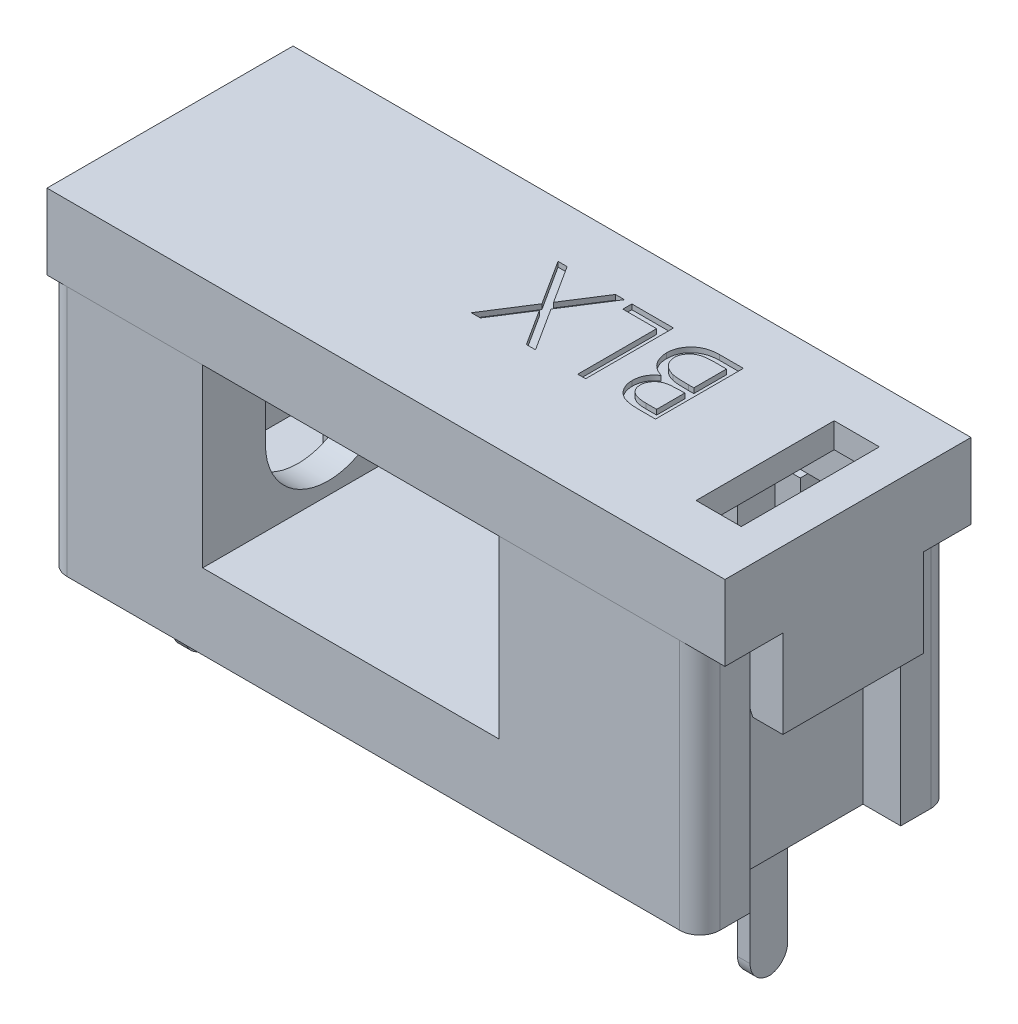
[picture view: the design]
ISO-10303-21;
HEADER;
FILE_DESCRIPTION(('STEP AP214'),'2;1');
FILE_NAME('part.step','',(''),(''),'','','');
FILE_SCHEMA(('AUTOMOTIVE_DESIGN { 1 0 10303 214 1 1 1 1 }'));
ENDSEC;
DATA;
#1=APPLICATION_CONTEXT('core data for automotive mechanical design processes');
#2=APPLICATION_PROTOCOL_DEFINITION('international standard','automotive_design',2000,#1);
#3=PRODUCT_CONTEXT('',#1,'mechanical');
#4=PRODUCT('Part','Part','',(#3));
#5=PRODUCT_RELATED_PRODUCT_CATEGORY('part','',(#4));
#6=PRODUCT_DEFINITION_FORMATION('','',#4);
#7=PRODUCT_DEFINITION_CONTEXT('part definition',#1,'design');
#8=PRODUCT_DEFINITION('design','',#6,#7);
#9=PRODUCT_DEFINITION_SHAPE('','',#8);
#10=(LENGTH_UNIT() NAMED_UNIT(*) SI_UNIT(.MILLI.,.METRE.));
#11=(NAMED_UNIT(*) PLANE_ANGLE_UNIT() SI_UNIT($,.RADIAN.));
#12=(NAMED_UNIT(*) SI_UNIT($,.STERADIAN.) SOLID_ANGLE_UNIT());
#13=UNCERTAINTY_MEASURE_WITH_UNIT(LENGTH_MEASURE(1.E-05),#10,'distance_accuracy_value','');
#14=(GEOMETRIC_REPRESENTATION_CONTEXT(3) GLOBAL_UNCERTAINTY_ASSIGNED_CONTEXT((#13)) GLOBAL_UNIT_ASSIGNED_CONTEXT((#10,
#11,#12)) REPRESENTATION_CONTEXT('',''));
#15=CARTESIAN_POINT('',(0.,0.,0.));
#16=DIRECTION('',(0.,0.,1.));
#17=DIRECTION('',(1.,0.,0.));
#18=AXIS2_PLACEMENT_3D('',#15,#16,#17);
#19=CARTESIAN_POINT('',(8.56778460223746,21.1022223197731,22.8683332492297));
#20=DIRECTION('',(0.,1.,0.));
#21=DIRECTION('',(1.,0.,0.));
#22=AXIS2_PLACEMENT_3D('',#19,#20,#21);
#23=PLANE('',#22);
#24=DIRECTION('',(1.,0.,0.));
#25=VECTOR('',#24,1.);
#26=CARTESIAN_POINT('',(10.709614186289,21.1022223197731,20.1183332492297));
#27=LINE('',#26,#25);
#28=CARTESIAN_POINT('',(10.709614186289,21.1022223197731,20.1183332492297));
#29=VERTEX_POINT('',#28);
#30=CARTESIAN_POINT('',(12.3698705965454,21.1022223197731,20.1183332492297));
#31=VERTEX_POINT('',#30);
#32=EDGE_CURVE('P0_E960',#29,#31,#27,.T.);
#33=ORIENTED_EDGE('',*,*,#32,.T.);
#34=DIRECTION('',(0.,0.,1.));
#35=VECTOR('',#34,1.);
#36=CARTESIAN_POINT('',(12.3698705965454,21.1022223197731,20.1183332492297));
#37=LINE('',#36,#35);
#38=CARTESIAN_POINT('',(12.3698705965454,21.1022223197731,23.6183332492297));
#39=VERTEX_POINT('',#38);
#40=EDGE_CURVE('P0_E859',#31,#39,#37,.T.);
#41=ORIENTED_EDGE('',*,*,#40,.T.);
#42=DIRECTION('',(-1.,0.,0.));
#43=VECTOR('',#42,1.);
#44=CARTESIAN_POINT('',(12.3698705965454,21.1022223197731,23.6183332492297));
#45=LINE('',#44,#43);
#46=CARTESIAN_POINT('',(12.0557680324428,21.1022223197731,23.6183332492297));
#47=VERTEX_POINT('',#46);
#48=EDGE_CURVE('P0_E973',#39,#47,#45,.T.);
#49=ORIENTED_EDGE('',*,*,#48,.T.);
#50=DIRECTION('',(0.,0.,-1.));
#51=VECTOR('',#50,1.);
#52=CARTESIAN_POINT('',(12.0557680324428,21.1022223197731,23.6183332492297));
#53=LINE('',#52,#51);
#54=CARTESIAN_POINT('',(12.0557680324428,21.1022223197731,20.4773076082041));
#55=VERTEX_POINT('',#54);
#56=EDGE_CURVE('P0_E970',#47,#55,#53,.T.);
#57=ORIENTED_EDGE('',*,*,#56,.T.);
#58=DIRECTION('',(-1.,0.,0.));
#59=VECTOR('',#58,1.);
#60=CARTESIAN_POINT('',(12.0557680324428,21.1022223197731,20.4773076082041));
#61=LINE('',#60,#59);
#62=CARTESIAN_POINT('',(10.709614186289,21.1022223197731,20.4773076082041));
#63=VERTEX_POINT('',#62);
#64=EDGE_CURVE('P0_E967',#55,#63,#61,.T.);
#65=ORIENTED_EDGE('',*,*,#64,.T.);
#66=DIRECTION('',(0.,0.,-1.));
#67=VECTOR('',#66,1.);
#68=CARTESIAN_POINT('',(10.709614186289,21.1022223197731,20.4773076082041));
#69=LINE('',#68,#67);
#70=EDGE_CURVE('P0_E964',#63,#29,#69,.T.);
#71=ORIENTED_EDGE('',*,*,#70,.T.);
#72=EDGE_LOOP('',(#33,#41,#49,#57,#65,#71));
#73=FACE_BOUND('',#72,.T.);
#74=DIRECTION('',(-0.539185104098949,0.,0.842187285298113));
#75=VECTOR('',#74,1.);
#76=CARTESIAN_POINT('',(10.4179475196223,21.1022223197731,20.1183332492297));
#77=LINE('',#76,#75);
#78=CARTESIAN_POINT('',(10.4179475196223,21.1022223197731,20.1183332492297));
#79=VERTEX_POINT('',#78);
#80=CARTESIAN_POINT('',(9.27511899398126,21.1022223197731,21.9033893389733));
#81=VERTEX_POINT('',#80);
#82=EDGE_CURVE('P0_E884',#79,#81,#77,.T.);
#83=ORIENTED_EDGE('',*,*,#82,.T.);
#84=DIRECTION('',(0.539190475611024,0.,0.842183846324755));
#85=VECTOR('',#84,1.);
#86=CARTESIAN_POINT('',(9.27511899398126,21.1022223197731,21.9033893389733));
#87=LINE('',#86,#85);
#88=CARTESIAN_POINT('',(10.3730757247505,21.1022223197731,23.6183332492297));
#89=VERTEX_POINT('',#88);
#90=EDGE_CURVE('P0_E918',#81,#89,#87,.T.);
#91=ORIENTED_EDGE('',*,*,#90,.T.);
#92=DIRECTION('',(-1.,0.,0.));
#93=VECTOR('',#92,1.);
#94=CARTESIAN_POINT('',(10.3730757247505,21.1022223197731,23.6183332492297));
#95=LINE('',#94,#93);
#96=CARTESIAN_POINT('',(10.0105957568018,21.1022223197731,23.6183332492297));
#97=VERTEX_POINT('',#96);
#98=EDGE_CURVE('P0_E915',#89,#97,#95,.T.);
#99=ORIENTED_EDGE('',*,*,#98,.T.);
#100=DIRECTION('',(-0.539088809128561,0.,-0.842248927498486));
#101=VECTOR('',#100,1.);
#102=CARTESIAN_POINT('',(10.0105957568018,21.1022223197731,23.6183332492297));
#103=LINE('',#102,#101);
#104=CARTESIAN_POINT('',(9.09422957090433,21.1022223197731,22.1866425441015));
#105=VERTEX_POINT('',#104);
#106=EDGE_CURVE('P0_E912',#97,#105,#103,.T.);
#107=ORIENTED_EDGE('',*,*,#106,.T.);
#108=DIRECTION('',(-0.539088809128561,0.,0.842248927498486));
#109=VECTOR('',#108,1.);
#110=CARTESIAN_POINT('',(9.09422957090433,21.1022223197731,22.1866425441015));
#111=LINE('',#110,#109);
#112=CARTESIAN_POINT('',(8.1778633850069,21.1022223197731,23.6183332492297));
#113=VERTEX_POINT('',#112);
#114=EDGE_CURVE('P0_E909',#105,#113,#111,.T.);
#115=ORIENTED_EDGE('',*,*,#114,.T.);
#116=DIRECTION('',(-1.,0.,0.));
#117=VECTOR('',#116,1.);
#118=CARTESIAN_POINT('',(8.1778633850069,21.1022223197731,23.6183332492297));
#119=LINE('',#118,#117);
#120=CARTESIAN_POINT('',(7.81538341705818,21.1022223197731,23.6183332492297));
#121=VERTEX_POINT('',#120);
#122=EDGE_CURVE('P0_E906',#113,#121,#119,.T.);
#123=ORIENTED_EDGE('',*,*,#122,.T.);
#124=DIRECTION('',(0.538946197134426,0.,-0.842340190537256));
#125=VECTOR('',#124,1.);
#126=CARTESIAN_POINT('',(7.81538341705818,21.1022223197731,23.6183332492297));
#127=LINE('',#126,#125);
#128=CARTESIAN_POINT('',(8.91263902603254,21.1022223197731,21.9033893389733));
#129=VERTEX_POINT('',#128);
#130=EDGE_CURVE('P0_E903',#121,#129,#127,.T.);
#131=ORIENTED_EDGE('',*,*,#130,.T.);
#132=DIRECTION('',(-0.538950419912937,0.,-0.842337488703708));
#133=VECTOR('',#132,1.);
#134=CARTESIAN_POINT('',(8.91263902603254,21.1022223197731,21.9033893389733));
#135=LINE('',#134,#133);
#136=CARTESIAN_POINT('',(7.77051162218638,21.1022223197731,20.1183332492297));
#137=VERTEX_POINT('',#136);
#138=EDGE_CURVE('P0_E900',#129,#137,#135,.T.);
#139=ORIENTED_EDGE('',*,*,#138,.T.);
#140=DIRECTION('',(1.,0.,0.));
#141=VECTOR('',#140,1.);
#142=CARTESIAN_POINT('',(7.77051162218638,21.1022223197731,20.1183332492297));
#143=LINE('',#142,#141);
#144=CARTESIAN_POINT('',(8.1329915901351,21.1022223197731,20.1183332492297));
#145=VERTEX_POINT('',#144);
#146=EDGE_CURVE('P0_E897',#137,#145,#143,.T.);
#147=ORIENTED_EDGE('',*,*,#146,.T.);
#148=DIRECTION('',(0.539087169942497,0.,0.842249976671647));
#149=VECTOR('',#148,1.);
#150=CARTESIAN_POINT('',(8.1329915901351,21.1022223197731,20.1183332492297));
#151=LINE('',#150,#149);
#152=CARTESIAN_POINT('',(9.09422957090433,21.1022223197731,21.6201361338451));
#153=VERTEX_POINT('',#152);
#154=EDGE_CURVE('P0_E894',#145,#153,#151,.T.);
#155=ORIENTED_EDGE('',*,*,#154,.T.);
#156=DIRECTION('',(0.539087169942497,0.,-0.842249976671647));
#157=VECTOR('',#156,1.);
#158=CARTESIAN_POINT('',(9.09422957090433,21.1022223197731,21.6201361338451));
#159=LINE('',#158,#157);
#160=CARTESIAN_POINT('',(10.0554675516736,21.1022223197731,20.1183332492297));
#161=VERTEX_POINT('',#160);
#162=EDGE_CURVE('P0_E891',#153,#161,#159,.T.);
#163=ORIENTED_EDGE('',*,*,#162,.T.);
#164=DIRECTION('',(1.,0.,0.));
#165=VECTOR('',#164,1.);
#166=CARTESIAN_POINT('',(10.0554675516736,21.1022223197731,20.1183332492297));
#167=LINE('',#166,#165);
#168=EDGE_CURVE('P0_E888',#161,#79,#167,.T.);
#169=ORIENTED_EDGE('',*,*,#168,.T.);
#170=EDGE_LOOP('',(#83,#91,#99,#107,#115,#123,#131,#139,#147,#155,#163,#169));
#171=FACE_BOUND('',#170,.T.);
#172=DIRECTION('',(1.,0.,0.));
#173=VECTOR('',#172,1.);
#174=CARTESIAN_POINT('',(-4.93221539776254,21.1022223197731,17.9683332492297));
#175=LINE('',#174,#173);
#176=CARTESIAN_POINT('',(-4.93221539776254,21.1022223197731,17.9683332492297));
#177=VERTEX_POINT('',#176);
#178=CARTESIAN_POINT('',(22.0677846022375,21.1022223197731,17.9683332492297));
#179=VERTEX_POINT('',#178);
#180=EDGE_CURVE('P0_E692',#177,#179,#175,.T.);
#181=ORIENTED_EDGE('',*,*,#180,.F.);
#182=DIRECTION('',(0.,0.,-1.));
#183=VECTOR('',#182,1.);
#184=CARTESIAN_POINT('',(-4.93221539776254,21.1022223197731,27.7683332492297));
#185=LINE('',#184,#183);
#186=CARTESIAN_POINT('',(-4.93221539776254,21.1022223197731,27.7683332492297));
#187=VERTEX_POINT('',#186);
#188=EDGE_CURVE('P0_E701',#187,#177,#185,.T.);
#189=ORIENTED_EDGE('',*,*,#188,.F.);
#190=DIRECTION('',(-1.,0.,0.));
#191=VECTOR('',#190,1.);
#192=CARTESIAN_POINT('',(-4.93221539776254,21.1022223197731,27.7683332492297));
#193=LINE('',#192,#191);
#194=CARTESIAN_POINT('',(22.0677846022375,21.1022223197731,27.7683332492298));
#195=VERTEX_POINT('',#194);
#196=EDGE_CURVE('P0_E691',#195,#187,#193,.T.);
#197=ORIENTED_EDGE('',*,*,#196,.F.);
#198=DIRECTION('',(0.,0.,1.));
#199=VECTOR('',#198,1.);
#200=CARTESIAN_POINT('',(22.0677846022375,21.1022223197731,27.7683332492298));
#201=LINE('',#200,#199);
#202=EDGE_CURVE('P0_E679',#179,#195,#201,.T.);
#203=ORIENTED_EDGE('',*,*,#202,.F.);
#204=EDGE_LOOP('',(#181,#189,#197,#203));
#205=FACE_BOUND('',#204,.T.);
#206=DIRECTION('',(1.,0.,0.));
#207=VECTOR('',#206,1.);
#208=CARTESIAN_POINT('',(18.7677846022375,21.1022223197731,25.6183332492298));
#209=LINE('',#208,#207);
#210=CARTESIAN_POINT('',(18.7677846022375,21.1022223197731,25.6183332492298));
#211=VERTEX_POINT('',#210);
#212=CARTESIAN_POINT('',(20.5677846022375,21.1022223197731,25.6183332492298));
#213=VERTEX_POINT('',#212);
#214=EDGE_CURVE('P0_E814',#211,#213,#209,.T.);
#215=ORIENTED_EDGE('',*,*,#214,.F.);
#216=DIRECTION('',(0.,0.,1.));
#217=VECTOR('',#216,1.);
#218=CARTESIAN_POINT('',(18.7677846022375,21.1022223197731,20.1183332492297));
#219=LINE('',#218,#217);
#220=CARTESIAN_POINT('',(18.7677846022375,21.1022223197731,20.1183332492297));
#221=VERTEX_POINT('',#220);
#222=EDGE_CURVE('P0_E815',#221,#211,#219,.T.);
#223=ORIENTED_EDGE('',*,*,#222,.F.);
#224=DIRECTION('',(-1.,0.,0.));
#225=VECTOR('',#224,1.);
#226=CARTESIAN_POINT('',(20.5677846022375,21.1022223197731,20.1183332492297));
#227=LINE('',#226,#225);
#228=CARTESIAN_POINT('',(20.5677846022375,21.1022223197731,20.1183332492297));
#229=VERTEX_POINT('',#228);
#230=EDGE_CURVE('P0_E733',#229,#221,#227,.T.);
#231=ORIENTED_EDGE('',*,*,#230,.F.);
#232=DIRECTION('',(0.,0.,-1.));
#233=VECTOR('',#232,1.);
#234=CARTESIAN_POINT('',(20.5677846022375,21.1022223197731,25.6183332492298));
#235=LINE('',#234,#233);
#236=EDGE_CURVE('P0_E852',#213,#229,#235,.T.);
#237=ORIENTED_EDGE('',*,*,#236,.F.);
#238=EDGE_LOOP('',(#215,#223,#231,#237));
#239=FACE_BOUND('',#238,.T.);
#240=DIRECTION('',(1.,0.,0.));
#241=VECTOR('',#240,1.);
#242=CARTESIAN_POINT('',(14.2054074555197,21.1022223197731,20.1183332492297));
#243=LINE('',#242,#241);
#244=CARTESIAN_POINT('',(14.2054074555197,21.1022223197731,20.1183332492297));
#245=VERTEX_POINT('',#244);
#246=CARTESIAN_POINT('',(15.1519218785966,21.1022223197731,20.1183332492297));
#247=VERTEX_POINT('',#246);
#248=EDGE_CURVE('P0_E488',#245,#247,#243,.T.);
#249=ORIENTED_EDGE('',*,*,#248,.T.);
#250=DIRECTION('',(0.,0.,1.));
#251=VECTOR('',#250,1.);
#252=CARTESIAN_POINT('',(15.1519218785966,21.1022223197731,20.1183332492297));
#253=LINE('',#252,#251);
#254=CARTESIAN_POINT('',(15.1519218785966,21.1022223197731,23.6183332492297));
#255=VERTEX_POINT('',#254);
#256=EDGE_CURVE('P0_E31',#247,#255,#253,.T.);
#257=ORIENTED_EDGE('',*,*,#256,.T.);
#258=DIRECTION('',(-1.,0.,0.));
#259=VECTOR('',#258,1.);
#260=CARTESIAN_POINT('',(15.1519218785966,21.1022223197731,23.6183332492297));
#261=LINE('',#260,#259);
#262=CARTESIAN_POINT('',(14.4690292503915,21.1022223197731,23.6183332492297));
#263=VERTEX_POINT('',#262);
#264=EDGE_CURVE('P0_E1034',#255,#263,#261,.T.);
#265=ORIENTED_EDGE('',*,*,#264,.T.);
#266=CARTESIAN_POINT('',(14.4690292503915,21.1022223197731,23.6183332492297));
#267=CARTESIAN_POINT('',(14.435600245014,21.1022223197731,23.6181602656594));
#268=CARTESIAN_POINT('',(14.3708065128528,21.1022223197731,23.6178249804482));
#269=CARTESIAN_POINT('',(14.2765942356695,21.1022223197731,23.6125042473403));
#270=CARTESIAN_POINT('',(14.1883206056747,21.1022223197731,23.6054308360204));
#271=CARTESIAN_POINT('',(14.1061416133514,21.1022223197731,23.5935655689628));
#272=CARTESIAN_POINT('',(14.029522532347,21.1022223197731,23.5812628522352));
#273=CARTESIAN_POINT('',(13.9592412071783,21.1022223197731,23.5632054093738));
#274=CARTESIAN_POINT('',(13.894708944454,21.1022223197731,23.5432603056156));
#275=CARTESIAN_POINT('',(13.8172189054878,21.1022223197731,23.5125720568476));
#276=CARTESIAN_POINT('',(13.7292958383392,21.1022223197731,23.4649128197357));
#277=CARTESIAN_POINT('',(13.6347949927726,21.1022223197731,23.3942296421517));
#278=CARTESIAN_POINT('',(13.5526490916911,21.1022223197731,23.3094862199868));
#279=CARTESIAN_POINT('',(13.4828007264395,21.1022223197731,23.2129144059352));
#280=CARTESIAN_POINT('',(13.4267459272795,21.1022223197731,23.1066744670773));
#281=CARTESIAN_POINT('',(13.386705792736,21.1022223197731,22.9930521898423));
#282=CARTESIAN_POINT('',(13.3609824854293,21.1022223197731,22.8739591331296));
#283=CARTESIAN_POINT('',(13.3583702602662,21.1022223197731,22.7923098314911));
#284=CARTESIAN_POINT('',(13.3570500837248,21.1022223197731,22.7510455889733));
#285=B_SPLINE_CURVE_WITH_KNOTS('',3,(#266,#267,#268,#269,#270,#271,#272,#273,#274,#275,#276,
#277,#278,#279,#280,#281,#282,#283,#284),.UNSPECIFIED.,.F.,.F.,(4,1,1,1,1,1,1,1,1,1,1,1,1,1,1,1,
4),(0.,0.0625801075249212,0.12129582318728,0.176640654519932,0.228314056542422,
0.276729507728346,0.321834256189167,0.364044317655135,0.403128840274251,0.477724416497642,
0.550537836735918,0.623256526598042,0.697830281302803,0.772992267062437,0.847315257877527,
0.922835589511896,1.),.UNSPECIFIED.);
#286=CARTESIAN_POINT('',(13.3570500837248,21.1022223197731,22.7510455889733));
#287=VERTEX_POINT('',#286);
#288=EDGE_CURVE('P0_E1026',#263,#287,#285,.T.);
#289=ORIENTED_EDGE('',*,*,#288,.T.);
#290=CARTESIAN_POINT('',(13.3570500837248,21.1022223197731,22.7510455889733));
#291=CARTESIAN_POINT('',(13.3581496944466,21.1022223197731,22.7123947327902));
#292=CARTESIAN_POINT('',(13.3603105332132,21.1022223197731,22.6364421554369));
#293=CARTESIAN_POINT('',(13.380721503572,21.1022223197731,22.525544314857));
#294=CARTESIAN_POINT('',(13.4131166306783,21.1022223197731,22.4200869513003));
#295=CARTESIAN_POINT('',(13.4578880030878,21.1022223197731,22.3201603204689));
#296=CARTESIAN_POINT('',(13.5155734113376,21.1022223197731,22.2276245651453));
#297=CARTESIAN_POINT('',(13.5846886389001,21.1022223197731,22.142766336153));
#298=CARTESIAN_POINT('',(13.6677300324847,21.1022223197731,22.0687928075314));
#299=CARTESIAN_POINT('',(13.7299781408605,21.1022223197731,22.0274529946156));
#300=CARTESIAN_POINT('',(13.7615973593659,21.1022223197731,22.0064542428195));
#301=B_SPLINE_CURVE_WITH_KNOTS('',3,(#290,#291,#292,#293,#294,#295,#296,#297,#298,#299,#300),
.UNSPECIFIED.,.F.,.F.,(4,1,1,1,1,1,1,1,4),(0.,0.130580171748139,0.25660235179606,
0.379828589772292,0.502910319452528,0.625707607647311,0.747527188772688,0.871755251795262,1.),.UNSPECIFIED.);
#302=CARTESIAN_POINT('',(13.7615973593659,21.1022223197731,22.0064542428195));
#303=VERTEX_POINT('',#302);
#304=EDGE_CURVE('P0_E1018',#287,#303,#301,.T.);
#305=ORIENTED_EDGE('',*,*,#304,.T.);
#306=CARTESIAN_POINT('',(13.7615973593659,21.1022223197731,22.0064542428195));
#307=CARTESIAN_POINT('',(13.7218407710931,21.1022223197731,21.9911843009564));
#308=CARTESIAN_POINT('',(13.645776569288,21.1022223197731,21.9619691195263));
#309=CARTESIAN_POINT('',(13.541040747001,21.1022223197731,21.9103977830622));
#310=CARTESIAN_POINT('',(13.4511332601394,21.1022223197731,21.8541027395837));
#311=CARTESIAN_POINT('',(13.3742978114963,21.1022223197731,21.7935755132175));
#312=CARTESIAN_POINT('',(13.3089307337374,21.1022223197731,21.7273713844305));
#313=CARTESIAN_POINT('',(13.2523190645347,21.1022223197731,21.6549524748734));
#314=CARTESIAN_POINT('',(13.2033771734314,21.1022223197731,21.5763780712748));
#315=CARTESIAN_POINT('',(13.1617279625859,21.1022223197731,21.4919369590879));
#316=CARTESIAN_POINT('',(13.1290119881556,21.1022223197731,21.4023449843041));
#317=CARTESIAN_POINT('',(13.1049662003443,21.1022223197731,21.3086964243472));
#318=CARTESIAN_POINT('',(13.0907425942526,21.1022223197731,21.2113502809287));
#319=CARTESIAN_POINT('',(13.0888022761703,21.1022223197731,21.1452892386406));
#320=CARTESIAN_POINT('',(13.0878193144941,21.1022223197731,21.1118228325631));
#321=B_SPLINE_CURVE_WITH_KNOTS('',3,(#306,#307,#308,#309,#310,#311,#312,#313,#314,#315,#316,
#317,#318,#319,#320),.UNSPECIFIED.,.F.,.F.,(4,1,1,1,1,1,1,1,1,1,1,1,4),(0.,0.106048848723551,
0.202897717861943,0.290276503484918,0.369828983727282,0.445983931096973,0.521448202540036,
0.598336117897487,0.676181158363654,0.755560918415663,0.835476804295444,0.916652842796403,1.),.UNSPECIFIED.);
#322=CARTESIAN_POINT('',(13.0878193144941,21.1022223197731,21.1118228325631));
#323=VERTEX_POINT('',#322);
#324=EDGE_CURVE('P0_E1010',#303,#323,#321,.T.);
#325=ORIENTED_EDGE('',*,*,#324,.T.);
#326=CARTESIAN_POINT('',(13.0878193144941,21.1022223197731,21.1118228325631));
#327=CARTESIAN_POINT('',(13.0887959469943,21.1022223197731,21.077655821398));
#328=CARTESIAN_POINT('',(13.0907174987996,21.1022223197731,21.0104312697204));
#329=CARTESIAN_POINT('',(13.1049005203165,21.1022223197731,20.9116781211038));
#330=CARTESIAN_POINT('',(13.1288984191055,21.1022223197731,20.8172958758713));
#331=CARTESIAN_POINT('',(13.1620108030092,21.1022223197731,20.7267175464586));
#332=CARTESIAN_POINT('',(13.20492996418,21.1022223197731,20.6401330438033));
#333=CARTESIAN_POINT('',(13.2579160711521,21.1022223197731,20.5578560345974));
#334=CARTESIAN_POINT('',(13.3202253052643,21.1022223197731,20.479715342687));
#335=CARTESIAN_POINT('',(13.3906448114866,21.1022223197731,20.4055730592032));
#336=CARTESIAN_POINT('',(13.4691218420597,21.1022223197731,20.3377305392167));
#337=CARTESIAN_POINT('',(13.5556085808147,21.1022223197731,20.2794088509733));
#338=CARTESIAN_POINT('',(13.6477357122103,21.1022223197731,20.2292605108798));
#339=CARTESIAN_POINT('',(13.7466809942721,21.1022223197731,20.1884315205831));
#340=CARTESIAN_POINT('',(13.8521918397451,21.1022223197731,20.1569319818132));
#341=CARTESIAN_POINT('',(13.9642095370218,21.1022223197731,20.1349854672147));
#342=CARTESIAN_POINT('',(14.0825496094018,21.1022223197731,20.1201731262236));
#343=CARTESIAN_POINT('',(14.1637599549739,21.1022223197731,20.1189569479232));
#344=CARTESIAN_POINT('',(14.2054074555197,21.1022223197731,20.1183332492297));
#345=B_SPLINE_CURVE_WITH_KNOTS('',3,(#326,#327,#328,#329,#330,#331,#332,#333,#334,#335,#336,
#337,#338,#339,#340,#341,#342,#343,#344),.UNSPECIFIED.,.F.,.F.,(4,1,1,1,1,1,1,1,1,1,1,1,1,1,1,1,
4),(0.,0.061167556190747,0.12034888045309,0.178201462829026,0.235263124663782,0.292717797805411,
0.350875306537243,0.410152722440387,0.471423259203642,0.533743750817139,0.595492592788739,
0.657846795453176,0.721262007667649,0.786797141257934,0.854668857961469,0.925469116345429,1.),.UNSPECIFIED.);
#346=EDGE_CURVE('P0_E1005',#323,#245,#345,.T.);
#347=ORIENTED_EDGE('',*,*,#346,.T.);
#348=EDGE_LOOP('',(#249,#257,#265,#289,#305,#325,#347));
#349=FACE_BOUND('',#348,.T.);
#350=ADVANCED_FACE('P0_F16',(#73,#171,#205,#239,#349),#23,.T.);
#351=CARTESIAN_POINT('',(8.56778460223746,18.1022223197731,22.8683332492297));
#352=DIRECTION('',(0.,1.,0.));
#353=DIRECTION('',(1.,0.,0.));
#354=AXIS2_PLACEMENT_3D('',#351,#352,#353);
#355=PLANE('',#354);
#356=DIRECTION('',(0.,0.,1.));
#357=VECTOR('',#356,1.);
#358=CARTESIAN_POINT('',(20.5677846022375,18.1022223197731,19.4683332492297));
#359=LINE('',#358,#357);
#360=CARTESIAN_POINT('',(20.5677846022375,18.1022223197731,19.4683332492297));
#361=VERTEX_POINT('',#360);
#362=CARTESIAN_POINT('',(20.5677846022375,18.1022223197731,26.2683332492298));
#363=VERTEX_POINT('',#362);
#364=EDGE_CURVE('P0_E761',#361,#363,#359,.T.);
#365=ORIENTED_EDGE('',*,*,#364,.F.);
#366=DIRECTION('',(1.,0.,0.));
#367=VECTOR('',#366,1.);
#368=CARTESIAN_POINT('',(-3.43221539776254,18.1022223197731,19.4683332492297));
#369=LINE('',#368,#367);
#370=CARTESIAN_POINT('',(-3.43221539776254,18.1022223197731,19.4683332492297));
#371=VERTEX_POINT('',#370);
#372=EDGE_CURVE('P0_E759',#371,#361,#369,.T.);
#373=ORIENTED_EDGE('',*,*,#372,.F.);
#374=DIRECTION('',(0.,0.,-1.));
#375=VECTOR('',#374,1.);
#376=CARTESIAN_POINT('',(-3.43221539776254,18.1022223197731,26.2683332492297));
#377=LINE('',#376,#375);
#378=CARTESIAN_POINT('',(-3.43221539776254,18.1022223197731,26.2683332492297));
#379=VERTEX_POINT('',#378);
#380=EDGE_CURVE('P0_E755',#379,#371,#377,.T.);
#381=ORIENTED_EDGE('',*,*,#380,.F.);
#382=DIRECTION('',(-1.,0.,0.));
#383=VECTOR('',#382,1.);
#384=CARTESIAN_POINT('',(20.5677846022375,18.1022223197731,26.2683332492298));
#385=LINE('',#384,#383);
#386=EDGE_CURVE('P0_E753',#363,#379,#385,.T.);
#387=ORIENTED_EDGE('',*,*,#386,.F.);
#388=EDGE_LOOP('',(#365,#373,#381,#387));
#389=FACE_BOUND('',#388,.T.);
#390=DIRECTION('',(1.,0.,0.));
#391=VECTOR('',#390,1.);
#392=CARTESIAN_POINT('',(19.5677846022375,18.1022223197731,19.8683332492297));
#393=LINE('',#392,#391);
#394=CARTESIAN_POINT('',(20.8688043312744,18.1022223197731,19.8683332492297));
#395=VERTEX_POINT('',#394);
#396=CARTESIAN_POINT('',(22.0677846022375,18.1022223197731,19.8683332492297));
#397=VERTEX_POINT('',#396);
#398=EDGE_CURVE('P0_E713',#395,#397,#393,.T.);
#399=ORIENTED_EDGE('',*,*,#398,.F.);
#400=DIRECTION('',(0.,0.,1.));
#401=VECTOR('',#400,1.);
#402=CARTESIAN_POINT('',(20.8688043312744,18.1022223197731,17.9683332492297));
#403=LINE('',#402,#401);
#404=CARTESIAN_POINT('',(20.8688043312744,18.1022223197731,25.4630368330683));
#405=VERTEX_POINT('',#404);
#406=EDGE_CURVE('P0_E837',#395,#405,#403,.T.);
#407=ORIENTED_EDGE('',*,*,#406,.T.);
#408=DIRECTION('',(-1.,0.,0.));
#409=VECTOR('',#408,1.);
#410=CARTESIAN_POINT('',(22.0677846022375,18.1022223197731,25.4630368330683));
#411=LINE('',#410,#409);
#412=CARTESIAN_POINT('',(22.0677846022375,18.1022223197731,25.4630368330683));
#413=VERTEX_POINT('',#412);
#414=EDGE_CURVE('P0_E782',#413,#405,#411,.T.);
#415=ORIENTED_EDGE('',*,*,#414,.F.);
#416=DIRECTION('',(0.,0.,1.));
#417=VECTOR('',#416,1.);
#418=CARTESIAN_POINT('',(22.0677846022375,18.1022223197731,27.7683332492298));
#419=LINE('',#418,#417);
#420=CARTESIAN_POINT('',(22.0677846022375,18.1022223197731,27.7683332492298));
#421=VERTEX_POINT('',#420);
#422=EDGE_CURVE('P0_E771',#413,#421,#419,.T.);
#423=ORIENTED_EDGE('',*,*,#422,.T.);
#424=DIRECTION('',(-1.,0.,0.));
#425=VECTOR('',#424,1.);
#426=CARTESIAN_POINT('',(-4.93221539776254,18.1022223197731,27.7683332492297));
#427=LINE('',#426,#425);
#428=CARTESIAN_POINT('',(-4.93221539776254,18.1022223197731,27.7683332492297));
#429=VERTEX_POINT('',#428);
#430=EDGE_CURVE('P0_E696',#421,#429,#427,.T.);
#431=ORIENTED_EDGE('',*,*,#430,.T.);
#432=DIRECTION('',(0.,0.,-1.));
#433=VECTOR('',#432,1.);
#434=CARTESIAN_POINT('',(-4.93221539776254,18.1022223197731,27.7683332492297));
#435=LINE('',#434,#433);
#436=CARTESIAN_POINT('',(-4.93221539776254,18.1022223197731,17.9683332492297));
#437=VERTEX_POINT('',#436);
#438=EDGE_CURVE('P0_E710',#429,#437,#435,.T.);
#439=ORIENTED_EDGE('',*,*,#438,.T.);
#440=DIRECTION('',(1.,0.,0.));
#441=VECTOR('',#440,1.);
#442=CARTESIAN_POINT('',(-4.93221539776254,18.1022223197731,17.9683332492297));
#443=LINE('',#442,#441);
#444=CARTESIAN_POINT('',(22.0677846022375,18.1022223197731,17.9683332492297));
#445=VERTEX_POINT('',#444);
#446=EDGE_CURVE('P0_E703',#437,#445,#443,.T.);
#447=ORIENTED_EDGE('',*,*,#446,.T.);
#448=EDGE_CURVE('P0_E772',#445,#397,#419,.T.);
#449=ORIENTED_EDGE('',*,*,#448,.T.);
#450=EDGE_LOOP('',(#399,#407,#415,#423,#431,#439,#447,#449));
#451=FACE_BOUND('',#450,.T.);
#452=ADVANCED_FACE('P0_F655',(#389,#451),#355,.F.);
#453=CARTESIAN_POINT('',(-4.93221539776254,18.1022223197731,17.9683332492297));
#454=DIRECTION('',(0.,0.,1.));
#455=DIRECTION('',(-1.,0.,0.));
#456=AXIS2_PLACEMENT_3D('',#453,#454,#455);
#457=PLANE('',#456);
#458=ORIENTED_EDGE('',*,*,#180,.T.);
#459=DIRECTION('',(0.,1.,0.));
#460=VECTOR('',#459,1.);
#461=CARTESIAN_POINT('',(22.0677846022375,18.1022223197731,17.9683332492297));
#462=LINE('',#461,#460);
#463=EDGE_CURVE('P0_E686',#445,#179,#462,.T.);
#464=ORIENTED_EDGE('',*,*,#463,.F.);
#465=ORIENTED_EDGE('',*,*,#446,.F.);
#466=DIRECTION('',(0.,1.,0.));
#467=VECTOR('',#466,1.);
#468=CARTESIAN_POINT('',(-4.93221539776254,18.1022223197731,17.9683332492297));
#469=LINE('',#468,#467);
#470=EDGE_CURVE('P0_E707',#437,#177,#469,.T.);
#471=ORIENTED_EDGE('',*,*,#470,.T.);
#472=EDGE_LOOP('',(#458,#464,#465,#471));
#473=FACE_BOUND('',#472,.T.);
#474=ADVANCED_FACE('P0_F18',(#473),#457,.F.);
#475=CARTESIAN_POINT('',(22.0677846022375,18.1022223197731,27.7683332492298));
#476=DIRECTION('',(-1.,0.,0.));
#477=DIRECTION('',(0.,0.,-1.));
#478=AXIS2_PLACEMENT_3D('',#475,#476,#477);
#479=PLANE('',#478);
#480=ORIENTED_EDGE('',*,*,#202,.T.);
#481=DIRECTION('',(0.,1.,0.));
#482=VECTOR('',#481,1.);
#483=CARTESIAN_POINT('',(22.0677846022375,18.1022223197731,27.7683332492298));
#484=LINE('',#483,#482);
#485=EDGE_CURVE('P0_E682',#421,#195,#484,.T.);
#486=ORIENTED_EDGE('',*,*,#485,.F.);
#487=ORIENTED_EDGE('',*,*,#422,.F.);
#488=DIRECTION('',(0.,1.,0.));
#489=VECTOR('',#488,1.);
#490=CARTESIAN_POINT('',(22.0677846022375,14.6022223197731,25.4630368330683));
#491=LINE('',#490,#489);
#492=CARTESIAN_POINT('',(22.0677846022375,14.6022223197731,25.4630368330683));
#493=VERTEX_POINT('',#492);
#494=EDGE_CURVE('P0_E756',#493,#413,#491,.T.);
#495=ORIENTED_EDGE('',*,*,#494,.F.);
#496=DIRECTION('',(0.,0.,1.));
#497=VECTOR('',#496,1.);
#498=CARTESIAN_POINT('',(22.0677846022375,14.6022223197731,22.8683332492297));
#499=LINE('',#498,#497);
#500=CARTESIAN_POINT('',(22.0677846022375,14.6022223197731,19.8683332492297));
#501=VERTEX_POINT('',#500);
#502=EDGE_CURVE('P0_E840',#501,#493,#499,.T.);
#503=ORIENTED_EDGE('',*,*,#502,.F.);
#504=DIRECTION('',(0.,1.,0.));
#505=VECTOR('',#504,1.);
#506=CARTESIAN_POINT('',(22.0677846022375,14.6022223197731,19.8683332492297));
#507=LINE('',#506,#505);
#508=EDGE_CURVE('P0_E792',#501,#397,#507,.T.);
#509=ORIENTED_EDGE('',*,*,#508,.T.);
#510=ORIENTED_EDGE('',*,*,#448,.F.);
#511=ORIENTED_EDGE('',*,*,#463,.T.);
#512=EDGE_LOOP('',(#480,#486,#487,#495,#503,#509,#510,#511));
#513=FACE_BOUND('',#512,.T.);
#514=ADVANCED_FACE('P0_F668',(#513),#479,.F.);
#515=CARTESIAN_POINT('',(-4.93221539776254,18.1022223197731,27.7683332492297));
#516=DIRECTION('',(0.,0.,-1.));
#517=DIRECTION('',(1.,0.,0.));
#518=AXIS2_PLACEMENT_3D('',#515,#516,#517);
#519=PLANE('',#518);
#520=ORIENTED_EDGE('',*,*,#196,.T.);
#521=DIRECTION('',(0.,1.,0.));
#522=VECTOR('',#521,1.);
#523=CARTESIAN_POINT('',(-4.93221539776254,18.1022223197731,27.7683332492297));
#524=LINE('',#523,#522);
#525=EDGE_CURVE('P0_E697',#429,#187,#524,.T.);
#526=ORIENTED_EDGE('',*,*,#525,.F.);
#527=ORIENTED_EDGE('',*,*,#430,.F.);
#528=ORIENTED_EDGE('',*,*,#485,.T.);
#529=EDGE_LOOP('',(#520,#526,#527,#528));
#530=FACE_BOUND('',#529,.T.);
#531=ADVANCED_FACE('P0_F665',(#530),#519,.F.);
#532=CARTESIAN_POINT('',(-4.93221539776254,18.1022223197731,27.7683332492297));
#533=DIRECTION('',(1.,0.,0.));
#534=DIRECTION('',(0.,0.,1.));
#535=AXIS2_PLACEMENT_3D('',#532,#533,#534);
#536=PLANE('',#535);
#537=ORIENTED_EDGE('',*,*,#188,.T.);
#538=ORIENTED_EDGE('',*,*,#470,.F.);
#539=ORIENTED_EDGE('',*,*,#438,.F.);
#540=ORIENTED_EDGE('',*,*,#525,.T.);
#541=EDGE_LOOP('',(#537,#538,#539,#540));
#542=FACE_BOUND('',#541,.T.);
#543=ADVANCED_FACE('P0_F653',(#542),#536,.F.);
#544=CARTESIAN_POINT('',(20.5677846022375,20.1022223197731,26.2683332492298));
#545=DIRECTION('',(0.,0.,1.));
#546=DIRECTION('',(-1.,0.,0.));
#547=AXIS2_PLACEMENT_3D('',#544,#545,#546);
#548=PLANE('',#547);
#549=ORIENTED_EDGE('',*,*,#386,.T.);
#550=DIRECTION('',(0.,-1.,0.));
#551=VECTOR('',#550,1.);
#552=CARTESIAN_POINT('',(-3.43221539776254,20.1022223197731,26.2683332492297));
#553=LINE('',#552,#551);
#554=CARTESIAN_POINT('',(-3.43221539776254,20.1022223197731,26.2683332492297));
#555=VERTEX_POINT('',#554);
#556=EDGE_CURVE('P0_E744',#555,#379,#553,.T.);
#557=ORIENTED_EDGE('',*,*,#556,.F.);
#558=DIRECTION('',(-1.,0.,0.));
#559=VECTOR('',#558,1.);
#560=CARTESIAN_POINT('',(20.5677846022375,20.1022223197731,26.2683332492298));
#561=LINE('',#560,#559);
#562=CARTESIAN_POINT('',(20.5677846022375,20.1022223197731,26.2683332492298));
#563=VERTEX_POINT('',#562);
#564=EDGE_CURVE('P0_E763',#563,#555,#561,.T.);
#565=ORIENTED_EDGE('',*,*,#564,.F.);
#566=DIRECTION('',(0.,-1.,0.));
#567=VECTOR('',#566,1.);
#568=CARTESIAN_POINT('',(20.5677846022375,20.1022223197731,26.2683332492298));
#569=LINE('',#568,#567);
#570=EDGE_CURVE('P0_E764',#563,#363,#569,.T.);
#571=ORIENTED_EDGE('',*,*,#570,.T.);
#572=EDGE_LOOP('',(#549,#557,#565,#571));
#573=FACE_BOUND('',#572,.T.);
#574=ADVANCED_FACE('P0_F643',(#573),#548,.F.);
#575=CARTESIAN_POINT('',(20.5677846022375,20.1022223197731,19.4683332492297));
#576=DIRECTION('',(1.,0.,0.));
#577=DIRECTION('',(0.,0.,1.));
#578=AXIS2_PLACEMENT_3D('',#575,#576,#577);
#579=PLANE('',#578);
#580=ORIENTED_EDGE('',*,*,#364,.T.);
#581=ORIENTED_EDGE('',*,*,#570,.F.);
#582=DIRECTION('',(0.,0.,1.));
#583=VECTOR('',#582,1.);
#584=CARTESIAN_POINT('',(20.5677846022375,20.1022223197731,19.4683332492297));
#585=LINE('',#584,#583);
#586=CARTESIAN_POINT('',(20.5677846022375,20.1022223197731,25.6183332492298));
#587=VERTEX_POINT('',#586);
#588=EDGE_CURVE('P0_E745',#587,#563,#585,.T.);
#589=ORIENTED_EDGE('',*,*,#588,.F.);
#590=DIRECTION('',(0.,1.,0.));
#591=VECTOR('',#590,1.);
#592=CARTESIAN_POINT('',(20.5677846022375,18.1022223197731,25.6183332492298));
#593=LINE('',#592,#591);
#594=EDGE_CURVE('P0_E811',#587,#213,#593,.T.);
#595=ORIENTED_EDGE('',*,*,#594,.T.);
#596=ORIENTED_EDGE('',*,*,#236,.T.);
#597=DIRECTION('',(0.,1.,0.));
#598=VECTOR('',#597,1.);
#599=CARTESIAN_POINT('',(20.5677846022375,18.1022223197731,20.1183332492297));
#600=LINE('',#599,#598);
#601=CARTESIAN_POINT('',(20.5677846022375,20.1022223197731,20.1183332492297));
#602=VERTEX_POINT('',#601);
#603=EDGE_CURVE('P0_E735',#602,#229,#600,.T.);
#604=ORIENTED_EDGE('',*,*,#603,.F.);
#605=CARTESIAN_POINT('',(20.5677846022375,20.1022223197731,19.4683332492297));
#606=VERTEX_POINT('',#605);
#607=EDGE_CURVE('P0_E739',#606,#602,#585,.T.);
#608=ORIENTED_EDGE('',*,*,#607,.F.);
#609=DIRECTION('',(0.,-1.,0.));
#610=VECTOR('',#609,1.);
#611=CARTESIAN_POINT('',(20.5677846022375,20.1022223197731,19.4683332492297));
#612=LINE('',#611,#610);
#613=EDGE_CURVE('P0_E767',#606,#361,#612,.T.);
#614=ORIENTED_EDGE('',*,*,#613,.T.);
#615=EDGE_LOOP('',(#580,#581,#589,#595,#596,#604,#608,#614));
#616=FACE_BOUND('',#615,.T.);
#617=ADVANCED_FACE('P0_F639',(#616),#579,.F.);
#618=CARTESIAN_POINT('',(-3.43221539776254,20.1022223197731,19.4683332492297));
#619=DIRECTION('',(0.,0.,-1.));
#620=DIRECTION('',(1.,0.,0.));
#621=AXIS2_PLACEMENT_3D('',#618,#619,#620);
#622=PLANE('',#621);
#623=ORIENTED_EDGE('',*,*,#372,.T.);
#624=ORIENTED_EDGE('',*,*,#613,.F.);
#625=DIRECTION('',(1.,0.,0.));
#626=VECTOR('',#625,1.);
#627=CARTESIAN_POINT('',(-3.43221539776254,20.1022223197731,19.4683332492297));
#628=LINE('',#627,#626);
#629=CARTESIAN_POINT('',(-3.43221539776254,20.1022223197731,19.4683332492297));
#630=VERTEX_POINT('',#629);
#631=EDGE_CURVE('P0_E742',#630,#606,#628,.T.);
#632=ORIENTED_EDGE('',*,*,#631,.F.);
#633=DIRECTION('',(0.,-1.,0.));
#634=VECTOR('',#633,1.);
#635=CARTESIAN_POINT('',(-3.43221539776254,20.1022223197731,19.4683332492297));
#636=LINE('',#635,#634);
#637=EDGE_CURVE('P0_E748',#630,#371,#636,.T.);
#638=ORIENTED_EDGE('',*,*,#637,.T.);
#639=EDGE_LOOP('',(#623,#624,#632,#638));
#640=FACE_BOUND('',#639,.T.);
#641=ADVANCED_FACE('P0_F642',(#640),#622,.F.);
#642=CARTESIAN_POINT('',(-3.43221539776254,20.1022223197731,26.2683332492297));
#643=DIRECTION('',(-1.,0.,0.));
#644=DIRECTION('',(0.,0.,-1.));
#645=AXIS2_PLACEMENT_3D('',#642,#643,#644);
#646=PLANE('',#645);
#647=ORIENTED_EDGE('',*,*,#380,.T.);
#648=ORIENTED_EDGE('',*,*,#637,.F.);
#649=DIRECTION('',(0.,0.,-1.));
#650=VECTOR('',#649,1.);
#651=CARTESIAN_POINT('',(-3.43221539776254,20.1022223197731,26.2683332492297));
#652=LINE('',#651,#650);
#653=EDGE_CURVE('P0_E800',#555,#630,#652,.T.);
#654=ORIENTED_EDGE('',*,*,#653,.F.);
#655=ORIENTED_EDGE('',*,*,#556,.T.);
#656=EDGE_LOOP('',(#647,#648,#654,#655));
#657=FACE_BOUND('',#656,.T.);
#658=ADVANCED_FACE('P0_F637',(#657),#646,.F.);
#659=CARTESIAN_POINT('',(8.56778460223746,20.1022223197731,22.8683332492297));
#660=DIRECTION('',(0.,-1.,0.));
#661=DIRECTION('',(-1.,0.,0.));
#662=AXIS2_PLACEMENT_3D('',#659,#660,#661);
#663=PLANE('',#662);
#664=DIRECTION('',(-1.,0.,0.));
#665=VECTOR('',#664,1.);
#666=CARTESIAN_POINT('',(8.56778460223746,20.1022223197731,25.6183332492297));
#667=LINE('',#666,#665);
#668=CARTESIAN_POINT('',(18.7677846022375,20.1022223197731,25.6183332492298));
#669=VERTEX_POINT('',#668);
#670=EDGE_CURVE('P0_E10',#587,#669,#667,.T.);
#671=ORIENTED_EDGE('',*,*,#670,.F.);
#672=ORIENTED_EDGE('',*,*,#588,.T.);
#673=ORIENTED_EDGE('',*,*,#564,.T.);
#674=ORIENTED_EDGE('',*,*,#653,.T.);
#675=ORIENTED_EDGE('',*,*,#631,.T.);
#676=ORIENTED_EDGE('',*,*,#607,.T.);
#677=DIRECTION('',(1.,0.,0.));
#678=VECTOR('',#677,1.);
#679=CARTESIAN_POINT('',(8.56778460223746,20.1022223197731,20.1183332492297));
#680=LINE('',#679,#678);
#681=CARTESIAN_POINT('',(18.7677846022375,20.1022223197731,20.1183332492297));
#682=VERTEX_POINT('',#681);
#683=EDGE_CURVE('P0_E720',#682,#602,#680,.T.);
#684=ORIENTED_EDGE('',*,*,#683,.F.);
#685=DIRECTION('',(0.,0.,-1.));
#686=VECTOR('',#685,1.);
#687=CARTESIAN_POINT('',(18.7677846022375,20.1022223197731,22.8683332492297));
#688=LINE('',#687,#686);
#689=EDGE_CURVE('P0_E24',#669,#682,#688,.T.);
#690=ORIENTED_EDGE('',*,*,#689,.F.);
#691=EDGE_LOOP('',(#671,#672,#673,#674,#675,#676,#684,#690));
#692=FACE_BOUND('',#691,.T.);
#693=ADVANCED_FACE('P0_F633',(#692),#663,.T.);
#694=CARTESIAN_POINT('',(22.0677846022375,14.6022223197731,25.4630368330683));
#695=DIRECTION('',(0.,0.,-1.));
#696=DIRECTION('',(1.,0.,0.));
#697=AXIS2_PLACEMENT_3D('',#694,#695,#696);
#698=PLANE('',#697);
#699=DIRECTION('',(1.,0.,0.));
#700=VECTOR('',#699,1.);
#701=CARTESIAN_POINT('',(8.56778460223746,17.596497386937,25.4630368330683));
#702=LINE('',#701,#700);
#703=CARTESIAN_POINT('',(19.5677846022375,17.596497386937,25.4630368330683));
#704=VERTEX_POINT('',#703);
#705=CARTESIAN_POINT('',(20.8688043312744,17.596497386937,25.4630368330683));
#706=VERTEX_POINT('',#705);
#707=EDGE_CURVE('P0_E827',#704,#706,#702,.T.);
#708=ORIENTED_EDGE('',*,*,#707,.F.);
#709=DIRECTION('',(-0.398509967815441,0.917164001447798,0.));
#710=VECTOR('',#709,1.);
#711=CARTESIAN_POINT('',(20.8688043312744,14.6022223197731,25.4630368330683));
#712=LINE('',#711,#710);
#713=CARTESIAN_POINT('',(20.8688043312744,14.6022223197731,25.4630368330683));
#714=VERTEX_POINT('',#713);
#715=EDGE_CURVE('P0_E820',#714,#704,#712,.T.);
#716=ORIENTED_EDGE('',*,*,#715,.F.);
#717=DIRECTION('',(-1.,0.,0.));
#718=VECTOR('',#717,1.);
#719=CARTESIAN_POINT('',(22.0677846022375,14.6022223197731,25.4630368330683));
#720=LINE('',#719,#718);
#721=EDGE_CURVE('P0_E790',#493,#714,#720,.T.);
#722=ORIENTED_EDGE('',*,*,#721,.F.);
#723=ORIENTED_EDGE('',*,*,#494,.T.);
#724=ORIENTED_EDGE('',*,*,#414,.T.);
#725=DIRECTION('',(0.,1.,0.));
#726=VECTOR('',#725,1.);
#727=CARTESIAN_POINT('',(20.8688043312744,21.1022223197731,25.4630368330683));
#728=LINE('',#727,#726);
#729=EDGE_CURVE('P0_E830',#706,#405,#728,.T.);
#730=ORIENTED_EDGE('',*,*,#729,.F.);
#731=EDGE_LOOP('',(#708,#716,#722,#723,#724,#730));
#732=FACE_BOUND('',#731,.T.);
#733=ADVANCED_FACE('P0_F629',(#732),#698,.F.);
#734=CARTESIAN_POINT('',(19.5677846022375,14.6022223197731,19.8683332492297));
#735=DIRECTION('',(0.,0.,1.));
#736=DIRECTION('',(-1.,0.,0.));
#737=AXIS2_PLACEMENT_3D('',#734,#735,#736);
#738=PLANE('',#737);
#739=DIRECTION('',(1.,0.,0.));
#740=VECTOR('',#739,1.);
#741=CARTESIAN_POINT('',(19.5677846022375,14.6022223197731,19.8683332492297));
#742=LINE('',#741,#740);
#743=CARTESIAN_POINT('',(20.8688043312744,14.6022223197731,19.8683332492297));
#744=VERTEX_POINT('',#743);
#745=EDGE_CURVE('P0_E795',#744,#501,#742,.T.);
#746=ORIENTED_EDGE('',*,*,#745,.F.);
#747=DIRECTION('',(-0.398509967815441,0.917164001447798,0.));
#748=VECTOR('',#747,1.);
#749=CARTESIAN_POINT('',(20.662189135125,15.077743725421,19.8683332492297));
#750=LINE('',#749,#748);
#751=CARTESIAN_POINT('',(19.5677846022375,17.596497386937,19.8683332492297));
#752=VERTEX_POINT('',#751);
#753=EDGE_CURVE('P0_E824',#744,#752,#750,.T.);
#754=ORIENTED_EDGE('',*,*,#753,.T.);
#755=DIRECTION('',(1.,0.,0.));
#756=VECTOR('',#755,1.);
#757=CARTESIAN_POINT('',(19.5677846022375,17.596497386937,19.8683332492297));
#758=LINE('',#757,#756);
#759=CARTESIAN_POINT('',(20.8688043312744,17.596497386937,19.8683332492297));
#760=VERTEX_POINT('',#759);
#761=EDGE_CURVE('P0_E717',#752,#760,#758,.T.);
#762=ORIENTED_EDGE('',*,*,#761,.T.);
#763=DIRECTION('',(0.,1.,0.));
#764=VECTOR('',#763,1.);
#765=CARTESIAN_POINT('',(20.8688043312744,14.6022223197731,19.8683332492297));
#766=LINE('',#765,#764);
#767=EDGE_CURVE('P0_E714',#760,#395,#766,.T.);
#768=ORIENTED_EDGE('',*,*,#767,.T.);
#769=ORIENTED_EDGE('',*,*,#398,.T.);
#770=ORIENTED_EDGE('',*,*,#508,.F.);
#771=EDGE_LOOP('',(#746,#754,#762,#768,#769,#770));
#772=FACE_BOUND('',#771,.T.);
#773=ADVANCED_FACE('P0_F625',(#772),#738,.F.);
#774=CARTESIAN_POINT('',(8.56778460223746,14.6022223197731,22.8683332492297));
#775=DIRECTION('',(0.,-1.,0.));
#776=DIRECTION('',(-1.,0.,0.));
#777=AXIS2_PLACEMENT_3D('',#774,#775,#776);
#778=PLANE('',#777);
#779=DIRECTION('',(0.,0.,1.));
#780=VECTOR('',#779,1.);
#781=CARTESIAN_POINT('',(20.8688043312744,14.6022223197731,17.9683332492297));
#782=LINE('',#781,#780);
#783=EDGE_CURVE('P0_E822',#744,#714,#782,.T.);
#784=ORIENTED_EDGE('',*,*,#783,.F.);
#785=ORIENTED_EDGE('',*,*,#745,.T.);
#786=ORIENTED_EDGE('',*,*,#502,.T.);
#787=ORIENTED_EDGE('',*,*,#721,.T.);
#788=EDGE_LOOP('',(#784,#785,#786,#787));
#789=FACE_BOUND('',#788,.T.);
#790=ADVANCED_FACE('P0_F621',(#789),#778,.T.);
#791=CARTESIAN_POINT('',(8.56778460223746,17.596497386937,17.9683332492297));
#792=DIRECTION('',(0.,-1.,0.));
#793=DIRECTION('',(-1.,0.,0.));
#794=AXIS2_PLACEMENT_3D('',#791,#792,#793);
#795=PLANE('',#794);
#796=DIRECTION('',(0.,0.,1.));
#797=VECTOR('',#796,1.);
#798=CARTESIAN_POINT('',(19.5677846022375,17.596497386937,17.9683332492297));
#799=LINE('',#798,#797);
#800=EDGE_CURVE('P0_E834',#752,#704,#799,.T.);
#801=ORIENTED_EDGE('',*,*,#800,.T.);
#802=ORIENTED_EDGE('',*,*,#707,.T.);
#803=DIRECTION('',(0.,0.,1.));
#804=VECTOR('',#803,1.);
#805=CARTESIAN_POINT('',(20.8688043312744,17.596497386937,17.9683332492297));
#806=LINE('',#805,#804);
#807=EDGE_CURVE('P0_E833',#760,#706,#806,.T.);
#808=ORIENTED_EDGE('',*,*,#807,.F.);
#809=ORIENTED_EDGE('',*,*,#761,.F.);
#810=EDGE_LOOP('',(#801,#802,#808,#809));
#811=FACE_BOUND('',#810,.T.);
#812=ADVANCED_FACE('P0_F617',(#811),#795,.F.);
#813=CARTESIAN_POINT('',(20.8688043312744,21.1022223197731,17.9683332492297));
#814=DIRECTION('',(1.,0.,0.));
#815=DIRECTION('',(0.,0.,1.));
#816=AXIS2_PLACEMENT_3D('',#813,#814,#815);
#817=PLANE('',#816);
#818=ORIENTED_EDGE('',*,*,#807,.T.);
#819=ORIENTED_EDGE('',*,*,#729,.T.);
#820=ORIENTED_EDGE('',*,*,#406,.F.);
#821=ORIENTED_EDGE('',*,*,#767,.F.);
#822=EDGE_LOOP('',(#818,#819,#820,#821));
#823=FACE_BOUND('',#822,.T.);
#824=ADVANCED_FACE('P0_F613',(#823),#817,.F.);
#825=CARTESIAN_POINT('',(20.8688043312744,14.6022223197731,17.9683332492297));
#826=DIRECTION('',(0.917164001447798,0.398509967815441,0.));
#827=DIRECTION('',(0.398509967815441,-0.917164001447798,0.));
#828=AXIS2_PLACEMENT_3D('',#825,#826,#827);
#829=PLANE('',#828);
#830=ORIENTED_EDGE('',*,*,#783,.T.);
#831=ORIENTED_EDGE('',*,*,#715,.T.);
#832=ORIENTED_EDGE('',*,*,#800,.F.);
#833=ORIENTED_EDGE('',*,*,#753,.F.);
#834=EDGE_LOOP('',(#830,#831,#832,#833));
#835=FACE_BOUND('',#834,.T.);
#836=ADVANCED_FACE('P0_F609',(#835),#829,.F.);
#837=CARTESIAN_POINT('',(18.7677846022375,18.1022223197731,25.6183332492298));
#838=DIRECTION('',(0.,0.,1.));
#839=DIRECTION('',(-1.,0.,0.));
#840=AXIS2_PLACEMENT_3D('',#837,#838,#839);
#841=PLANE('',#840);
#842=ORIENTED_EDGE('',*,*,#670,.T.);
#843=DIRECTION('',(0.,1.,0.));
#844=VECTOR('',#843,1.);
#845=CARTESIAN_POINT('',(18.7677846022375,18.1022223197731,25.6183332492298));
#846=LINE('',#845,#844);
#847=EDGE_CURVE('P0_E728',#669,#211,#846,.T.);
#848=ORIENTED_EDGE('',*,*,#847,.T.);
#849=ORIENTED_EDGE('',*,*,#214,.T.);
#850=ORIENTED_EDGE('',*,*,#594,.F.);
#851=EDGE_LOOP('',(#842,#848,#849,#850));
#852=FACE_BOUND('',#851,.T.);
#853=ADVANCED_FACE('P0_F602',(#852),#841,.F.);
#854=CARTESIAN_POINT('',(18.7677846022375,18.1022223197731,20.1183332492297));
#855=DIRECTION('',(-1.,0.,0.));
#856=DIRECTION('',(0.,0.,-1.));
#857=AXIS2_PLACEMENT_3D('',#854,#855,#856);
#858=PLANE('',#857);
#859=ORIENTED_EDGE('',*,*,#689,.T.);
#860=DIRECTION('',(0.,1.,0.));
#861=VECTOR('',#860,1.);
#862=CARTESIAN_POINT('',(18.7677846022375,18.1022223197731,20.1183332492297));
#863=LINE('',#862,#861);
#864=EDGE_CURVE('P0_E726',#682,#221,#863,.T.);
#865=ORIENTED_EDGE('',*,*,#864,.T.);
#866=ORIENTED_EDGE('',*,*,#222,.T.);
#867=ORIENTED_EDGE('',*,*,#847,.F.);
#868=EDGE_LOOP('',(#859,#865,#866,#867));
#869=FACE_BOUND('',#868,.T.);
#870=ADVANCED_FACE('P0_F599',(#869),#858,.F.);
#871=CARTESIAN_POINT('',(20.5677846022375,18.1022223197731,20.1183332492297));
#872=DIRECTION('',(0.,0.,-1.));
#873=DIRECTION('',(1.,0.,0.));
#874=AXIS2_PLACEMENT_3D('',#871,#872,#873);
#875=PLANE('',#874);
#876=ORIENTED_EDGE('',*,*,#683,.T.);
#877=ORIENTED_EDGE('',*,*,#603,.T.);
#878=ORIENTED_EDGE('',*,*,#230,.T.);
#879=ORIENTED_EDGE('',*,*,#864,.F.);
#880=EDGE_LOOP('',(#876,#877,#878,#879));
#881=FACE_BOUND('',#880,.T.);
#882=ADVANCED_FACE('P0_F597',(#881),#875,.F.);
#883=CARTESIAN_POINT('',(9.27511899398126,20.9022223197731,21.9033893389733));
#884=DIRECTION('',(-0.842183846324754,0.,0.539190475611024));
#885=DIRECTION('',(-0.539190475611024,0.,-0.842183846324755));
#886=AXIS2_PLACEMENT_3D('',#883,#884,#885);
#887=PLANE('',#886);
#888=ORIENTED_EDGE('',*,*,#90,.F.);
#889=DIRECTION('',(0.,1.,0.));
#890=VECTOR('',#889,1.);
#891=CARTESIAN_POINT('',(9.27511899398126,20.9022223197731,21.9033893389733));
#892=LINE('',#891,#890);
#893=CARTESIAN_POINT('',(9.27511899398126,20.9022223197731,21.9033893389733));
#894=VERTEX_POINT('',#893);
#895=EDGE_CURVE('P0_E880',#894,#81,#892,.T.);
#896=ORIENTED_EDGE('',*,*,#895,.F.);
#897=DIRECTION('',(0.539190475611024,0.,0.842183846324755));
#898=VECTOR('',#897,1.);
#899=CARTESIAN_POINT('',(9.27511899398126,20.9022223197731,21.9033893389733));
#900=LINE('',#899,#898);
#901=CARTESIAN_POINT('',(10.3730757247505,20.9022223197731,23.6183332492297));
#902=VERTEX_POINT('',#901);
#903=EDGE_CURVE('P0_E887',#894,#902,#900,.T.);
#904=ORIENTED_EDGE('',*,*,#903,.T.);
#905=DIRECTION('',(0.,1.,0.));
#906=VECTOR('',#905,1.);
#907=CARTESIAN_POINT('',(10.3730757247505,20.9022223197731,23.6183332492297));
#908=LINE('',#907,#906);
#909=EDGE_CURVE('P0_E856',#902,#89,#908,.T.);
#910=ORIENTED_EDGE('',*,*,#909,.T.);
#911=EDGE_LOOP('',(#888,#896,#904,#910));
#912=FACE_BOUND('',#911,.T.);
#913=ADVANCED_FACE('P0_F593',(#912),#887,.T.);
#914=CARTESIAN_POINT('',(10.3730757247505,20.9022223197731,23.6183332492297));
#915=DIRECTION('',(0.,0.,-1.));
#916=DIRECTION('',(1.,0.,0.));
#917=AXIS2_PLACEMENT_3D('',#914,#915,#916);
#918=PLANE('',#917);
#919=ORIENTED_EDGE('',*,*,#98,.F.);
#920=ORIENTED_EDGE('',*,*,#909,.F.);
#921=DIRECTION('',(-1.,0.,0.));
#922=VECTOR('',#921,1.);
#923=CARTESIAN_POINT('',(10.3730757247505,20.9022223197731,23.6183332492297));
#924=LINE('',#923,#922);
#925=CARTESIAN_POINT('',(10.0105957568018,20.9022223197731,23.6183332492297));
#926=VERTEX_POINT('',#925);
#927=EDGE_CURVE('P0_E940',#902,#926,#924,.T.);
#928=ORIENTED_EDGE('',*,*,#927,.T.);
#929=DIRECTION('',(0.,1.,0.));
#930=VECTOR('',#929,1.);
#931=CARTESIAN_POINT('',(10.0105957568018,20.9022223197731,23.6183332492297));
#932=LINE('',#931,#930);
#933=EDGE_CURVE('P0_E860',#926,#97,#932,.T.);
#934=ORIENTED_EDGE('',*,*,#933,.T.);
#935=EDGE_LOOP('',(#919,#920,#928,#934));
#936=FACE_BOUND('',#935,.T.);
#937=ADVANCED_FACE('P0_F589',(#936),#918,.T.);
#938=CARTESIAN_POINT('',(10.0105957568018,20.9022223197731,23.6183332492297));
#939=DIRECTION('',(0.842248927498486,0.,-0.539088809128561));
#940=DIRECTION('',(0.539088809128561,0.,0.842248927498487));
#941=AXIS2_PLACEMENT_3D('',#938,#939,#940);
#942=PLANE('',#941);
#943=ORIENTED_EDGE('',*,*,#106,.F.);
#944=ORIENTED_EDGE('',*,*,#933,.F.);
#945=DIRECTION('',(-0.539088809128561,0.,-0.842248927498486));
#946=VECTOR('',#945,1.);
#947=CARTESIAN_POINT('',(10.0105957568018,20.9022223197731,23.6183332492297));
#948=LINE('',#947,#946);
#949=CARTESIAN_POINT('',(9.09422957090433,20.9022223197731,22.1866425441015));
#950=VERTEX_POINT('',#949);
#951=EDGE_CURVE('P0_E938',#926,#950,#948,.T.);
#952=ORIENTED_EDGE('',*,*,#951,.T.);
#953=DIRECTION('',(0.,1.,0.));
#954=VECTOR('',#953,1.);
#955=CARTESIAN_POINT('',(9.09422957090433,20.9022223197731,22.1866425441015));
#956=LINE('',#955,#954);
#957=EDGE_CURVE('P0_E862',#950,#105,#956,.T.);
#958=ORIENTED_EDGE('',*,*,#957,.T.);
#959=EDGE_LOOP('',(#943,#944,#952,#958));
#960=FACE_BOUND('',#959,.T.);
#961=ADVANCED_FACE('P0_F585',(#960),#942,.T.);
#962=CARTESIAN_POINT('',(9.09422957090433,20.9022223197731,22.1866425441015));
#963=DIRECTION('',(-0.842248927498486,0.,-0.539088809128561));
#964=DIRECTION('',(0.539088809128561,0.,-0.842248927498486));
#965=AXIS2_PLACEMENT_3D('',#962,#963,#964);
#966=PLANE('',#965);
#967=ORIENTED_EDGE('',*,*,#114,.F.);
#968=ORIENTED_EDGE('',*,*,#957,.F.);
#969=DIRECTION('',(-0.539088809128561,0.,0.842248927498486));
#970=VECTOR('',#969,1.);
#971=CARTESIAN_POINT('',(9.09422957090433,20.9022223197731,22.1866425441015));
#972=LINE('',#971,#970);
#973=CARTESIAN_POINT('',(8.1778633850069,20.9022223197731,23.6183332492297));
#974=VERTEX_POINT('',#973);
#975=EDGE_CURVE('P0_E936',#950,#974,#972,.T.);
#976=ORIENTED_EDGE('',*,*,#975,.T.);
#977=DIRECTION('',(0.,1.,0.));
#978=VECTOR('',#977,1.);
#979=CARTESIAN_POINT('',(8.1778633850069,20.9022223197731,23.6183332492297));
#980=LINE('',#979,#978);
#981=EDGE_CURVE('P0_E864',#974,#113,#980,.T.);
#982=ORIENTED_EDGE('',*,*,#981,.T.);
#983=EDGE_LOOP('',(#967,#968,#976,#982));
#984=FACE_BOUND('',#983,.T.);
#985=ADVANCED_FACE('P0_F581',(#984),#966,.T.);
#986=CARTESIAN_POINT('',(8.1778633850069,20.9022223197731,23.6183332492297));
#987=DIRECTION('',(0.,0.,-1.));
#988=DIRECTION('',(1.,0.,0.));
#989=AXIS2_PLACEMENT_3D('',#986,#987,#988);
#990=PLANE('',#989);
#991=ORIENTED_EDGE('',*,*,#122,.F.);
#992=ORIENTED_EDGE('',*,*,#981,.F.);
#993=DIRECTION('',(-1.,0.,0.));
#994=VECTOR('',#993,1.);
#995=CARTESIAN_POINT('',(8.1778633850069,20.9022223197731,23.6183332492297));
#996=LINE('',#995,#994);
#997=CARTESIAN_POINT('',(7.81538341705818,20.9022223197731,23.6183332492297));
#998=VERTEX_POINT('',#997);
#999=EDGE_CURVE('P0_E934',#974,#998,#996,.T.);
#1000=ORIENTED_EDGE('',*,*,#999,.T.);
#1001=DIRECTION('',(0.,1.,0.));
#1002=VECTOR('',#1001,1.);
#1003=CARTESIAN_POINT('',(7.81538341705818,20.9022223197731,23.6183332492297));
#1004=LINE('',#1003,#1002);
#1005=EDGE_CURVE('P0_E866',#998,#121,#1004,.T.);
#1006=ORIENTED_EDGE('',*,*,#1005,.T.);
#1007=EDGE_LOOP('',(#991,#992,#1000,#1006));
#1008=FACE_BOUND('',#1007,.T.);
#1009=ADVANCED_FACE('P0_F577',(#1008),#990,.T.);
#1010=CARTESIAN_POINT('',(7.81538341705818,20.9022223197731,23.6183332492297));
#1011=DIRECTION('',(0.842340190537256,0.,0.538946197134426));
#1012=DIRECTION('',(-0.538946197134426,0.,0.842340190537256));
#1013=AXIS2_PLACEMENT_3D('',#1010,#1011,#1012);
#1014=PLANE('',#1013);
#1015=ORIENTED_EDGE('',*,*,#130,.F.);
#1016=ORIENTED_EDGE('',*,*,#1005,.F.);
#1017=DIRECTION('',(0.538946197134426,0.,-0.842340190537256));
#1018=VECTOR('',#1017,1.);
#1019=CARTESIAN_POINT('',(7.81538341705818,20.9022223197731,23.6183332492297));
#1020=LINE('',#1019,#1018);
#1021=CARTESIAN_POINT('',(8.91263902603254,20.9022223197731,21.9033893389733));
#1022=VERTEX_POINT('',#1021);
#1023=EDGE_CURVE('P0_E932',#998,#1022,#1020,.T.);
#1024=ORIENTED_EDGE('',*,*,#1023,.T.);
#1025=DIRECTION('',(0.,1.,0.));
#1026=VECTOR('',#1025,1.);
#1027=CARTESIAN_POINT('',(8.91263902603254,20.9022223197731,21.9033893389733));
#1028=LINE('',#1027,#1026);
#1029=EDGE_CURVE('P0_E868',#1022,#129,#1028,.T.);
#1030=ORIENTED_EDGE('',*,*,#1029,.T.);
#1031=EDGE_LOOP('',(#1015,#1016,#1024,#1030));
#1032=FACE_BOUND('',#1031,.T.);
#1033=ADVANCED_FACE('P0_F573',(#1032),#1014,.T.);
#1034=CARTESIAN_POINT('',(8.91263902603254,20.9022223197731,21.9033893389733));
#1035=DIRECTION('',(0.842337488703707,0.,-0.538950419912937));
#1036=DIRECTION('',(0.538950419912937,0.,0.842337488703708));
#1037=AXIS2_PLACEMENT_3D('',#1034,#1035,#1036);
#1038=PLANE('',#1037);
#1039=ORIENTED_EDGE('',*,*,#138,.F.);
#1040=ORIENTED_EDGE('',*,*,#1029,.F.);
#1041=DIRECTION('',(-0.538950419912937,0.,-0.842337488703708));
#1042=VECTOR('',#1041,1.);
#1043=CARTESIAN_POINT('',(8.91263902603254,20.9022223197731,21.9033893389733));
#1044=LINE('',#1043,#1042);
#1045=CARTESIAN_POINT('',(7.77051162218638,20.9022223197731,20.1183332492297));
#1046=VERTEX_POINT('',#1045);
#1047=EDGE_CURVE('P0_E930',#1022,#1046,#1044,.T.);
#1048=ORIENTED_EDGE('',*,*,#1047,.T.);
#1049=DIRECTION('',(0.,1.,0.));
#1050=VECTOR('',#1049,1.);
#1051=CARTESIAN_POINT('',(7.77051162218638,20.9022223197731,20.1183332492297));
#1052=LINE('',#1051,#1050);
#1053=EDGE_CURVE('P0_E870',#1046,#137,#1052,.T.);
#1054=ORIENTED_EDGE('',*,*,#1053,.T.);
#1055=EDGE_LOOP('',(#1039,#1040,#1048,#1054));
#1056=FACE_BOUND('',#1055,.T.);
#1057=ADVANCED_FACE('P0_F569',(#1056),#1038,.T.);
#1058=CARTESIAN_POINT('',(7.77051162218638,20.9022223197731,20.1183332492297));
#1059=DIRECTION('',(0.,0.,1.));
#1060=DIRECTION('',(-1.,0.,0.));
#1061=AXIS2_PLACEMENT_3D('',#1058,#1059,#1060);
#1062=PLANE('',#1061);
#1063=ORIENTED_EDGE('',*,*,#146,.F.);
#1064=ORIENTED_EDGE('',*,*,#1053,.F.);
#1065=DIRECTION('',(1.,0.,0.));
#1066=VECTOR('',#1065,1.);
#1067=CARTESIAN_POINT('',(7.77051162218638,20.9022223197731,20.1183332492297));
#1068=LINE('',#1067,#1066);
#1069=CARTESIAN_POINT('',(8.1329915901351,20.9022223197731,20.1183332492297));
#1070=VERTEX_POINT('',#1069);
#1071=EDGE_CURVE('P0_E928',#1046,#1070,#1068,.T.);
#1072=ORIENTED_EDGE('',*,*,#1071,.T.);
#1073=DIRECTION('',(0.,1.,0.));
#1074=VECTOR('',#1073,1.);
#1075=CARTESIAN_POINT('',(8.1329915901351,20.9022223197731,20.1183332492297));
#1076=LINE('',#1075,#1074);
#1077=EDGE_CURVE('P0_E872',#1070,#145,#1076,.T.);
#1078=ORIENTED_EDGE('',*,*,#1077,.T.);
#1079=EDGE_LOOP('',(#1063,#1064,#1072,#1078));
#1080=FACE_BOUND('',#1079,.T.);
#1081=ADVANCED_FACE('P0_F565',(#1080),#1062,.T.);
#1082=CARTESIAN_POINT('',(8.1329915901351,20.9022223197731,20.1183332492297));
#1083=DIRECTION('',(-0.842249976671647,0.,0.539087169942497));
#1084=DIRECTION('',(-0.539087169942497,0.,-0.842249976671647));
#1085=AXIS2_PLACEMENT_3D('',#1082,#1083,#1084);
#1086=PLANE('',#1085);
#1087=ORIENTED_EDGE('',*,*,#154,.F.);
#1088=ORIENTED_EDGE('',*,*,#1077,.F.);
#1089=DIRECTION('',(0.539087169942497,0.,0.842249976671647));
#1090=VECTOR('',#1089,1.);
#1091=CARTESIAN_POINT('',(8.1329915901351,20.9022223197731,20.1183332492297));
#1092=LINE('',#1091,#1090);
#1093=CARTESIAN_POINT('',(9.09422957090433,20.9022223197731,21.6201361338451));
#1094=VERTEX_POINT('',#1093);
#1095=EDGE_CURVE('P0_E926',#1070,#1094,#1092,.T.);
#1096=ORIENTED_EDGE('',*,*,#1095,.T.);
#1097=DIRECTION('',(0.,1.,0.));
#1098=VECTOR('',#1097,1.);
#1099=CARTESIAN_POINT('',(9.09422957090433,20.9022223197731,21.6201361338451));
#1100=LINE('',#1099,#1098);
#1101=EDGE_CURVE('P0_E874',#1094,#153,#1100,.T.);
#1102=ORIENTED_EDGE('',*,*,#1101,.T.);
#1103=EDGE_LOOP('',(#1087,#1088,#1096,#1102));
#1104=FACE_BOUND('',#1103,.T.);
#1105=ADVANCED_FACE('P0_F561',(#1104),#1086,.T.);
#1106=CARTESIAN_POINT('',(9.09422957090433,20.9022223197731,21.6201361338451));
#1107=DIRECTION('',(0.842249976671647,0.,0.539087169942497));
#1108=DIRECTION('',(-0.539087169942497,0.,0.842249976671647));
#1109=AXIS2_PLACEMENT_3D('',#1106,#1107,#1108);
#1110=PLANE('',#1109);
#1111=ORIENTED_EDGE('',*,*,#162,.F.);
#1112=ORIENTED_EDGE('',*,*,#1101,.F.);
#1113=DIRECTION('',(0.539087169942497,0.,-0.842249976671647));
#1114=VECTOR('',#1113,1.);
#1115=CARTESIAN_POINT('',(9.09422957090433,20.9022223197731,21.6201361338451));
#1116=LINE('',#1115,#1114);
#1117=CARTESIAN_POINT('',(10.0554675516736,20.9022223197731,20.1183332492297));
#1118=VERTEX_POINT('',#1117);
#1119=EDGE_CURVE('P0_E924',#1094,#1118,#1116,.T.);
#1120=ORIENTED_EDGE('',*,*,#1119,.T.);
#1121=DIRECTION('',(0.,1.,0.));
#1122=VECTOR('',#1121,1.);
#1123=CARTESIAN_POINT('',(10.0554675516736,20.9022223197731,20.1183332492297));
#1124=LINE('',#1123,#1122);
#1125=EDGE_CURVE('P0_E876',#1118,#161,#1124,.T.);
#1126=ORIENTED_EDGE('',*,*,#1125,.T.);
#1127=EDGE_LOOP('',(#1111,#1112,#1120,#1126));
#1128=FACE_BOUND('',#1127,.T.);
#1129=ADVANCED_FACE('P0_F557',(#1128),#1110,.T.);
#1130=CARTESIAN_POINT('',(10.0554675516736,20.9022223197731,20.1183332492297));
#1131=DIRECTION('',(0.,0.,1.));
#1132=DIRECTION('',(-1.,0.,0.));
#1133=AXIS2_PLACEMENT_3D('',#1130,#1131,#1132);
#1134=PLANE('',#1133);
#1135=ORIENTED_EDGE('',*,*,#168,.F.);
#1136=ORIENTED_EDGE('',*,*,#1125,.F.);
#1137=DIRECTION('',(1.,0.,0.));
#1138=VECTOR('',#1137,1.);
#1139=CARTESIAN_POINT('',(10.0554675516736,20.9022223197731,20.1183332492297));
#1140=LINE('',#1139,#1138);
#1141=CARTESIAN_POINT('',(10.4179475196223,20.9022223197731,20.1183332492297));
#1142=VERTEX_POINT('',#1141);
#1143=EDGE_CURVE('P0_E922',#1118,#1142,#1140,.T.);
#1144=ORIENTED_EDGE('',*,*,#1143,.T.);
#1145=DIRECTION('',(0.,1.,0.));
#1146=VECTOR('',#1145,1.);
#1147=CARTESIAN_POINT('',(10.4179475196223,20.9022223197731,20.1183332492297));
#1148=LINE('',#1147,#1146);
#1149=EDGE_CURVE('P0_E878',#1142,#79,#1148,.T.);
#1150=ORIENTED_EDGE('',*,*,#1149,.T.);
#1151=EDGE_LOOP('',(#1135,#1136,#1144,#1150));
#1152=FACE_BOUND('',#1151,.T.);
#1153=ADVANCED_FACE('P0_F553',(#1152),#1134,.T.);
#1154=CARTESIAN_POINT('',(10.4179475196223,20.9022223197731,20.1183332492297));
#1155=DIRECTION('',(-0.842187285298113,0.,-0.539185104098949));
#1156=DIRECTION('',(0.539185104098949,0.,-0.842187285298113));
#1157=AXIS2_PLACEMENT_3D('',#1154,#1155,#1156);
#1158=PLANE('',#1157);
#1159=ORIENTED_EDGE('',*,*,#82,.F.);
#1160=ORIENTED_EDGE('',*,*,#1149,.F.);
#1161=DIRECTION('',(-0.539185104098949,0.,0.842187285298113));
#1162=VECTOR('',#1161,1.);
#1163=CARTESIAN_POINT('',(10.4179475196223,20.9022223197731,20.1183332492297));
#1164=LINE('',#1163,#1162);
#1165=EDGE_CURVE('P0_E883',#1142,#894,#1164,.T.);
#1166=ORIENTED_EDGE('',*,*,#1165,.T.);
#1167=ORIENTED_EDGE('',*,*,#895,.T.);
#1168=EDGE_LOOP('',(#1159,#1160,#1166,#1167));
#1169=FACE_BOUND('',#1168,.T.);
#1170=ADVANCED_FACE('P0_F549',(#1169),#1158,.T.);
#1171=CARTESIAN_POINT('',(8.56778460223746,20.9022223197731,22.8683332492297));
#1172=DIRECTION('',(0.,-1.,0.));
#1173=DIRECTION('',(-1.,0.,0.));
#1174=AXIS2_PLACEMENT_3D('',#1171,#1172,#1173);
#1175=PLANE('',#1174);
#1176=ORIENTED_EDGE('',*,*,#903,.F.);
#1177=ORIENTED_EDGE('',*,*,#1165,.F.);
#1178=ORIENTED_EDGE('',*,*,#1143,.F.);
#1179=ORIENTED_EDGE('',*,*,#1119,.F.);
#1180=ORIENTED_EDGE('',*,*,#1095,.F.);
#1181=ORIENTED_EDGE('',*,*,#1071,.F.);
#1182=ORIENTED_EDGE('',*,*,#1047,.F.);
#1183=ORIENTED_EDGE('',*,*,#1023,.F.);
#1184=ORIENTED_EDGE('',*,*,#999,.F.);
#1185=ORIENTED_EDGE('',*,*,#975,.F.);
#1186=ORIENTED_EDGE('',*,*,#951,.F.);
#1187=ORIENTED_EDGE('',*,*,#927,.F.);
#1188=EDGE_LOOP('',(#1176,#1177,#1178,#1179,#1180,#1181,#1182,#1183,#1184,#1185,#1186,#1187));
#1189=FACE_BOUND('',#1188,.T.);
#1190=ADVANCED_FACE('P0_F545',(#1189),#1175,.F.);
#1191=CARTESIAN_POINT('',(12.3698705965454,20.9022223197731,20.1183332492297));
#1192=DIRECTION('',(-1.,0.,0.));
#1193=DIRECTION('',(0.,0.,-1.));
#1194=AXIS2_PLACEMENT_3D('',#1191,#1192,#1193);
#1195=PLANE('',#1194);
#1196=ORIENTED_EDGE('',*,*,#40,.F.);
#1197=DIRECTION('',(0.,1.,0.));
#1198=VECTOR('',#1197,1.);
#1199=CARTESIAN_POINT('',(12.3698705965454,20.9022223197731,20.1183332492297));
#1200=LINE('',#1199,#1198);
#1201=CARTESIAN_POINT('',(12.3698705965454,20.9022223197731,20.1183332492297));
#1202=VERTEX_POINT('',#1201);
#1203=EDGE_CURVE('P0_E956',#1202,#31,#1200,.T.);
#1204=ORIENTED_EDGE('',*,*,#1203,.F.);
#1205=DIRECTION('',(0.,0.,1.));
#1206=VECTOR('',#1205,1.);
#1207=CARTESIAN_POINT('',(12.3698705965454,20.9022223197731,20.1183332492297));
#1208=LINE('',#1207,#1206);
#1209=CARTESIAN_POINT('',(12.3698705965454,20.9022223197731,23.6183332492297));
#1210=VERTEX_POINT('',#1209);
#1211=EDGE_CURVE('P0_E963',#1202,#1210,#1208,.T.);
#1212=ORIENTED_EDGE('',*,*,#1211,.T.);
#1213=DIRECTION('',(0.,1.,0.));
#1214=VECTOR('',#1213,1.);
#1215=CARTESIAN_POINT('',(12.3698705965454,20.9022223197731,23.6183332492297));
#1216=LINE('',#1215,#1214);
#1217=EDGE_CURVE('P0_E944',#1210,#39,#1216,.T.);
#1218=ORIENTED_EDGE('',*,*,#1217,.T.);
#1219=EDGE_LOOP('',(#1196,#1204,#1212,#1218));
#1220=FACE_BOUND('',#1219,.T.);
#1221=ADVANCED_FACE('P0_F541',(#1220),#1195,.T.);
#1222=CARTESIAN_POINT('',(12.3698705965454,20.9022223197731,23.6183332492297));
#1223=DIRECTION('',(0.,0.,-1.));
#1224=DIRECTION('',(1.,0.,0.));
#1225=AXIS2_PLACEMENT_3D('',#1222,#1223,#1224);
#1226=PLANE('',#1225);
#1227=ORIENTED_EDGE('',*,*,#48,.F.);
#1228=ORIENTED_EDGE('',*,*,#1217,.F.);
#1229=DIRECTION('',(-1.,0.,0.));
#1230=VECTOR('',#1229,1.);
#1231=CARTESIAN_POINT('',(12.3698705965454,20.9022223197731,23.6183332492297));
#1232=LINE('',#1231,#1230);
#1233=CARTESIAN_POINT('',(12.0557680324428,20.9022223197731,23.6183332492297));
#1234=VERTEX_POINT('',#1233);
#1235=EDGE_CURVE('P0_E985',#1210,#1234,#1232,.T.);
#1236=ORIENTED_EDGE('',*,*,#1235,.T.);
#1237=DIRECTION('',(0.,1.,0.));
#1238=VECTOR('',#1237,1.);
#1239=CARTESIAN_POINT('',(12.0557680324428,20.9022223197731,23.6183332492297));
#1240=LINE('',#1239,#1238);
#1241=EDGE_CURVE('P0_E948',#1234,#47,#1240,.T.);
#1242=ORIENTED_EDGE('',*,*,#1241,.T.);
#1243=EDGE_LOOP('',(#1227,#1228,#1236,#1242));
#1244=FACE_BOUND('',#1243,.T.);
#1245=ADVANCED_FACE('P0_F537',(#1244),#1226,.T.);
#1246=CARTESIAN_POINT('',(12.0557680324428,20.9022223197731,23.6183332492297));
#1247=DIRECTION('',(1.,0.,0.));
#1248=DIRECTION('',(0.,0.,1.));
#1249=AXIS2_PLACEMENT_3D('',#1246,#1247,#1248);
#1250=PLANE('',#1249);
#1251=ORIENTED_EDGE('',*,*,#56,.F.);
#1252=ORIENTED_EDGE('',*,*,#1241,.F.);
#1253=DIRECTION('',(0.,0.,-1.));
#1254=VECTOR('',#1253,1.);
#1255=CARTESIAN_POINT('',(12.0557680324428,20.9022223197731,23.6183332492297));
#1256=LINE('',#1255,#1254);
#1257=CARTESIAN_POINT('',(12.0557680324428,20.9022223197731,20.4773076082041));
#1258=VERTEX_POINT('',#1257);
#1259=EDGE_CURVE('P0_E983',#1234,#1258,#1256,.T.);
#1260=ORIENTED_EDGE('',*,*,#1259,.T.);
#1261=DIRECTION('',(0.,1.,0.));
#1262=VECTOR('',#1261,1.);
#1263=CARTESIAN_POINT('',(12.0557680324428,20.9022223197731,20.4773076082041));
#1264=LINE('',#1263,#1262);
#1265=EDGE_CURVE('P0_E950',#1258,#55,#1264,.T.);
#1266=ORIENTED_EDGE('',*,*,#1265,.T.);
#1267=EDGE_LOOP('',(#1251,#1252,#1260,#1266));
#1268=FACE_BOUND('',#1267,.T.);
#1269=ADVANCED_FACE('P0_F533',(#1268),#1250,.T.);
#1270=CARTESIAN_POINT('',(12.0557680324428,20.9022223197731,20.4773076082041));
#1271=DIRECTION('',(0.,0.,-1.));
#1272=DIRECTION('',(1.,0.,0.));
#1273=AXIS2_PLACEMENT_3D('',#1270,#1271,#1272);
#1274=PLANE('',#1273);
#1275=ORIENTED_EDGE('',*,*,#64,.F.);
#1276=ORIENTED_EDGE('',*,*,#1265,.F.);
#1277=DIRECTION('',(-1.,0.,0.));
#1278=VECTOR('',#1277,1.);
#1279=CARTESIAN_POINT('',(12.0557680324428,20.9022223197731,20.4773076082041));
#1280=LINE('',#1279,#1278);
#1281=CARTESIAN_POINT('',(10.709614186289,20.9022223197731,20.4773076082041));
#1282=VERTEX_POINT('',#1281);
#1283=EDGE_CURVE('P0_E981',#1258,#1282,#1280,.T.);
#1284=ORIENTED_EDGE('',*,*,#1283,.T.);
#1285=DIRECTION('',(0.,1.,0.));
#1286=VECTOR('',#1285,1.);
#1287=CARTESIAN_POINT('',(10.709614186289,20.9022223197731,20.4773076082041));
#1288=LINE('',#1287,#1286);
#1289=EDGE_CURVE('P0_E952',#1282,#63,#1288,.T.);
#1290=ORIENTED_EDGE('',*,*,#1289,.T.);
#1291=EDGE_LOOP('',(#1275,#1276,#1284,#1290));
#1292=FACE_BOUND('',#1291,.T.);
#1293=ADVANCED_FACE('P0_F529',(#1292),#1274,.T.);
#1294=CARTESIAN_POINT('',(10.709614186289,20.9022223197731,20.4773076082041));
#1295=DIRECTION('',(1.,0.,0.));
#1296=DIRECTION('',(0.,0.,1.));
#1297=AXIS2_PLACEMENT_3D('',#1294,#1295,#1296);
#1298=PLANE('',#1297);
#1299=ORIENTED_EDGE('',*,*,#70,.F.);
#1300=ORIENTED_EDGE('',*,*,#1289,.F.);
#1301=DIRECTION('',(0.,0.,-1.));
#1302=VECTOR('',#1301,1.);
#1303=CARTESIAN_POINT('',(10.709614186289,20.9022223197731,20.4773076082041));
#1304=LINE('',#1303,#1302);
#1305=CARTESIAN_POINT('',(10.709614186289,20.9022223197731,20.1183332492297));
#1306=VERTEX_POINT('',#1305);
#1307=EDGE_CURVE('P0_E979',#1282,#1306,#1304,.T.);
#1308=ORIENTED_EDGE('',*,*,#1307,.T.);
#1309=DIRECTION('',(0.,1.,0.));
#1310=VECTOR('',#1309,1.);
#1311=CARTESIAN_POINT('',(10.709614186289,20.9022223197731,20.1183332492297));
#1312=LINE('',#1311,#1310);
#1313=EDGE_CURVE('P0_E954',#1306,#29,#1312,.T.);
#1314=ORIENTED_EDGE('',*,*,#1313,.T.);
#1315=EDGE_LOOP('',(#1299,#1300,#1308,#1314));
#1316=FACE_BOUND('',#1315,.T.);
#1317=ADVANCED_FACE('P0_F525',(#1316),#1298,.T.);
#1318=CARTESIAN_POINT('',(10.709614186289,20.9022223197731,20.1183332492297));
#1319=DIRECTION('',(0.,0.,1.));
#1320=DIRECTION('',(-1.,0.,0.));
#1321=AXIS2_PLACEMENT_3D('',#1318,#1319,#1320);
#1322=PLANE('',#1321);
#1323=ORIENTED_EDGE('',*,*,#32,.F.);
#1324=ORIENTED_EDGE('',*,*,#1313,.F.);
#1325=DIRECTION('',(1.,0.,0.));
#1326=VECTOR('',#1325,1.);
#1327=CARTESIAN_POINT('',(10.709614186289,20.9022223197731,20.1183332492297));
#1328=LINE('',#1327,#1326);
#1329=EDGE_CURVE('P0_E959',#1306,#1202,#1328,.T.);
#1330=ORIENTED_EDGE('',*,*,#1329,.T.);
#1331=ORIENTED_EDGE('',*,*,#1203,.T.);
#1332=EDGE_LOOP('',(#1323,#1324,#1330,#1331));
#1333=FACE_BOUND('',#1332,.T.);
#1334=ADVANCED_FACE('P0_F521',(#1333),#1322,.T.);
#1335=CARTESIAN_POINT('',(8.56778460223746,20.9022223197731,22.8683332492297));
#1336=DIRECTION('',(0.,-1.,0.));
#1337=DIRECTION('',(-1.,0.,0.));
#1338=AXIS2_PLACEMENT_3D('',#1335,#1336,#1337);
#1339=PLANE('',#1338);
#1340=ORIENTED_EDGE('',*,*,#1211,.F.);
#1341=ORIENTED_EDGE('',*,*,#1329,.F.);
#1342=ORIENTED_EDGE('',*,*,#1307,.F.);
#1343=ORIENTED_EDGE('',*,*,#1283,.F.);
#1344=ORIENTED_EDGE('',*,*,#1259,.F.);
#1345=ORIENTED_EDGE('',*,*,#1235,.F.);
#1346=EDGE_LOOP('',(#1340,#1341,#1342,#1343,#1344,#1345));
#1347=FACE_BOUND('',#1346,.T.);
#1348=ADVANCED_FACE('P0_F518',(#1347),#1339,.F.);
#1349=CARTESIAN_POINT('',(15.1519218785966,20.9022223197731,20.1183332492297));
#1350=DIRECTION('',(-1.,0.,0.));
#1351=DIRECTION('',(0.,0.,-1.));
#1352=AXIS2_PLACEMENT_3D('',#1349,#1350,#1351);
#1353=PLANE('',#1352);
#1354=ORIENTED_EDGE('',*,*,#256,.F.);
#1355=DIRECTION('',(0.,1.,0.));
#1356=VECTOR('',#1355,1.);
#1357=CARTESIAN_POINT('',(15.1519218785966,20.9022223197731,20.1183332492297));
#1358=LINE('',#1357,#1356);
#1359=CARTESIAN_POINT('',(15.1519218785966,20.9022223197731,20.1183332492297));
#1360=VERTEX_POINT('',#1359);
#1361=EDGE_CURVE('P0_E1000',#1360,#247,#1358,.T.);
#1362=ORIENTED_EDGE('',*,*,#1361,.F.);
#1363=DIRECTION('',(0.,0.,1.));
#1364=VECTOR('',#1363,1.);
#1365=CARTESIAN_POINT('',(15.1519218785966,20.9022223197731,20.1183332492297));
#1366=LINE('',#1365,#1364);
#1367=CARTESIAN_POINT('',(15.1519218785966,20.9022223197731,23.6183332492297));
#1368=VERTEX_POINT('',#1367);
#1369=EDGE_CURVE('P0_E484',#1360,#1368,#1366,.T.);
#1370=ORIENTED_EDGE('',*,*,#1369,.T.);
#1371=DIRECTION('',(0.,1.,0.));
#1372=VECTOR('',#1371,1.);
#1373=CARTESIAN_POINT('',(15.1519218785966,20.9022223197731,23.6183332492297));
#1374=LINE('',#1373,#1372);
#1375=EDGE_CURVE('P0_E855',#1368,#255,#1374,.T.);
#1376=ORIENTED_EDGE('',*,*,#1375,.T.);
#1377=EDGE_LOOP('',(#1354,#1362,#1370,#1376));
#1378=FACE_BOUND('',#1377,.T.);
#1379=ADVANCED_FACE('P0_F514',(#1378),#1353,.T.);
#1380=CARTESIAN_POINT('',(15.1519218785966,20.9022223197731,23.6183332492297));
#1381=DIRECTION('',(0.,0.,-1.));
#1382=DIRECTION('',(1.,0.,0.));
#1383=AXIS2_PLACEMENT_3D('',#1380,#1381,#1382);
#1384=PLANE('',#1383);
#1385=ORIENTED_EDGE('',*,*,#264,.F.);
#1386=ORIENTED_EDGE('',*,*,#1375,.F.);
#1387=DIRECTION('',(-1.,0.,0.));
#1388=VECTOR('',#1387,1.);
#1389=CARTESIAN_POINT('',(15.1519218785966,20.9022223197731,23.6183332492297));
#1390=LINE('',#1389,#1388);
#1391=CARTESIAN_POINT('',(14.4690292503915,20.9022223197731,23.6183332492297));
#1392=VERTEX_POINT('',#1391);
#1393=EDGE_CURVE('P0_E487',#1368,#1392,#1390,.T.);
#1394=ORIENTED_EDGE('',*,*,#1393,.T.);
#1395=DIRECTION('',(0.,1.,0.));
#1396=VECTOR('',#1395,1.);
#1397=CARTESIAN_POINT('',(14.4690292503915,20.9022223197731,23.6183332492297));
#1398=LINE('',#1397,#1396);
#1399=EDGE_CURVE('P0_E990',#1392,#263,#1398,.T.);
#1400=ORIENTED_EDGE('',*,*,#1399,.T.);
#1401=EDGE_LOOP('',(#1385,#1386,#1394,#1400));
#1402=FACE_BOUND('',#1401,.T.);
#1403=ADVANCED_FACE('P0_F509',(#1402),#1384,.T.);
#1404=CARTESIAN_POINT('',(14.4690292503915,20.9022223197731,23.6183332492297));
#1405=CARTESIAN_POINT('',(14.435600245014,20.9022223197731,23.6181602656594));
#1406=CARTESIAN_POINT('',(14.3708065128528,20.9022223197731,23.6178249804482));
#1407=CARTESIAN_POINT('',(14.2765942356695,20.9022223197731,23.6125042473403));
#1408=CARTESIAN_POINT('',(14.1883206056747,20.9022223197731,23.6054308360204));
#1409=CARTESIAN_POINT('',(14.1061416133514,20.9022223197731,23.5935655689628));
#1410=CARTESIAN_POINT('',(14.029522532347,20.9022223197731,23.5812628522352));
#1411=CARTESIAN_POINT('',(13.9592412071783,20.9022223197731,23.5632054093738));
#1412=CARTESIAN_POINT('',(13.894708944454,20.9022223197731,23.5432603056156));
#1413=CARTESIAN_POINT('',(13.8172189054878,20.9022223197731,23.5125720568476));
#1414=CARTESIAN_POINT('',(13.7292958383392,20.9022223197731,23.4649128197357));
#1415=CARTESIAN_POINT('',(13.6347949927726,20.9022223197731,23.3942296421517));
#1416=CARTESIAN_POINT('',(13.5526490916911,20.9022223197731,23.3094862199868));
#1417=CARTESIAN_POINT('',(13.4828007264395,20.9022223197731,23.2129144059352));
#1418=CARTESIAN_POINT('',(13.4267459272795,20.9022223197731,23.1066744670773));
#1419=CARTESIAN_POINT('',(13.386705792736,20.9022223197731,22.9930521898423));
#1420=CARTESIAN_POINT('',(13.3609824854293,20.9022223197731,22.8739591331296));
#1421=CARTESIAN_POINT('',(13.3583702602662,20.9022223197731,22.7923098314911));
#1422=CARTESIAN_POINT('',(13.3570500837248,20.9022223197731,22.7510455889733));
#1423=B_SPLINE_CURVE_WITH_KNOTS('',3,(#1404,#1405,#1406,#1407,#1408,#1409,#1410,#1411,#1412,
#1413,#1414,#1415,#1416,#1417,#1418,#1419,#1420,#1421,#1422),.UNSPECIFIED.,.F.,.F.,(4,1,1,1,1,1,
1,1,1,1,1,1,1,1,1,1,4),(0.,0.0625801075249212,0.12129582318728,0.176640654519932,
0.228314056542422,0.276729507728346,0.321834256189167,0.364044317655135,0.403128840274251,
0.477724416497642,0.550537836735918,0.623256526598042,0.697830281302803,0.772992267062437,
0.847315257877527,0.922835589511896,1.),.UNSPECIFIED.);
#1424=DIRECTION('',(0.,1.,0.));
#1425=VECTOR('',#1424,1.);
#1426=SURFACE_OF_LINEAR_EXTRUSION('',#1423,#1425);
#1427=ORIENTED_EDGE('',*,*,#288,.F.);
#1428=ORIENTED_EDGE('',*,*,#1399,.F.);
#1429=CARTESIAN_POINT('',(13.3570500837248,20.9022223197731,22.7510455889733));
#1430=VERTEX_POINT('',#1429);
#1431=EDGE_CURVE('P0_E490',#1392,#1430,#1423,.T.);
#1432=ORIENTED_EDGE('',*,*,#1431,.T.);
#1433=DIRECTION('',(0.,1.,0.));
#1434=VECTOR('',#1433,1.);
#1435=CARTESIAN_POINT('',(13.3570500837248,20.9022223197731,22.7510455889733));
#1436=LINE('',#1435,#1434);
#1437=EDGE_CURVE('P0_E992',#1430,#287,#1436,.T.);
#1438=ORIENTED_EDGE('',*,*,#1437,.T.);
#1439=EDGE_LOOP('',(#1427,#1428,#1432,#1438));
#1440=FACE_BOUND('',#1439,.T.);
#1441=ADVANCED_FACE('P0_F504',(#1440),#1426,.T.);
#1442=CARTESIAN_POINT('',(13.3570500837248,20.9022223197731,22.7510455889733));
#1443=CARTESIAN_POINT('',(13.3581496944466,20.9022223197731,22.7123947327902));
#1444=CARTESIAN_POINT('',(13.3603105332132,20.9022223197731,22.6364421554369));
#1445=CARTESIAN_POINT('',(13.380721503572,20.9022223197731,22.525544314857));
#1446=CARTESIAN_POINT('',(13.4131166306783,20.9022223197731,22.4200869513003));
#1447=CARTESIAN_POINT('',(13.4578880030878,20.9022223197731,22.3201603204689));
#1448=CARTESIAN_POINT('',(13.5155734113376,20.9022223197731,22.2276245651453));
#1449=CARTESIAN_POINT('',(13.5846886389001,20.9022223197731,22.142766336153));
#1450=CARTESIAN_POINT('',(13.6677300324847,20.9022223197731,22.0687928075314));
#1451=CARTESIAN_POINT('',(13.7299781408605,20.9022223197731,22.0274529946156));
#1452=CARTESIAN_POINT('',(13.7615973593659,20.9022223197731,22.0064542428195));
#1453=B_SPLINE_CURVE_WITH_KNOTS('',3,(#1442,#1443,#1444,#1445,#1446,#1447,#1448,#1449,#1450,
#1451,#1452),.UNSPECIFIED.,.F.,.F.,(4,1,1,1,1,1,1,1,4),(0.,0.130580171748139,0.25660235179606,
0.379828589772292,0.502910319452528,0.625707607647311,0.747527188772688,0.871755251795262,1.),.UNSPECIFIED.);
#1454=DIRECTION('',(0.,1.,0.));
#1455=VECTOR('',#1454,1.);
#1456=SURFACE_OF_LINEAR_EXTRUSION('',#1453,#1455);
#1457=ORIENTED_EDGE('',*,*,#304,.F.);
#1458=ORIENTED_EDGE('',*,*,#1437,.F.);
#1459=CARTESIAN_POINT('',(13.7615973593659,20.9022223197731,22.0064542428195));
#1460=VERTEX_POINT('',#1459);
#1461=EDGE_CURVE('P0_E495',#1430,#1460,#1453,.T.);
#1462=ORIENTED_EDGE('',*,*,#1461,.T.);
#1463=DIRECTION('',(0.,1.,0.));
#1464=VECTOR('',#1463,1.);
#1465=CARTESIAN_POINT('',(13.7615973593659,20.9022223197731,22.0064542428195));
#1466=LINE('',#1465,#1464);
#1467=EDGE_CURVE('P0_E994',#1460,#303,#1466,.T.);
#1468=ORIENTED_EDGE('',*,*,#1467,.T.);
#1469=EDGE_LOOP('',(#1457,#1458,#1462,#1468));
#1470=FACE_BOUND('',#1469,.T.);
#1471=ADVANCED_FACE('P0_F508',(#1470),#1456,.T.);
#1472=CARTESIAN_POINT('',(13.7615973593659,20.9022223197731,22.0064542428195));
#1473=CARTESIAN_POINT('',(13.7218407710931,20.9022223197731,21.9911843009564));
#1474=CARTESIAN_POINT('',(13.645776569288,20.9022223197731,21.9619691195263));
#1475=CARTESIAN_POINT('',(13.541040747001,20.9022223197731,21.9103977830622));
#1476=CARTESIAN_POINT('',(13.4511332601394,20.9022223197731,21.8541027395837));
#1477=CARTESIAN_POINT('',(13.3742978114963,20.9022223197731,21.7935755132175));
#1478=CARTESIAN_POINT('',(13.3089307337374,20.9022223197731,21.7273713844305));
#1479=CARTESIAN_POINT('',(13.2523190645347,20.9022223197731,21.6549524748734));
#1480=CARTESIAN_POINT('',(13.2033771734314,20.9022223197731,21.5763780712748));
#1481=CARTESIAN_POINT('',(13.1617279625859,20.9022223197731,21.4919369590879));
#1482=CARTESIAN_POINT('',(13.1290119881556,20.9022223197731,21.4023449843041));
#1483=CARTESIAN_POINT('',(13.1049662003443,20.9022223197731,21.3086964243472));
#1484=CARTESIAN_POINT('',(13.0907425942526,20.9022223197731,21.2113502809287));
#1485=CARTESIAN_POINT('',(13.0888022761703,20.9022223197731,21.1452892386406));
#1486=CARTESIAN_POINT('',(13.0878193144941,20.9022223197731,21.1118228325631));
#1487=B_SPLINE_CURVE_WITH_KNOTS('',3,(#1472,#1473,#1474,#1475,#1476,#1477,#1478,#1479,#1480,
#1481,#1482,#1483,#1484,#1485,#1486),.UNSPECIFIED.,.F.,.F.,(4,1,1,1,1,1,1,1,1,1,1,1,4),(0.,
0.106048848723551,0.202897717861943,0.290276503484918,0.369828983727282,0.445983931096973,
0.521448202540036,0.598336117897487,0.676181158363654,0.755560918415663,0.835476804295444,
0.916652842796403,1.),.UNSPECIFIED.);
#1488=DIRECTION('',(0.,1.,0.));
#1489=VECTOR('',#1488,1.);
#1490=SURFACE_OF_LINEAR_EXTRUSION('',#1487,#1489);
#1491=ORIENTED_EDGE('',*,*,#324,.F.);
#1492=ORIENTED_EDGE('',*,*,#1467,.F.);
#1493=CARTESIAN_POINT('',(13.0878193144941,20.9022223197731,21.1118228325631));
#1494=VERTEX_POINT('',#1493);
#1495=EDGE_CURVE('P0_E1046',#1460,#1494,#1487,.T.);
#1496=ORIENTED_EDGE('',*,*,#1495,.T.);
#1497=DIRECTION('',(0.,1.,0.));
#1498=VECTOR('',#1497,1.);
#1499=CARTESIAN_POINT('',(13.0878193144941,20.9022223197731,21.1118228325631));
#1500=LINE('',#1499,#1498);
#1501=EDGE_CURVE('P0_E996',#1494,#323,#1500,.T.);
#1502=ORIENTED_EDGE('',*,*,#1501,.T.);
#1503=EDGE_LOOP('',(#1491,#1492,#1496,#1502));
#1504=FACE_BOUND('',#1503,.T.);
#1505=ADVANCED_FACE('P0_F1058',(#1504),#1490,.T.);
#1506=CARTESIAN_POINT('',(13.0878193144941,20.9022223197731,21.1118228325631));
#1507=CARTESIAN_POINT('',(13.0887959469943,20.9022223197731,21.077655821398));
#1508=CARTESIAN_POINT('',(13.0907174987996,20.9022223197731,21.0104312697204));
#1509=CARTESIAN_POINT('',(13.1049005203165,20.9022223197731,20.9116781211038));
#1510=CARTESIAN_POINT('',(13.1288984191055,20.9022223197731,20.8172958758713));
#1511=CARTESIAN_POINT('',(13.1620108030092,20.9022223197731,20.7267175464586));
#1512=CARTESIAN_POINT('',(13.20492996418,20.9022223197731,20.6401330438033));
#1513=CARTESIAN_POINT('',(13.2579160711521,20.9022223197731,20.5578560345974));
#1514=CARTESIAN_POINT('',(13.3202253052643,20.9022223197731,20.479715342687));
#1515=CARTESIAN_POINT('',(13.3906448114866,20.9022223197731,20.4055730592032));
#1516=CARTESIAN_POINT('',(13.4691218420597,20.9022223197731,20.3377305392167));
#1517=CARTESIAN_POINT('',(13.5556085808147,20.9022223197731,20.2794088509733));
#1518=CARTESIAN_POINT('',(13.6477357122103,20.9022223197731,20.2292605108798));
#1519=CARTESIAN_POINT('',(13.7466809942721,20.9022223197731,20.1884315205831));
#1520=CARTESIAN_POINT('',(13.8521918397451,20.9022223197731,20.1569319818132));
#1521=CARTESIAN_POINT('',(13.9642095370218,20.9022223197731,20.1349854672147));
#1522=CARTESIAN_POINT('',(14.0825496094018,20.9022223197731,20.1201731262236));
#1523=CARTESIAN_POINT('',(14.1637599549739,20.9022223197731,20.1189569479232));
#1524=CARTESIAN_POINT('',(14.2054074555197,20.9022223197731,20.1183332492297));
#1525=B_SPLINE_CURVE_WITH_KNOTS('',3,(#1506,#1507,#1508,#1509,#1510,#1511,#1512,#1513,#1514,
#1515,#1516,#1517,#1518,#1519,#1520,#1521,#1522,#1523,#1524),.UNSPECIFIED.,.F.,.F.,(4,1,1,1,1,1,
1,1,1,1,1,1,1,1,1,1,4),(0.,0.061167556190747,0.12034888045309,0.178201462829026,
0.235263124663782,0.292717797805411,0.350875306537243,0.410152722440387,0.471423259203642,
0.533743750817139,0.595492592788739,0.657846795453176,0.721262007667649,0.786797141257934,
0.854668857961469,0.925469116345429,1.),.UNSPECIFIED.);
#1526=DIRECTION('',(0.,1.,0.));
#1527=VECTOR('',#1526,1.);
#1528=SURFACE_OF_LINEAR_EXTRUSION('',#1525,#1527);
#1529=ORIENTED_EDGE('',*,*,#346,.F.);
#1530=ORIENTED_EDGE('',*,*,#1501,.F.);
#1531=CARTESIAN_POINT('',(14.2054074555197,20.9022223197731,20.1183332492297));
#1532=VERTEX_POINT('',#1531);
#1533=EDGE_CURVE('P0_E1042',#1494,#1532,#1525,.T.);
#1534=ORIENTED_EDGE('',*,*,#1533,.T.);
#1535=DIRECTION('',(0.,1.,0.));
#1536=VECTOR('',#1535,1.);
#1537=CARTESIAN_POINT('',(14.2054074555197,20.9022223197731,20.1183332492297));
#1538=LINE('',#1537,#1536);
#1539=EDGE_CURVE('P0_E998',#1532,#245,#1538,.T.);
#1540=ORIENTED_EDGE('',*,*,#1539,.T.);
#1541=EDGE_LOOP('',(#1529,#1530,#1534,#1540));
#1542=FACE_BOUND('',#1541,.T.);
#1543=ADVANCED_FACE('P0_F1054',(#1542),#1528,.T.);
#1544=CARTESIAN_POINT('',(14.2054074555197,20.9022223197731,20.1183332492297));
#1545=DIRECTION('',(0.,0.,1.));
#1546=DIRECTION('',(-1.,0.,0.));
#1547=AXIS2_PLACEMENT_3D('',#1544,#1545,#1546);
#1548=PLANE('',#1547);
#1549=ORIENTED_EDGE('',*,*,#248,.F.);
#1550=ORIENTED_EDGE('',*,*,#1539,.F.);
#1551=DIRECTION('',(1.,0.,0.));
#1552=VECTOR('',#1551,1.);
#1553=CARTESIAN_POINT('',(14.2054074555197,20.9022223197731,20.1183332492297));
#1554=LINE('',#1553,#1552);
#1555=EDGE_CURVE('P0_E1002',#1532,#1360,#1554,.T.);
#1556=ORIENTED_EDGE('',*,*,#1555,.T.);
#1557=ORIENTED_EDGE('',*,*,#1361,.T.);
#1558=EDGE_LOOP('',(#1549,#1550,#1556,#1557));
#1559=FACE_BOUND('',#1558,.T.);
#1560=ADVANCED_FACE('P0_F1057',(#1559),#1548,.T.);
#1561=CARTESIAN_POINT('',(13.700407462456,20.9022223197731,23.4420275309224));
#1562=DIRECTION('',(0.,1.,0.));
#1563=DIRECTION('',(1.,0.,0.));
#1564=AXIS2_PLACEMENT_3D('',#1561,#1562,#1563);
#1565=PLANE('',#1564);
#1566=CARTESIAN_POINT('',(13.9747383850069,20.9022223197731,21.7372234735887));
#1567=CARTESIAN_POINT('',(13.9917674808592,20.9022223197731,21.7406785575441));
#1568=CARTESIAN_POINT('',(14.0286900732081,20.9022223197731,21.7481698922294));
#1569=CARTESIAN_POINT('',(14.088897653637,20.9022223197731,21.7560775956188));
#1570=CARTESIAN_POINT('',(14.1576335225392,20.9022223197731,21.7631226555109));
#1571=CARTESIAN_POINT('',(14.2350563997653,20.9022223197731,21.7683338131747));
#1572=CARTESIAN_POINT('',(14.321264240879,20.9022223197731,21.7737203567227));
#1573=CARTESIAN_POINT('',(14.4164411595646,20.9022223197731,21.775815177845));
#1574=CARTESIAN_POINT('',(14.5201984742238,20.9022223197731,21.7783144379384));
#1575=CARTESIAN_POINT('',(14.5921908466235,20.9022223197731,21.7784955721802));
#1576=CARTESIAN_POINT('',(14.6295861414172,20.9022223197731,21.7785896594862));
#1577=B_SPLINE_CURVE_WITH_KNOTS('',3,(#1566,#1567,#1568,#1569,#1570,#1571,#1572,#1573,#1574,
#1575,#1576),.UNSPECIFIED.,.F.,.F.,(4,1,1,1,1,1,1,1,4),(0.,0.0793064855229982,0.171952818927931,
0.277056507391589,0.394730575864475,0.526177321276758,0.671344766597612,0.829285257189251,1.),.UNSPECIFIED.);
#1578=CARTESIAN_POINT('',(13.9747383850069,20.9022223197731,21.7372234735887));
#1579=VERTEX_POINT('',#1578);
#1580=CARTESIAN_POINT('',(14.6295861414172,20.9022223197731,21.7785896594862));
#1581=VERTEX_POINT('',#1580);
#1582=EDGE_CURVE('P0_E371',#1579,#1581,#1577,.T.);
#1583=ORIENTED_EDGE('',*,*,#1582,.F.);
#1584=CARTESIAN_POINT('',(13.4019218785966,20.9022223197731,21.1118228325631));
#1585=CARTESIAN_POINT('',(13.4021971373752,20.9022223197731,21.1303165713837));
#1586=CARTESIAN_POINT('',(13.4027432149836,20.9022223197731,21.1670057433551));
#1587=CARTESIAN_POINT('',(13.4110161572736,20.9022223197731,21.2209157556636));
#1588=CARTESIAN_POINT('',(13.4229844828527,20.9022223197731,21.2731630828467));
#1589=CARTESIAN_POINT('',(13.4387471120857,20.9022223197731,21.3239654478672));
#1590=CARTESIAN_POINT('',(13.4607824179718,20.9022223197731,21.3724686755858));
#1591=CARTESIAN_POINT('',(13.4877958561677,20.9022223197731,21.4188587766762));
#1592=CARTESIAN_POINT('',(13.5187175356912,20.9022223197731,21.4640702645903));
#1593=CARTESIAN_POINT('',(13.566423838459,20.9022223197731,21.5219674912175));
#1594=CARTESIAN_POINT('',(13.6368261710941,20.9022223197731,21.5878465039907));
#1595=CARTESIAN_POINT('',(13.7368757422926,20.9022223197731,21.6515494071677));
#1596=CARTESIAN_POINT('',(13.8500075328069,20.9022223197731,21.7037533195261));
#1597=CARTESIAN_POINT('',(13.9322526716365,20.9022223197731,21.7258228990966));
#1598=CARTESIAN_POINT('',(13.9747383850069,20.9022223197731,21.7372234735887));
#1599=B_SPLINE_CURVE_WITH_KNOTS('',3,(#1584,#1585,#1586,#1587,#1588,#1589,#1590,#1591,#1592,
#1593,#1594,#1595,#1596,#1597,#1598),.UNSPECIFIED.,.F.,.F.,(4,1,1,1,1,1,1,1,1,1,1,1,4),(0.,
0.0602751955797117,0.119578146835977,0.177467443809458,0.235095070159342,0.292768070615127,
0.350832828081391,0.410047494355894,0.471255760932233,0.595327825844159,0.722634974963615,
0.856720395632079,1.),.UNSPECIFIED.);
#1600=CARTESIAN_POINT('',(13.4019218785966,20.9022223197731,21.1118228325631));
#1601=VERTEX_POINT('',#1600);
#1602=EDGE_CURVE('P0_E400',#1601,#1579,#1599,.T.);
#1603=ORIENTED_EDGE('',*,*,#1602,.F.);
#1604=CARTESIAN_POINT('',(14.3905036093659,20.9022223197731,20.4773076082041));
#1605=CARTESIAN_POINT('',(14.3584880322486,20.9022223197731,20.4777295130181));
#1606=CARTESIAN_POINT('',(14.2967822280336,20.9022223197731,20.4785426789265));
#1607=CARTESIAN_POINT('',(14.2076194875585,20.9022223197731,20.4804497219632));
#1608=CARTESIAN_POINT('',(14.1251950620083,20.9022223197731,20.4876637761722));
#1609=CARTESIAN_POINT('',(14.0492489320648,20.9022223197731,20.4943187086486));
#1610=CARTESIAN_POINT('',(13.979982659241,20.9022223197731,20.505698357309));
#1611=CARTESIAN_POINT('',(13.9168634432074,20.9022223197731,20.5164377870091));
#1612=CARTESIAN_POINT('',(13.860927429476,20.9022223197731,20.5323797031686));
#1613=CARTESIAN_POINT('',(13.7954693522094,20.9022223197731,20.5542899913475));
#1614=CARTESIAN_POINT('',(13.7223023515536,20.9022223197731,20.5893656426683));
#1615=CARTESIAN_POINT('',(13.6423439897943,20.9022223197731,20.6406108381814));
#1616=CARTESIAN_POINT('',(13.5726215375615,20.9022223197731,20.7038553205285));
#1617=CARTESIAN_POINT('',(13.5127713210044,20.9022223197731,20.7757839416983));
#1618=CARTESIAN_POINT('',(13.4633803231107,20.9022223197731,20.8537765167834));
#1619=CARTESIAN_POINT('',(13.4279376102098,20.9022223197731,20.9368134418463));
#1620=CARTESIAN_POINT('',(13.4059122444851,20.9022223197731,21.0232798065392));
#1621=CARTESIAN_POINT('',(13.4032546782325,20.9022223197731,21.0822490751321));
#1622=CARTESIAN_POINT('',(13.4019218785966,20.9022223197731,21.1118228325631));
#1623=B_SPLINE_CURVE_WITH_KNOTS('',3,(#1604,#1605,#1606,#1607,#1608,#1609,#1610,#1611,#1612,
#1613,#1614,#1615,#1616,#1617,#1618,#1619,#1620,#1621,#1622),.UNSPECIFIED.,.F.,.F.,(4,1,1,1,1,1,
1,1,1,1,1,1,1,1,1,1,4),(0.,0.0725235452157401,0.139779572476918,0.201892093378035,
0.259880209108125,0.312356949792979,0.360837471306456,0.404754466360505,0.443923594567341,
0.517087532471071,0.587851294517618,0.658315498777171,0.729340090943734,0.799249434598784,
0.86659704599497,0.933096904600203,1.),.UNSPECIFIED.);
#1624=CARTESIAN_POINT('',(14.3905036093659,20.9022223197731,20.4773076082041));
#1625=VERTEX_POINT('',#1624);
#1626=EDGE_CURVE('P0_E394',#1625,#1601,#1623,.T.);
#1627=ORIENTED_EDGE('',*,*,#1626,.F.);
#1628=DIRECTION('',(-1.,0.,0.));
#1629=VECTOR('',#1628,1.);
#1630=CARTESIAN_POINT('',(14.8378193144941,20.9022223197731,20.4773076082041));
#1631=LINE('',#1630,#1629);
#1632=CARTESIAN_POINT('',(14.8378193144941,20.9022223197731,20.4773076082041));
#1633=VERTEX_POINT('',#1632);
#1634=EDGE_CURVE('P0_E382',#1633,#1625,#1631,.T.);
#1635=ORIENTED_EDGE('',*,*,#1634,.F.);
#1636=DIRECTION('',(0.,0.,-1.));
#1637=VECTOR('',#1636,1.);
#1638=CARTESIAN_POINT('',(14.8378193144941,20.9022223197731,21.7785896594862));
#1639=LINE('',#1638,#1637);
#1640=CARTESIAN_POINT('',(14.8378193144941,20.9022223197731,21.7785896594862));
#1641=VERTEX_POINT('',#1640);
#1642=EDGE_CURVE('P0_E363',#1641,#1633,#1639,.T.);
#1643=ORIENTED_EDGE('',*,*,#1642,.F.);
#1644=DIRECTION('',(1.,0.,0.));
#1645=VECTOR('',#1644,1.);
#1646=CARTESIAN_POINT('',(14.6295861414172,20.9022223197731,21.7785896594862));
#1647=LINE('',#1646,#1645);
#1648=EDGE_CURVE('P0_E378',#1581,#1641,#1647,.T.);
#1649=ORIENTED_EDGE('',*,*,#1648,.F.);
#1650=EDGE_LOOP('',(#1583,#1603,#1627,#1635,#1643,#1649));
#1651=FACE_BOUND('',#1650,.T.);
#1652=CARTESIAN_POINT('',(13.6711526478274,20.9022223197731,22.7447354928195));
#1653=CARTESIAN_POINT('',(13.6716699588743,20.9022223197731,22.76416381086));
#1654=CARTESIAN_POINT('',(13.6726847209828,20.9022223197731,22.8022745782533));
#1655=CARTESIAN_POINT('',(13.6812975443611,20.9022223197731,22.8580117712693));
#1656=CARTESIAN_POINT('',(13.6952526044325,20.9022223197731,22.9103842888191));
#1657=CARTESIAN_POINT('',(13.7141515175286,20.9022223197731,22.9598947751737));
#1658=CARTESIAN_POINT('',(13.7399702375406,20.9022223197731,23.0053127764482));
#1659=CARTESIAN_POINT('',(13.7698975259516,20.9022223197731,23.0488084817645));
#1660=CARTESIAN_POINT('',(13.8068470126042,20.9022223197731,23.0877767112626));
#1661=CARTESIAN_POINT('',(13.8486032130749,20.9022223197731,23.1240935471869));
#1662=CARTESIAN_POINT('',(13.8963797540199,20.9022223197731,23.1565969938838));
#1663=CARTESIAN_POINT('',(13.9512059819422,20.9022223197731,23.183521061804));
#1664=CARTESIAN_POINT('',(14.0116645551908,20.9022223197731,23.2079232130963));
#1665=CARTESIAN_POINT('',(14.0793957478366,20.9022223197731,23.2259874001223));
#1666=CARTESIAN_POINT('',(14.1529961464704,20.9022223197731,23.2418720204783));
#1667=CARTESIAN_POINT('',(14.2334623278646,20.9022223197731,23.2518524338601));
#1668=CARTESIAN_POINT('',(14.3202843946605,20.9022223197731,23.2582749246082));
#1669=CARTESIAN_POINT('',(14.3804411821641,20.9022223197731,23.2589895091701));
#1670=CARTESIAN_POINT('',(14.411537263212,20.9022223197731,23.2593588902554));
#1671=B_SPLINE_CURVE_WITH_KNOTS('',3,(#1652,#1653,#1654,#1655,#1656,#1657,#1658,#1659,#1660,
#1661,#1662,#1663,#1664,#1665,#1666,#1667,#1668,#1669,#1670),.UNSPECIFIED.,.F.,.F.,(4,1,1,1,1,1,
1,1,1,1,1,1,1,1,1,1,4),(0.,0.0569817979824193,0.111776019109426,0.165003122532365,
0.215812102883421,0.266764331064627,0.317942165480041,0.370345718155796,0.423824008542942,
0.480120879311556,0.539308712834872,0.602723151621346,0.671107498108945,0.744672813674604,
0.823520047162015,0.908774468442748,1.),.UNSPECIFIED.);
#1672=CARTESIAN_POINT('',(13.6711526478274,20.9022223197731,22.7447354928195));
#1673=VERTEX_POINT('',#1672);
#1674=CARTESIAN_POINT('',(14.411537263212,20.9022223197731,23.2593588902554));
#1675=VERTEX_POINT('',#1674);
#1676=EDGE_CURVE('P0_E436',#1673,#1675,#1671,.T.);
#1677=ORIENTED_EDGE('',*,*,#1676,.F.);
#1678=CARTESIAN_POINT('',(14.6267816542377,20.9022223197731,22.1375640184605));
#1679=CARTESIAN_POINT('',(14.595932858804,20.9022223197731,22.1379639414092));
#1680=CARTESIAN_POINT('',(14.5363266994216,20.9022223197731,22.1387366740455));
#1681=CARTESIAN_POINT('',(14.4500068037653,20.9022223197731,22.1409501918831));
#1682=CARTESIAN_POINT('',(14.3698817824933,20.9022223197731,22.1471482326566));
#1683=CARTESIAN_POINT('',(14.2960899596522,20.9022223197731,22.1533445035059));
#1684=CARTESIAN_POINT('',(14.2287474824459,20.9022223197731,22.1634190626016));
#1685=CARTESIAN_POINT('',(14.1680037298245,20.9022223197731,22.1754112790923));
#1686=CARTESIAN_POINT('',(14.1129047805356,20.9022223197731,22.1880938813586));
#1687=CARTESIAN_POINT('',(14.0493667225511,20.9022223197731,22.2096646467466));
#1688=CARTESIAN_POINT('',(13.9772836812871,20.9022223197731,22.2415336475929));
#1689=CARTESIAN_POINT('',(13.9004904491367,20.9022223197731,22.2910397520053));
#1690=CARTESIAN_POINT('',(13.8324766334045,20.9022223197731,22.3499582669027));
#1691=CARTESIAN_POINT('',(13.7757315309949,20.9022223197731,22.418577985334));
#1692=CARTESIAN_POINT('',(13.7288799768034,20.9022223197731,22.4933169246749));
#1693=CARTESIAN_POINT('',(13.6960589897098,20.9022223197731,22.5735189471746));
#1694=CARTESIAN_POINT('',(13.6741782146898,20.9022223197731,22.6575700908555));
#1695=CARTESIAN_POINT('',(13.672171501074,20.9022223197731,22.7153827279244));
#1696=CARTESIAN_POINT('',(13.6711526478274,20.9022223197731,22.7447354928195));
#1697=B_SPLINE_CURVE_WITH_KNOTS('',3,(#1678,#1679,#1680,#1681,#1682,#1683,#1684,#1685,#1686,
#1687,#1688,#1689,#1690,#1691,#1692,#1693,#1694,#1695,#1696),.UNSPECIFIED.,.F.,.F.,(4,1,1,1,1,1,
1,1,1,1,1,1,1,1,1,1,4),(0.,0.072307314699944,0.139712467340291,0.202306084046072,
0.260622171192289,0.313217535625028,0.361770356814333,0.405741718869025,0.44557868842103,
0.518877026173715,0.589829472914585,0.658924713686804,0.728912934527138,0.797771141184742,
0.864803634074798,0.931357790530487,1.),.UNSPECIFIED.);
#1698=CARTESIAN_POINT('',(14.6267816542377,20.9022223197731,22.1375640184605));
#1699=VERTEX_POINT('',#1698);
#1700=EDGE_CURVE('P0_E443',#1699,#1673,#1697,.T.);
#1701=ORIENTED_EDGE('',*,*,#1700,.F.);
#1702=DIRECTION('',(-1.,0.,0.));
#1703=VECTOR('',#1702,1.);
#1704=CARTESIAN_POINT('',(14.8378193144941,20.9022223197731,22.1375640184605));
#1705=LINE('',#1704,#1703);
#1706=CARTESIAN_POINT('',(14.8378193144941,20.9022223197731,22.1375640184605));
#1707=VERTEX_POINT('',#1706);
#1708=EDGE_CURVE('P0_E1118',#1707,#1699,#1705,.T.);
#1709=ORIENTED_EDGE('',*,*,#1708,.F.);
#1710=DIRECTION('',(0.,0.,-1.));
#1711=VECTOR('',#1710,1.);
#1712=CARTESIAN_POINT('',(14.8378193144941,20.9022223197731,23.2593588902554));
#1713=LINE('',#1712,#1711);
#1714=CARTESIAN_POINT('',(14.8378193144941,20.9022223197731,23.2593588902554));
#1715=VERTEX_POINT('',#1714);
#1716=EDGE_CURVE('P0_E1116',#1715,#1707,#1713,.T.);
#1717=ORIENTED_EDGE('',*,*,#1716,.F.);
#1718=DIRECTION('',(1.,0.,0.));
#1719=VECTOR('',#1718,1.);
#1720=CARTESIAN_POINT('',(14.411537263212,20.9022223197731,23.2593588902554));
#1721=LINE('',#1720,#1719);
#1722=EDGE_CURVE('P0_E471',#1675,#1715,#1721,.T.);
#1723=ORIENTED_EDGE('',*,*,#1722,.F.);
#1724=EDGE_LOOP('',(#1677,#1701,#1709,#1717,#1723));
#1725=FACE_BOUND('',#1724,.T.);
#1726=ORIENTED_EDGE('',*,*,#1369,.F.);
#1727=ORIENTED_EDGE('',*,*,#1555,.F.);
#1728=ORIENTED_EDGE('',*,*,#1533,.F.);
#1729=ORIENTED_EDGE('',*,*,#1495,.F.);
#1730=ORIENTED_EDGE('',*,*,#1461,.F.);
#1731=ORIENTED_EDGE('',*,*,#1431,.F.);
#1732=ORIENTED_EDGE('',*,*,#1393,.F.);
#1733=EDGE_LOOP('',(#1726,#1727,#1728,#1729,#1730,#1731,#1732));
#1734=FACE_BOUND('',#1733,.T.);
#1735=ADVANCED_FACE('P0_F376',(#1651,#1725,#1734),#1565,.T.);
#1736=CARTESIAN_POINT('',(14.411537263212,20.9022223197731,23.2593588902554));
#1737=DIRECTION('',(0.,0.,1.));
#1738=DIRECTION('',(-1.,0.,0.));
#1739=AXIS2_PLACEMENT_3D('',#1736,#1737,#1738);
#1740=PLANE('',#1739);
#1741=DIRECTION('',(1.,0.,0.));
#1742=VECTOR('',#1741,1.);
#1743=CARTESIAN_POINT('',(14.411537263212,21.1022223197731,23.2593588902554));
#1744=LINE('',#1743,#1742);
#1745=CARTESIAN_POINT('',(14.411537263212,21.1022223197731,23.2593588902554));
#1746=VERTEX_POINT('',#1745);
#1747=CARTESIAN_POINT('',(14.8378193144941,21.1022223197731,23.2593588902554));
#1748=VERTEX_POINT('',#1747);
#1749=EDGE_CURVE('P0_E448',#1746,#1748,#1744,.T.);
#1750=ORIENTED_EDGE('',*,*,#1749,.F.);
#1751=DIRECTION('',(0.,1.,0.));
#1752=VECTOR('',#1751,1.);
#1753=CARTESIAN_POINT('',(14.411537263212,20.9022223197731,23.2593588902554));
#1754=LINE('',#1753,#1752);
#1755=EDGE_CURVE('P0_E472',#1675,#1746,#1754,.T.);
#1756=ORIENTED_EDGE('',*,*,#1755,.F.);
#1757=ORIENTED_EDGE('',*,*,#1722,.T.);
#1758=DIRECTION('',(0.,1.,0.));
#1759=VECTOR('',#1758,1.);
#1760=CARTESIAN_POINT('',(14.8378193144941,20.9022223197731,23.2593588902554));
#1761=LINE('',#1760,#1759);
#1762=EDGE_CURVE('P0_E442',#1715,#1748,#1761,.T.);
#1763=ORIENTED_EDGE('',*,*,#1762,.T.);
#1764=EDGE_LOOP('',(#1750,#1756,#1757,#1763));
#1765=FACE_BOUND('',#1764,.T.);
#1766=ADVANCED_FACE('P0_F432',(#1765),#1740,.T.);
#1767=DIRECTION('',(0.,1.,0.));
#1768=VECTOR('',#1767,1.);
#1769=SURFACE_OF_LINEAR_EXTRUSION('',#1671,#1768);
#1770=CARTESIAN_POINT('',(13.6711526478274,21.1022223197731,22.7447354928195));
#1771=CARTESIAN_POINT('',(13.6716699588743,21.1022223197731,22.76416381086));
#1772=CARTESIAN_POINT('',(13.6726847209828,21.1022223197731,22.8022745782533));
#1773=CARTESIAN_POINT('',(13.6812975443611,21.1022223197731,22.8580117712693));
#1774=CARTESIAN_POINT('',(13.6952526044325,21.1022223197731,22.9103842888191));
#1775=CARTESIAN_POINT('',(13.7141515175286,21.1022223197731,22.9598947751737));
#1776=CARTESIAN_POINT('',(13.7399702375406,21.1022223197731,23.0053127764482));
#1777=CARTESIAN_POINT('',(13.7698975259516,21.1022223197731,23.0488084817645));
#1778=CARTESIAN_POINT('',(13.8068470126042,21.1022223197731,23.0877767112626));
#1779=CARTESIAN_POINT('',(13.8486032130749,21.1022223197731,23.1240935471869));
#1780=CARTESIAN_POINT('',(13.8963797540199,21.1022223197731,23.1565969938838));
#1781=CARTESIAN_POINT('',(13.9512059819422,21.1022223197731,23.183521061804));
#1782=CARTESIAN_POINT('',(14.0116645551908,21.1022223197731,23.2079232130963));
#1783=CARTESIAN_POINT('',(14.0793957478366,21.1022223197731,23.2259874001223));
#1784=CARTESIAN_POINT('',(14.1529961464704,21.1022223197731,23.2418720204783));
#1785=CARTESIAN_POINT('',(14.2334623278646,21.1022223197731,23.2518524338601));
#1786=CARTESIAN_POINT('',(14.3202843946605,21.1022223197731,23.2582749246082));
#1787=CARTESIAN_POINT('',(14.3804411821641,21.1022223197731,23.2589895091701));
#1788=CARTESIAN_POINT('',(14.411537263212,21.1022223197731,23.2593588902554));
#1789=B_SPLINE_CURVE_WITH_KNOTS('',3,(#1770,#1771,#1772,#1773,#1774,#1775,#1776,#1777,#1778,
#1779,#1780,#1781,#1782,#1783,#1784,#1785,#1786,#1787,#1788),.UNSPECIFIED.,.F.,.F.,(4,1,1,1,1,1,
1,1,1,1,1,1,1,1,1,1,4),(0.,0.0569817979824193,0.111776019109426,0.165003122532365,
0.215812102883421,0.266764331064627,0.317942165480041,0.370345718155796,0.423824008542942,
0.480120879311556,0.539308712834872,0.602723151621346,0.671107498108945,0.744672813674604,
0.823520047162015,0.908774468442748,1.),.UNSPECIFIED.);
#1790=CARTESIAN_POINT('',(13.6711526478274,21.1022223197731,22.7447354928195));
#1791=VERTEX_POINT('',#1790);
#1792=EDGE_CURVE('P0_E463',#1791,#1746,#1789,.T.);
#1793=ORIENTED_EDGE('',*,*,#1792,.F.);
#1794=DIRECTION('',(0.,1.,0.));
#1795=VECTOR('',#1794,1.);
#1796=CARTESIAN_POINT('',(13.6711526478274,20.9022223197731,22.7447354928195));
#1797=LINE('',#1796,#1795);
#1798=EDGE_CURVE('P0_E477',#1673,#1791,#1797,.T.);
#1799=ORIENTED_EDGE('',*,*,#1798,.F.);
#1800=ORIENTED_EDGE('',*,*,#1676,.T.);
#1801=ORIENTED_EDGE('',*,*,#1755,.T.);
#1802=EDGE_LOOP('',(#1793,#1799,#1800,#1801));
#1803=FACE_BOUND('',#1802,.T.);
#1804=ADVANCED_FACE('P0_F427',(#1803),#1769,.T.);
#1805=DIRECTION('',(0.,1.,0.));
#1806=VECTOR('',#1805,1.);
#1807=SURFACE_OF_LINEAR_EXTRUSION('',#1697,#1806);
#1808=CARTESIAN_POINT('',(14.6267816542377,21.1022223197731,22.1375640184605));
#1809=CARTESIAN_POINT('',(14.595932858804,21.1022223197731,22.1379639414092));
#1810=CARTESIAN_POINT('',(14.5363266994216,21.1022223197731,22.1387366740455));
#1811=CARTESIAN_POINT('',(14.4500068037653,21.1022223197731,22.1409501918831));
#1812=CARTESIAN_POINT('',(14.3698817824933,21.1022223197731,22.1471482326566));
#1813=CARTESIAN_POINT('',(14.2960899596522,21.1022223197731,22.1533445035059));
#1814=CARTESIAN_POINT('',(14.2287474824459,21.1022223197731,22.1634190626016));
#1815=CARTESIAN_POINT('',(14.1680037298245,21.1022223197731,22.1754112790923));
#1816=CARTESIAN_POINT('',(14.1129047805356,21.1022223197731,22.1880938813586));
#1817=CARTESIAN_POINT('',(14.0493667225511,21.1022223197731,22.2096646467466));
#1818=CARTESIAN_POINT('',(13.9772836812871,21.1022223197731,22.2415336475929));
#1819=CARTESIAN_POINT('',(13.9004904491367,21.1022223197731,22.2910397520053));
#1820=CARTESIAN_POINT('',(13.8324766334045,21.1022223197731,22.3499582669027));
#1821=CARTESIAN_POINT('',(13.7757315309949,21.1022223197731,22.418577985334));
#1822=CARTESIAN_POINT('',(13.7288799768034,21.1022223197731,22.4933169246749));
#1823=CARTESIAN_POINT('',(13.6960589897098,21.1022223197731,22.5735189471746));
#1824=CARTESIAN_POINT('',(13.6741782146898,21.1022223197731,22.6575700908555));
#1825=CARTESIAN_POINT('',(13.672171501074,21.1022223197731,22.7153827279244));
#1826=CARTESIAN_POINT('',(13.6711526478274,21.1022223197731,22.7447354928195));
#1827=B_SPLINE_CURVE_WITH_KNOTS('',3,(#1808,#1809,#1810,#1811,#1812,#1813,#1814,#1815,#1816,
#1817,#1818,#1819,#1820,#1821,#1822,#1823,#1824,#1825,#1826),.UNSPECIFIED.,.F.,.F.,(4,1,1,1,1,1,
1,1,1,1,1,1,1,1,1,1,4),(0.,0.072307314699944,0.139712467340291,0.202306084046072,
0.260622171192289,0.313217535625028,0.361770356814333,0.405741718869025,0.44557868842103,
0.518877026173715,0.589829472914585,0.658924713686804,0.728912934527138,0.797771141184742,
0.864803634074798,0.931357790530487,1.),.UNSPECIFIED.);
#1828=CARTESIAN_POINT('',(14.6267816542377,21.1022223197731,22.1375640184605));
#1829=VERTEX_POINT('',#1828);
#1830=EDGE_CURVE('P0_E458',#1829,#1791,#1827,.T.);
#1831=ORIENTED_EDGE('',*,*,#1830,.F.);
#1832=DIRECTION('',(0.,1.,0.));
#1833=VECTOR('',#1832,1.);
#1834=CARTESIAN_POINT('',(14.6267816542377,20.9022223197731,22.1375640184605));
#1835=LINE('',#1834,#1833);
#1836=EDGE_CURVE('P0_E479',#1699,#1829,#1835,.T.);
#1837=ORIENTED_EDGE('',*,*,#1836,.F.);
#1838=ORIENTED_EDGE('',*,*,#1700,.T.);
#1839=ORIENTED_EDGE('',*,*,#1798,.T.);
#1840=EDGE_LOOP('',(#1831,#1837,#1838,#1839));
#1841=FACE_BOUND('',#1840,.T.);
#1842=ADVANCED_FACE('P0_F431',(#1841),#1807,.T.);
#1843=CARTESIAN_POINT('',(14.8378193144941,20.9022223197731,22.1375640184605));
#1844=DIRECTION('',(0.,0.,-1.));
#1845=DIRECTION('',(1.,0.,0.));
#1846=AXIS2_PLACEMENT_3D('',#1843,#1844,#1845);
#1847=PLANE('',#1846);
#1848=DIRECTION('',(-1.,0.,0.));
#1849=VECTOR('',#1848,1.);
#1850=CARTESIAN_POINT('',(14.8378193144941,21.1022223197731,22.1375640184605));
#1851=LINE('',#1850,#1849);
#1852=CARTESIAN_POINT('',(14.8378193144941,21.1022223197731,22.1375640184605));
#1853=VERTEX_POINT('',#1852);
#1854=EDGE_CURVE('P0_E39',#1853,#1829,#1851,.T.);
#1855=ORIENTED_EDGE('',*,*,#1854,.F.);
#1856=DIRECTION('',(0.,1.,0.));
#1857=VECTOR('',#1856,1.);
#1858=CARTESIAN_POINT('',(14.8378193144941,20.9022223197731,22.1375640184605));
#1859=LINE('',#1858,#1857);
#1860=EDGE_CURVE('P0_E481',#1707,#1853,#1859,.T.);
#1861=ORIENTED_EDGE('',*,*,#1860,.F.);
#1862=ORIENTED_EDGE('',*,*,#1708,.T.);
#1863=ORIENTED_EDGE('',*,*,#1836,.T.);
#1864=EDGE_LOOP('',(#1855,#1861,#1862,#1863));
#1865=FACE_BOUND('',#1864,.T.);
#1866=ADVANCED_FACE('P0_F1098',(#1865),#1847,.T.);
#1867=CARTESIAN_POINT('',(14.8378193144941,20.9022223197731,23.2593588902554));
#1868=DIRECTION('',(1.,0.,0.));
#1869=DIRECTION('',(0.,0.,1.));
#1870=AXIS2_PLACEMENT_3D('',#1867,#1868,#1869);
#1871=PLANE('',#1870);
#1872=DIRECTION('',(0.,0.,-1.));
#1873=VECTOR('',#1872,1.);
#1874=CARTESIAN_POINT('',(14.8378193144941,21.1022223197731,23.2593588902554));
#1875=LINE('',#1874,#1873);
#1876=EDGE_CURVE('P0_E454',#1748,#1853,#1875,.T.);
#1877=ORIENTED_EDGE('',*,*,#1876,.F.);
#1878=ORIENTED_EDGE('',*,*,#1762,.F.);
#1879=ORIENTED_EDGE('',*,*,#1716,.T.);
#1880=ORIENTED_EDGE('',*,*,#1860,.T.);
#1881=EDGE_LOOP('',(#1877,#1878,#1879,#1880));
#1882=FACE_BOUND('',#1881,.T.);
#1883=ADVANCED_FACE('P0_F426',(#1882),#1871,.T.);
#1884=CARTESIAN_POINT('',(14.6295861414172,20.9022223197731,21.7785896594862));
#1885=DIRECTION('',(0.,0.,1.));
#1886=DIRECTION('',(-1.,0.,0.));
#1887=AXIS2_PLACEMENT_3D('',#1884,#1885,#1886);
#1888=PLANE('',#1887);
#1889=DIRECTION('',(1.,0.,0.));
#1890=VECTOR('',#1889,1.);
#1891=CARTESIAN_POINT('',(14.6295861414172,21.1022223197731,21.7785896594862));
#1892=LINE('',#1891,#1890);
#1893=CARTESIAN_POINT('',(14.6295861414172,21.1022223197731,21.7785896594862));
#1894=VERTEX_POINT('',#1893);
#1895=CARTESIAN_POINT('',(14.8378193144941,21.1022223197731,21.7785896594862));
#1896=VERTEX_POINT('',#1895);
#1897=EDGE_CURVE('P0_E947',#1894,#1896,#1892,.T.);
#1898=ORIENTED_EDGE('',*,*,#1897,.F.);
#1899=DIRECTION('',(0.,1.,0.));
#1900=VECTOR('',#1899,1.);
#1901=CARTESIAN_POINT('',(14.6295861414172,20.9022223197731,21.7785896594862));
#1902=LINE('',#1901,#1900);
#1903=EDGE_CURVE('P0_E386',#1581,#1894,#1902,.T.);
#1904=ORIENTED_EDGE('',*,*,#1903,.F.);
#1905=ORIENTED_EDGE('',*,*,#1648,.T.);
#1906=DIRECTION('',(0.,1.,0.));
#1907=VECTOR('',#1906,1.);
#1908=CARTESIAN_POINT('',(14.8378193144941,20.9022223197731,21.7785896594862));
#1909=LINE('',#1908,#1907);
#1910=EDGE_CURVE('P0_E359',#1641,#1896,#1909,.T.);
#1911=ORIENTED_EDGE('',*,*,#1910,.T.);
#1912=EDGE_LOOP('',(#1898,#1904,#1905,#1911));
#1913=FACE_BOUND('',#1912,.T.);
#1914=ADVANCED_FACE('P0_F385',(#1913),#1888,.T.);
#1915=DIRECTION('',(0.,1.,0.));
#1916=VECTOR('',#1915,1.);
#1917=SURFACE_OF_LINEAR_EXTRUSION('',#1577,#1916);
#1918=CARTESIAN_POINT('',(13.9747383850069,21.1022223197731,21.7372234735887));
#1919=CARTESIAN_POINT('',(13.9917674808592,21.1022223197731,21.7406785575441));
#1920=CARTESIAN_POINT('',(14.0286900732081,21.1022223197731,21.7481698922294));
#1921=CARTESIAN_POINT('',(14.088897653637,21.1022223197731,21.7560775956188));
#1922=CARTESIAN_POINT('',(14.1576335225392,21.1022223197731,21.7631226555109));
#1923=CARTESIAN_POINT('',(14.2350563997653,21.1022223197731,21.7683338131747));
#1924=CARTESIAN_POINT('',(14.321264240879,21.1022223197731,21.7737203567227));
#1925=CARTESIAN_POINT('',(14.4164411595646,21.1022223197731,21.775815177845));
#1926=CARTESIAN_POINT('',(14.5201984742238,21.1022223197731,21.7783144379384));
#1927=CARTESIAN_POINT('',(14.5921908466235,21.1022223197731,21.7784955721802));
#1928=CARTESIAN_POINT('',(14.6295861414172,21.1022223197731,21.7785896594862));
#1929=B_SPLINE_CURVE_WITH_KNOTS('',3,(#1918,#1919,#1920,#1921,#1922,#1923,#1924,#1925,#1926,
#1927,#1928),.UNSPECIFIED.,.F.,.F.,(4,1,1,1,1,1,1,1,4),(0.,0.0793064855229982,0.171952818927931,
0.277056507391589,0.394730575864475,0.526177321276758,0.671344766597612,0.829285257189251,1.),.UNSPECIFIED.);
#1930=CARTESIAN_POINT('',(13.9747383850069,21.1022223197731,21.7372234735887));
#1931=VERTEX_POINT('',#1930);
#1932=EDGE_CURVE('P0_E387',#1931,#1894,#1929,.T.);
#1933=ORIENTED_EDGE('',*,*,#1932,.F.);
#1934=DIRECTION('',(0.,1.,0.));
#1935=VECTOR('',#1934,1.);
#1936=CARTESIAN_POINT('',(13.9747383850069,20.9022223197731,21.7372234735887));
#1937=LINE('',#1936,#1935);
#1938=EDGE_CURVE('P0_E1128',#1579,#1931,#1937,.T.);
#1939=ORIENTED_EDGE('',*,*,#1938,.F.);
#1940=ORIENTED_EDGE('',*,*,#1582,.T.);
#1941=ORIENTED_EDGE('',*,*,#1903,.T.);
#1942=EDGE_LOOP('',(#1933,#1939,#1940,#1941));
#1943=FACE_BOUND('',#1942,.T.);
#1944=ADVANCED_FACE('P0_F425',(#1943),#1917,.T.);
#1945=DIRECTION('',(0.,1.,0.));
#1946=VECTOR('',#1945,1.);
#1947=SURFACE_OF_LINEAR_EXTRUSION('',#1599,#1946);
#1948=CARTESIAN_POINT('',(13.4019218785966,21.1022223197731,21.1118228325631));
#1949=CARTESIAN_POINT('',(13.4021971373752,21.1022223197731,21.1303165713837));
#1950=CARTESIAN_POINT('',(13.4027432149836,21.1022223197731,21.1670057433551));
#1951=CARTESIAN_POINT('',(13.4110161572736,21.1022223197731,21.2209157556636));
#1952=CARTESIAN_POINT('',(13.4229844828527,21.1022223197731,21.2731630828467));
#1953=CARTESIAN_POINT('',(13.4387471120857,21.1022223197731,21.3239654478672));
#1954=CARTESIAN_POINT('',(13.4607824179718,21.1022223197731,21.3724686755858));
#1955=CARTESIAN_POINT('',(13.4877958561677,21.1022223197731,21.4188587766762));
#1956=CARTESIAN_POINT('',(13.5187175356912,21.1022223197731,21.4640702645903));
#1957=CARTESIAN_POINT('',(13.566423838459,21.1022223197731,21.5219674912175));
#1958=CARTESIAN_POINT('',(13.6368261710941,21.1022223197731,21.5878465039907));
#1959=CARTESIAN_POINT('',(13.7368757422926,21.1022223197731,21.6515494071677));
#1960=CARTESIAN_POINT('',(13.8500075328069,21.1022223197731,21.7037533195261));
#1961=CARTESIAN_POINT('',(13.9322526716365,21.1022223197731,21.7258228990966));
#1962=CARTESIAN_POINT('',(13.9747383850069,21.1022223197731,21.7372234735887));
#1963=B_SPLINE_CURVE_WITH_KNOTS('',3,(#1948,#1949,#1950,#1951,#1952,#1953,#1954,#1955,#1956,
#1957,#1958,#1959,#1960,#1961,#1962),.UNSPECIFIED.,.F.,.F.,(4,1,1,1,1,1,1,1,1,1,1,1,4),(0.,
0.0602751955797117,0.119578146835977,0.177467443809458,0.235095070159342,0.292768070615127,
0.350832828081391,0.410047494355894,0.471255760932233,0.595327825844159,0.722634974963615,
0.856720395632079,1.),.UNSPECIFIED.);
#1964=CARTESIAN_POINT('',(13.4019218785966,21.1022223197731,21.1118228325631));
#1965=VERTEX_POINT('',#1964);
#1966=EDGE_CURVE('P0_E390',#1965,#1931,#1963,.T.);
#1967=ORIENTED_EDGE('',*,*,#1966,.F.);
#1968=DIRECTION('',(0.,1.,0.));
#1969=VECTOR('',#1968,1.);
#1970=CARTESIAN_POINT('',(13.4019218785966,20.9022223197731,21.1118228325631));
#1971=LINE('',#1970,#1969);
#1972=EDGE_CURVE('P0_E1126',#1601,#1965,#1971,.T.);
#1973=ORIENTED_EDGE('',*,*,#1972,.F.);
#1974=ORIENTED_EDGE('',*,*,#1602,.T.);
#1975=ORIENTED_EDGE('',*,*,#1938,.T.);
#1976=EDGE_LOOP('',(#1967,#1973,#1974,#1975));
#1977=FACE_BOUND('',#1976,.T.);
#1978=ADVANCED_FACE('P0_F414',(#1977),#1947,.T.);
#1979=DIRECTION('',(0.,1.,0.));
#1980=VECTOR('',#1979,1.);
#1981=SURFACE_OF_LINEAR_EXTRUSION('',#1623,#1980);
#1982=CARTESIAN_POINT('',(14.3905036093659,21.1022223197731,20.4773076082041));
#1983=CARTESIAN_POINT('',(14.3584880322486,21.1022223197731,20.4777295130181));
#1984=CARTESIAN_POINT('',(14.2967822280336,21.1022223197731,20.4785426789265));
#1985=CARTESIAN_POINT('',(14.2076194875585,21.1022223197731,20.4804497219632));
#1986=CARTESIAN_POINT('',(14.1251950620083,21.1022223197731,20.4876637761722));
#1987=CARTESIAN_POINT('',(14.0492489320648,21.1022223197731,20.4943187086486));
#1988=CARTESIAN_POINT('',(13.979982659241,21.1022223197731,20.505698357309));
#1989=CARTESIAN_POINT('',(13.9168634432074,21.1022223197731,20.5164377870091));
#1990=CARTESIAN_POINT('',(13.860927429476,21.1022223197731,20.5323797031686));
#1991=CARTESIAN_POINT('',(13.7954693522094,21.1022223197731,20.5542899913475));
#1992=CARTESIAN_POINT('',(13.7223023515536,21.1022223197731,20.5893656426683));
#1993=CARTESIAN_POINT('',(13.6423439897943,21.1022223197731,20.6406108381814));
#1994=CARTESIAN_POINT('',(13.5726215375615,21.1022223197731,20.7038553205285));
#1995=CARTESIAN_POINT('',(13.5127713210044,21.1022223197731,20.7757839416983));
#1996=CARTESIAN_POINT('',(13.4633803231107,21.1022223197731,20.8537765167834));
#1997=CARTESIAN_POINT('',(13.4279376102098,21.1022223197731,20.9368134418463));
#1998=CARTESIAN_POINT('',(13.4059122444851,21.1022223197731,21.0232798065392));
#1999=CARTESIAN_POINT('',(13.4032546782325,21.1022223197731,21.0822490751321));
#2000=CARTESIAN_POINT('',(13.4019218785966,21.1022223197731,21.1118228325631));
#2001=B_SPLINE_CURVE_WITH_KNOTS('',3,(#1982,#1983,#1984,#1985,#1986,#1987,#1988,#1989,#1990,
#1991,#1992,#1993,#1994,#1995,#1996,#1997,#1998,#1999,#2000),.UNSPECIFIED.,.F.,.F.,(4,1,1,1,1,1,
1,1,1,1,1,1,1,1,1,1,4),(0.,0.0725235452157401,0.139779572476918,0.201892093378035,
0.259880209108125,0.312356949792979,0.360837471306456,0.404754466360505,0.443923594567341,
0.517087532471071,0.587851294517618,0.658315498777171,0.729340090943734,0.799249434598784,
0.86659704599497,0.933096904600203,1.),.UNSPECIFIED.);
#2002=CARTESIAN_POINT('',(14.3905036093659,21.1022223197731,20.4773076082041));
#2003=VERTEX_POINT('',#2002);
#2004=EDGE_CURVE('P0_E1140',#2003,#1965,#2001,.T.);
#2005=ORIENTED_EDGE('',*,*,#2004,.F.);
#2006=DIRECTION('',(0.,1.,0.));
#2007=VECTOR('',#2006,1.);
#2008=CARTESIAN_POINT('',(14.3905036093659,20.9022223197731,20.4773076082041));
#2009=LINE('',#2008,#2007);
#2010=EDGE_CURVE('P0_E1124',#1625,#2003,#2009,.T.);
#2011=ORIENTED_EDGE('',*,*,#2010,.F.);
#2012=ORIENTED_EDGE('',*,*,#1626,.T.);
#2013=ORIENTED_EDGE('',*,*,#1972,.T.);
#2014=EDGE_LOOP('',(#2005,#2011,#2012,#2013));
#2015=FACE_BOUND('',#2014,.T.);
#2016=ADVANCED_FACE('P0_F409',(#2015),#1981,.T.);
#2017=CARTESIAN_POINT('',(14.8378193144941,20.9022223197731,20.4773076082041));
#2018=DIRECTION('',(0.,0.,-1.));
#2019=DIRECTION('',(1.,0.,0.));
#2020=AXIS2_PLACEMENT_3D('',#2017,#2018,#2019);
#2021=PLANE('',#2020);
#2022=DIRECTION('',(-1.,0.,0.));
#2023=VECTOR('',#2022,1.);
#2024=CARTESIAN_POINT('',(14.8378193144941,21.1022223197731,20.4773076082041));
#2025=LINE('',#2024,#2023);
#2026=CARTESIAN_POINT('',(14.8378193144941,21.1022223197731,20.4773076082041));
#2027=VERTEX_POINT('',#2026);
#2028=EDGE_CURVE('P0_E1148',#2027,#2003,#2025,.T.);
#2029=ORIENTED_EDGE('',*,*,#2028,.F.);
#2030=DIRECTION('',(0.,1.,0.));
#2031=VECTOR('',#2030,1.);
#2032=CARTESIAN_POINT('',(14.8378193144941,20.9022223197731,20.4773076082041));
#2033=LINE('',#2032,#2031);
#2034=EDGE_CURVE('P0_E370',#1633,#2027,#2033,.T.);
#2035=ORIENTED_EDGE('',*,*,#2034,.F.);
#2036=ORIENTED_EDGE('',*,*,#1634,.T.);
#2037=ORIENTED_EDGE('',*,*,#2010,.T.);
#2038=EDGE_LOOP('',(#2029,#2035,#2036,#2037));
#2039=FACE_BOUND('',#2038,.T.);
#2040=ADVANCED_FACE('P0_F413',(#2039),#2021,.T.);
#2041=CARTESIAN_POINT('',(14.8378193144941,20.9022223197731,21.7785896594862));
#2042=DIRECTION('',(1.,0.,0.));
#2043=DIRECTION('',(0.,0.,1.));
#2044=AXIS2_PLACEMENT_3D('',#2041,#2042,#2043);
#2045=PLANE('',#2044);
#2046=DIRECTION('',(0.,0.,-1.));
#2047=VECTOR('',#2046,1.);
#2048=CARTESIAN_POINT('',(14.8378193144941,21.1022223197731,21.7785896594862));
#2049=LINE('',#2048,#2047);
#2050=EDGE_CURVE('P0_E365',#1896,#2027,#2049,.T.);
#2051=ORIENTED_EDGE('',*,*,#2050,.F.);
#2052=ORIENTED_EDGE('',*,*,#1910,.F.);
#2053=ORIENTED_EDGE('',*,*,#1642,.T.);
#2054=ORIENTED_EDGE('',*,*,#2034,.T.);
#2055=EDGE_LOOP('',(#2051,#2052,#2053,#2054));
#2056=FACE_BOUND('',#2055,.T.);
#2057=ADVANCED_FACE('P0_F361',(#2056),#2045,.T.);
#2058=ORIENTED_EDGE('',*,*,#1792,.T.);
#2059=ORIENTED_EDGE('',*,*,#1749,.T.);
#2060=ORIENTED_EDGE('',*,*,#1876,.T.);
#2061=ORIENTED_EDGE('',*,*,#1854,.T.);
#2062=ORIENTED_EDGE('',*,*,#1830,.T.);
#2063=EDGE_LOOP('',(#2058,#2059,#2060,#2061,#2062));
#2064=FACE_BOUND('',#2063,.T.);
#2065=ADVANCED_FACE('P0_F422',(#2064),#23,.T.);
#2066=ORIENTED_EDGE('',*,*,#1932,.T.);
#2067=ORIENTED_EDGE('',*,*,#1897,.T.);
#2068=ORIENTED_EDGE('',*,*,#2050,.T.);
#2069=ORIENTED_EDGE('',*,*,#2028,.T.);
#2070=ORIENTED_EDGE('',*,*,#2004,.T.);
#2071=ORIENTED_EDGE('',*,*,#1966,.T.);
#2072=EDGE_LOOP('',(#2066,#2067,#2068,#2069,#2070,#2071));
#2073=FACE_BOUND('',#2072,.T.);
#2074=ADVANCED_FACE('P0_F662',(#2073),#23,.T.);
#2075=CLOSED_SHELL('',(#350,#452,#474,#514,#531,#543,#574,#617,#641,#658,#693,#733,#773,#790,
#812,#824,#836,#853,#870,#882,#913,#937,#961,#985,#1009,#1033,#1057,#1081,#1105,#1129,#1153,
#1170,#1190,#1221,#1245,#1269,#1293,#1317,#1334,#1348,#1379,#1403,#1441,#1471,#1505,#1543,#1560,
#1735,#1766,#1804,#1842,#1866,#1883,#1914,#1944,#1978,#2016,#2040,#2057,#2065,#2074));
#2076=MANIFOLD_SOLID_BREP('P0_B1',#2075);
#2077=CARTESIAN_POINT('',(21.0677846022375,18.1022223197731,17.7683332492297));
#2078=DIRECTION('',(-1.,0.,0.));
#2079=DIRECTION('',(0.,0.,1.));
#2080=AXIS2_PLACEMENT_3D('',#2077,#2078,#2079);
#2081=PLANE('',#2080);
#2082=DIRECTION('',(0.,0.,-1.));
#2083=VECTOR('',#2082,1.);
#2084=CARTESIAN_POINT('',(21.0677846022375,8.10222231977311,17.7683332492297));
#2085=LINE('',#2084,#2083);
#2086=CARTESIAN_POINT('',(21.0677846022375,8.10222231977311,19.7683332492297));
#2087=VERTEX_POINT('',#2086);
#2088=CARTESIAN_POINT('',(21.0677846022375,8.10222231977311,18.5683332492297));
#2089=VERTEX_POINT('',#2088);
#2090=EDGE_CURVE('P1_E729',#2087,#2089,#2085,.T.);
#2091=ORIENTED_EDGE('',*,*,#2090,.T.);
#2092=DIRECTION('',(0.,-1.,0.));
#2093=VECTOR('',#2092,1.);
#2094=CARTESIAN_POINT('',(21.0677846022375,18.1022223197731,18.5683332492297));
#2095=LINE('',#2094,#2093);
#2096=CARTESIAN_POINT('',(21.0677846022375,18.1022223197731,18.5683332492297));
#2097=VERTEX_POINT('',#2096);
#2098=EDGE_CURVE('P1_E778',#2089,#2097,#2095,.F.);
#2099=ORIENTED_EDGE('',*,*,#2098,.T.);
#2100=DIRECTION('',(0.,0.,-1.));
#2101=VECTOR('',#2100,1.);
#2102=CARTESIAN_POINT('',(21.0677846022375,18.1022223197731,17.7683332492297));
#2103=LINE('',#2102,#2101);
#2104=CARTESIAN_POINT('',(21.0677846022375,18.1022223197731,19.7683332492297));
#2105=VERTEX_POINT('',#2104);
#2106=EDGE_CURVE('P1_E740',#2105,#2097,#2103,.T.);
#2107=ORIENTED_EDGE('',*,*,#2106,.F.);
#2108=DIRECTION('',(0.,1.,0.));
#2109=VECTOR('',#2108,1.);
#2110=CARTESIAN_POINT('',(21.0677846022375,17.1022223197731,19.7683332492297));
#2111=LINE('',#2110,#2109);
#2112=EDGE_CURVE('P1_E445',#2087,#2105,#2111,.T.);
#2113=ORIENTED_EDGE('',*,*,#2112,.F.);
#2114=EDGE_LOOP('',(#2091,#2099,#2107,#2113));
#2115=FACE_BOUND('',#2114,.T.);
#2116=ADVANCED_FACE('P1_F17',(#2115),#2081,.F.);
#2117=CARTESIAN_POINT('',(15.0677846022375,11.8022223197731,30.0982672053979));
#2118=DIRECTION('',(1.,0.,0.));
#2119=DIRECTION('',(0.,0.,-1.));
#2120=AXIS2_PLACEMENT_3D('',#2117,#2118,#2119);
#2121=PLANE('',#2120);
#2122=DIRECTION('',(0.,1.,0.));
#2123=VECTOR('',#2122,1.);
#2124=CARTESIAN_POINT('',(15.0677846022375,18.1022223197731,25.2683332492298));
#2125=LINE('',#2124,#2123);
#2126=CARTESIAN_POINT('',(15.0677846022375,14.1022223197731,25.2683332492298));
#2127=VERTEX_POINT('',#2126);
#2128=CARTESIAN_POINT('',(15.0677846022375,18.1022223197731,25.2683332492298));
#2129=VERTEX_POINT('',#2128);
#2130=EDGE_CURVE('P1_E592',#2127,#2129,#2125,.T.);
#2131=ORIENTED_EDGE('',*,*,#2130,.T.);
#2132=DIRECTION('',(0.,0.,-1.));
#2133=VECTOR('',#2132,1.);
#2134=CARTESIAN_POINT('',(15.0677846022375,18.1022223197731,30.0982672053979));
#2135=LINE('',#2134,#2133);
#2136=CARTESIAN_POINT('',(15.0677846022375,18.1022223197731,27.0683332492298));
#2137=VERTEX_POINT('',#2136);
#2138=EDGE_CURVE('P1_E645',#2137,#2129,#2135,.T.);
#2139=ORIENTED_EDGE('',*,*,#2138,.F.);
#2140=DIRECTION('',(0.,1.,0.));
#2141=VECTOR('',#2140,1.);
#2142=CARTESIAN_POINT('',(15.0677846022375,11.8022223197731,27.0683332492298));
#2143=LINE('',#2142,#2141);
#2144=CARTESIAN_POINT('',(15.0677846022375,11.8022223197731,27.0683332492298));
#2145=VERTEX_POINT('',#2144);
#2146=EDGE_CURVE('P1_E644',#2145,#2137,#2143,.T.);
#2147=ORIENTED_EDGE('',*,*,#2146,.F.);
#2148=DIRECTION('',(0.,0.,-1.));
#2149=VECTOR('',#2148,1.);
#2150=CARTESIAN_POINT('',(15.0677846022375,11.8022223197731,30.0982672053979));
#2151=LINE('',#2150,#2149);
#2152=CARTESIAN_POINT('',(15.0677846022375,11.8022223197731,23.748129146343));
#2153=VERTEX_POINT('',#2152);
#2154=EDGE_CURVE('P1_E612',#2145,#2153,#2151,.T.);
#2155=ORIENTED_EDGE('',*,*,#2154,.T.);
#2156=CARTESIAN_POINT('',(15.0677846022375,14.1022223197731,22.7683332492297));
#2157=DIRECTION('',(-1.,0.,0.));
#2158=DIRECTION('',(0.,0.,1.));
#2159=AXIS2_PLACEMENT_3D('',#2156,#2157,#2158);
#2160=CIRCLE('',#2159,2.5);
#2161=EDGE_CURVE('P1_E587',#2153,#2127,#2160,.T.);
#2162=ORIENTED_EDGE('',*,*,#2161,.T.);
#2163=EDGE_LOOP('',(#2131,#2139,#2147,#2155,#2162));
#2164=FACE_BOUND('',#2163,.T.);
#2165=ADVANCED_FACE('P1_F890',(#2164),#2121,.T.);
#2166=CARTESIAN_POINT('',(151.961726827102,18.1022223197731,30.0982672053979));
#2167=DIRECTION('',(0.,1.,0.));
#2168=DIRECTION('',(0.,0.,1.));
#2169=AXIS2_PLACEMENT_3D('',#2166,#2167,#2168);
#2170=PLANE('',#2169);
#2171=ORIENTED_EDGE('',*,*,#2106,.T.);
#2172=CARTESIAN_POINT('',(20.2677846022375,18.1022223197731,18.5683332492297));
#2173=DIRECTION('',(0.,1.,0.));
#2174=DIRECTION('',(0.,0.,1.));
#2175=AXIS2_PLACEMENT_3D('',#2172,#2173,#2174);
#2176=CIRCLE('',#2175,0.8);
#2177=CARTESIAN_POINT('',(20.2677846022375,18.1022223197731,17.7683332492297));
#2178=VERTEX_POINT('',#2177);
#2179=EDGE_CURVE('P1_E780',#2097,#2178,#2176,.T.);
#2180=ORIENTED_EDGE('',*,*,#2179,.T.);
#2181=DIRECTION('',(-1.,0.,0.));
#2182=VECTOR('',#2181,1.);
#2183=CARTESIAN_POINT('',(-4.93221539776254,18.1022223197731,17.7683332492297));
#2184=LINE('',#2183,#2182);
#2185=CARTESIAN_POINT('',(13.0677846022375,18.1022223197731,17.7683332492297));
#2186=VERTEX_POINT('',#2185);
#2187=EDGE_CURVE('P1_E741',#2178,#2186,#2184,.T.);
#2188=ORIENTED_EDGE('',*,*,#2187,.T.);
#2189=DIRECTION('',(0.,0.,-1.));
#2190=VECTOR('',#2189,1.);
#2191=CARTESIAN_POINT('',(13.0677846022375,18.1022223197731,17.7683332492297));
#2192=LINE('',#2191,#2190);
#2193=CARTESIAN_POINT('',(13.0677846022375,18.1022223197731,20.2683332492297));
#2194=VERTEX_POINT('',#2193);
#2195=EDGE_CURVE('P1_E684',#2194,#2186,#2192,.T.);
#2196=ORIENTED_EDGE('',*,*,#2195,.F.);
#2197=DIRECTION('',(-1.,0.,0.));
#2198=VECTOR('',#2197,1.);
#2199=CARTESIAN_POINT('',(15.0677846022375,18.1022223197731,20.2683332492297));
#2200=LINE('',#2199,#2198);
#2201=CARTESIAN_POINT('',(15.0677846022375,18.1022223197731,20.2683332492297));
#2202=VERTEX_POINT('',#2201);
#2203=EDGE_CURVE('P1_E596',#2202,#2194,#2200,.T.);
#2204=ORIENTED_EDGE('',*,*,#2203,.F.);
#2205=CARTESIAN_POINT('',(15.0677846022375,18.1022223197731,18.4683332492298));
#2206=VERTEX_POINT('',#2205);
#2207=EDGE_CURVE('P1_E606',#2202,#2206,#2135,.T.);
#2208=ORIENTED_EDGE('',*,*,#2207,.T.);
#2209=DIRECTION('',(-1.,0.,0.));
#2210=VECTOR('',#2209,1.);
#2211=CARTESIAN_POINT('',(151.961726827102,18.1022223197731,18.4683332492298));
#2212=LINE('',#2211,#2210);
#2213=CARTESIAN_POINT('',(16.0677846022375,18.1022223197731,18.4683332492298));
#2214=VERTEX_POINT('',#2213);
#2215=EDGE_CURVE('P1_E678',#2214,#2206,#2212,.T.);
#2216=ORIENTED_EDGE('',*,*,#2215,.F.);
#2217=DIRECTION('',(0.,0.,-1.));
#2218=VECTOR('',#2217,1.);
#2219=CARTESIAN_POINT('',(16.0677846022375,18.1022223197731,30.0982672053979));
#2220=LINE('',#2219,#2218);
#2221=CARTESIAN_POINT('',(16.0677846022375,18.1022223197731,19.7683332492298));
#2222=VERTEX_POINT('',#2221);
#2223=EDGE_CURVE('P1_E675',#2222,#2214,#2220,.T.);
#2224=ORIENTED_EDGE('',*,*,#2223,.F.);
#2225=DIRECTION('',(-1.,0.,0.));
#2226=VECTOR('',#2225,1.);
#2227=CARTESIAN_POINT('',(151.961726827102,18.1022223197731,19.7683332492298));
#2228=LINE('',#2227,#2226);
#2229=CARTESIAN_POINT('',(17.0677846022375,18.1022223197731,19.7683332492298));
#2230=VERTEX_POINT('',#2229);
#2231=EDGE_CURVE('P1_E672',#2230,#2222,#2228,.T.);
#2232=ORIENTED_EDGE('',*,*,#2231,.F.);
#2233=DIRECTION('',(0.,0.,-1.));
#2234=VECTOR('',#2233,1.);
#2235=CARTESIAN_POINT('',(17.0677846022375,18.1022223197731,30.0982672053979));
#2236=LINE('',#2235,#2234);
#2237=CARTESIAN_POINT('',(17.0677846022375,18.1022223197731,18.7683332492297));
#2238=VERTEX_POINT('',#2237);
#2239=EDGE_CURVE('P1_E669',#2230,#2238,#2236,.T.);
#2240=ORIENTED_EDGE('',*,*,#2239,.T.);
#2241=DIRECTION('',(-1.,0.,0.));
#2242=VECTOR('',#2241,1.);
#2243=CARTESIAN_POINT('',(151.961726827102,18.1022223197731,18.7683332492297));
#2244=LINE('',#2243,#2242);
#2245=CARTESIAN_POINT('',(19.0677846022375,18.1022223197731,18.7683332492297));
#2246=VERTEX_POINT('',#2245);
#2247=EDGE_CURVE('P1_E666',#2246,#2238,#2244,.T.);
#2248=ORIENTED_EDGE('',*,*,#2247,.F.);
#2249=DIRECTION('',(0.,0.,-1.));
#2250=VECTOR('',#2249,1.);
#2251=CARTESIAN_POINT('',(19.0677846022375,18.1022223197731,30.0982672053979));
#2252=LINE('',#2251,#2250);
#2253=CARTESIAN_POINT('',(19.0677846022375,18.1022223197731,26.7683332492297));
#2254=VERTEX_POINT('',#2253);
#2255=EDGE_CURVE('P1_E663',#2254,#2246,#2252,.T.);
#2256=ORIENTED_EDGE('',*,*,#2255,.F.);
#2257=DIRECTION('',(-1.,0.,0.));
#2258=VECTOR('',#2257,1.);
#2259=CARTESIAN_POINT('',(151.961726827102,18.1022223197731,26.7683332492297));
#2260=LINE('',#2259,#2258);
#2261=CARTESIAN_POINT('',(17.0677846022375,18.1022223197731,26.7683332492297));
#2262=VERTEX_POINT('',#2261);
#2263=EDGE_CURVE('P1_E660',#2254,#2262,#2260,.T.);
#2264=ORIENTED_EDGE('',*,*,#2263,.T.);
#2265=DIRECTION('',(0.,0.,-1.));
#2266=VECTOR('',#2265,1.);
#2267=CARTESIAN_POINT('',(17.0677846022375,18.1022223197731,30.0982672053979));
#2268=LINE('',#2267,#2266);
#2269=CARTESIAN_POINT('',(17.0677846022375,18.1022223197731,25.7683332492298));
#2270=VERTEX_POINT('',#2269);
#2271=EDGE_CURVE('P1_E657',#2262,#2270,#2268,.T.);
#2272=ORIENTED_EDGE('',*,*,#2271,.T.);
#2273=DIRECTION('',(-1.,0.,0.));
#2274=VECTOR('',#2273,1.);
#2275=CARTESIAN_POINT('',(151.961726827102,18.1022223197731,25.7683332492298));
#2276=LINE('',#2275,#2274);
#2277=CARTESIAN_POINT('',(16.0677846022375,18.1022223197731,25.7683332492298));
#2278=VERTEX_POINT('',#2277);
#2279=EDGE_CURVE('P1_E654',#2270,#2278,#2276,.T.);
#2280=ORIENTED_EDGE('',*,*,#2279,.T.);
#2281=DIRECTION('',(0.,0.,1.));
#2282=VECTOR('',#2281,1.);
#2283=CARTESIAN_POINT('',(16.0677846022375,18.1022223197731,30.0982672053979));
#2284=LINE('',#2283,#2282);
#2285=CARTESIAN_POINT('',(16.0677846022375,18.1022223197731,27.0683332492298));
#2286=VERTEX_POINT('',#2285);
#2287=EDGE_CURVE('P1_E651',#2278,#2286,#2284,.T.);
#2288=ORIENTED_EDGE('',*,*,#2287,.T.);
#2289=DIRECTION('',(-1.,0.,0.));
#2290=VECTOR('',#2289,1.);
#2291=CARTESIAN_POINT('',(151.961726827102,18.1022223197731,27.0683332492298));
#2292=LINE('',#2291,#2290);
#2293=EDGE_CURVE('P1_E648',#2286,#2137,#2292,.T.);
#2294=ORIENTED_EDGE('',*,*,#2293,.T.);
#2295=ORIENTED_EDGE('',*,*,#2138,.T.);
#2296=DIRECTION('',(-1.,0.,0.));
#2297=VECTOR('',#2296,1.);
#2298=CARTESIAN_POINT('',(15.0677846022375,18.1022223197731,25.2683332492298));
#2299=LINE('',#2298,#2297);
#2300=CARTESIAN_POINT('',(13.0677846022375,18.1022223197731,25.2683332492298));
#2301=VERTEX_POINT('',#2300);
#2302=EDGE_CURVE('P1_E603',#2129,#2301,#2299,.T.);
#2303=ORIENTED_EDGE('',*,*,#2302,.T.);
#2304=CARTESIAN_POINT('',(13.0677846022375,18.1022223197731,27.7683332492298));
#2305=VERTEX_POINT('',#2304);
#2306=EDGE_CURVE('P1_E721',#2305,#2301,#2192,.T.);
#2307=ORIENTED_EDGE('',*,*,#2306,.F.);
#2308=DIRECTION('',(1.,0.,0.));
#2309=VECTOR('',#2308,1.);
#2310=CARTESIAN_POINT('',(-4.93221539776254,18.1022223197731,27.7683332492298));
#2311=LINE('',#2310,#2309);
#2312=CARTESIAN_POINT('',(20.2677846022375,18.1022223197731,27.7683332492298));
#2313=VERTEX_POINT('',#2312);
#2314=EDGE_CURVE('P1_E745',#2305,#2313,#2311,.T.);
#2315=ORIENTED_EDGE('',*,*,#2314,.T.);
#2316=CARTESIAN_POINT('',(20.2677846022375,18.1022223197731,26.9683332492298));
#2317=DIRECTION('',(0.,1.,0.));
#2318=DIRECTION('',(0.,0.,1.));
#2319=AXIS2_PLACEMENT_3D('',#2316,#2317,#2318);
#2320=CIRCLE('',#2319,0.8);
#2321=CARTESIAN_POINT('',(21.0677846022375,18.1022223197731,26.9683332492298));
#2322=VERTEX_POINT('',#2321);
#2323=EDGE_CURVE('P1_E771',#2313,#2322,#2320,.T.);
#2324=ORIENTED_EDGE('',*,*,#2323,.T.);
#2325=CARTESIAN_POINT('',(21.0677846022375,18.1022223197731,25.7683332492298));
#2326=VERTEX_POINT('',#2325);
#2327=EDGE_CURVE('P1_E737',#2322,#2326,#2103,.T.);
#2328=ORIENTED_EDGE('',*,*,#2327,.T.);
#2329=DIRECTION('',(1.,0.,0.));
#2330=VECTOR('',#2329,1.);
#2331=CARTESIAN_POINT('',(20.3677846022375,18.1022223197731,25.7683332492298));
#2332=LINE('',#2331,#2330);
#2333=CARTESIAN_POINT('',(20.3677846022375,18.1022223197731,25.7683332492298));
#2334=VERTEX_POINT('',#2333);
#2335=EDGE_CURVE('P1_E442',#2334,#2326,#2332,.T.);
#2336=ORIENTED_EDGE('',*,*,#2335,.F.);
#2337=DIRECTION('',(0.,0.,1.));
#2338=VECTOR('',#2337,1.);
#2339=CARTESIAN_POINT('',(20.3677846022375,18.1022223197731,25.7683332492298));
#2340=LINE('',#2339,#2338);
#2341=CARTESIAN_POINT('',(20.3677846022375,18.1022223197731,19.7683332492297));
#2342=VERTEX_POINT('',#2341);
#2343=EDGE_CURVE('P1_E433',#2342,#2334,#2340,.T.);
#2344=ORIENTED_EDGE('',*,*,#2343,.F.);
#2345=DIRECTION('',(1.,0.,0.));
#2346=VECTOR('',#2345,1.);
#2347=CARTESIAN_POINT('',(20.3677846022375,18.1022223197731,19.7683332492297));
#2348=LINE('',#2347,#2346);
#2349=EDGE_CURVE('P1_E441',#2342,#2105,#2348,.T.);
#2350=ORIENTED_EDGE('',*,*,#2349,.T.);
#2351=EDGE_LOOP('',(#2171,#2180,#2188,#2196,#2204,#2208,#2216,#2224,#2232,#2240,#2248,#2256,
#2264,#2272,#2280,#2288,#2294,#2295,#2303,#2307,#2315,#2324,#2328,#2336,#2344,#2350));
#2352=FACE_BOUND('',#2351,.T.);
#2353=ADVANCED_FACE('P1_F897',(#2352),#2170,.T.);
#2354=ORIENTED_EDGE('',*,*,#2327,.F.);
#2355=DIRECTION('',(0.,-1.,0.));
#2356=VECTOR('',#2355,1.);
#2357=CARTESIAN_POINT('',(21.0677846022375,18.1022223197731,26.9683332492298));
#2358=LINE('',#2357,#2356);
#2359=CARTESIAN_POINT('',(21.0677846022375,8.10222231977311,26.9683332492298));
#2360=VERTEX_POINT('',#2359);
#2361=EDGE_CURVE('P1_E763',#2322,#2360,#2358,.T.);
#2362=ORIENTED_EDGE('',*,*,#2361,.T.);
#2363=CARTESIAN_POINT('',(21.0677846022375,8.10222231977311,25.7683332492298));
#2364=VERTEX_POINT('',#2363);
#2365=EDGE_CURVE('P1_E749',#2360,#2364,#2085,.T.);
#2366=ORIENTED_EDGE('',*,*,#2365,.T.);
#2367=DIRECTION('',(0.,-1.,0.));
#2368=VECTOR('',#2367,1.);
#2369=CARTESIAN_POINT('',(21.0677846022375,17.1022223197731,25.7683332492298));
#2370=LINE('',#2369,#2368);
#2371=EDGE_CURVE('P1_E452',#2326,#2364,#2370,.T.);
#2372=ORIENTED_EDGE('',*,*,#2371,.F.);
#2373=EDGE_LOOP('',(#2354,#2362,#2366,#2372));
#2374=FACE_BOUND('',#2373,.T.);
#2375=ADVANCED_FACE('P1_F893',(#2374),#2081,.F.);
#2376=CARTESIAN_POINT('',(-4.93221539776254,18.1022223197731,17.7683332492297));
#2377=DIRECTION('',(0.,0.,1.));
#2378=DIRECTION('',(1.,0.,0.));
#2379=AXIS2_PLACEMENT_3D('',#2376,#2377,#2378);
#2380=PLANE('',#2379);
#2381=DIRECTION('',(-1.,0.,0.));
#2382=VECTOR('',#2381,1.);
#2383=CARTESIAN_POINT('',(-4.93221539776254,8.10222231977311,17.7683332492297));
#2384=LINE('',#2383,#2382);
#2385=CARTESIAN_POINT('',(20.2677846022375,8.10222231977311,17.7683332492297));
#2386=VERTEX_POINT('',#2385);
#2387=CARTESIAN_POINT('',(-4.13221539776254,8.10222231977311,17.7683332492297));
#2388=VERTEX_POINT('',#2387);
#2389=EDGE_CURVE('P1_E751',#2386,#2388,#2384,.T.);
#2390=ORIENTED_EDGE('',*,*,#2389,.T.);
#2391=DIRECTION('',(0.,-1.,0.));
#2392=VECTOR('',#2391,1.);
#2393=CARTESIAN_POINT('',(-4.13221539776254,18.1022223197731,17.7683332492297));
#2394=LINE('',#2393,#2392);
#2395=CARTESIAN_POINT('',(-4.13221539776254,18.1022223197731,17.7683332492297));
#2396=VERTEX_POINT('',#2395);
#2397=EDGE_CURVE('P1_E798',#2388,#2396,#2394,.F.);
#2398=ORIENTED_EDGE('',*,*,#2397,.T.);
#2399=CARTESIAN_POINT('',(1.26778460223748,18.1022223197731,17.7683332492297));
#2400=VERTEX_POINT('',#2399);
#2401=EDGE_CURVE('P1_E739',#2400,#2396,#2184,.T.);
#2402=ORIENTED_EDGE('',*,*,#2401,.F.);
#2403=DIRECTION('',(0.,1.,0.));
#2404=VECTOR('',#2403,1.);
#2405=CARTESIAN_POINT('',(1.26778460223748,11.1022223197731,17.7683332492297));
#2406=LINE('',#2405,#2404);
#2407=CARTESIAN_POINT('',(1.26778460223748,11.1022223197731,17.7683332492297));
#2408=VERTEX_POINT('',#2407);
#2409=EDGE_CURVE('P1_E733',#2408,#2400,#2406,.T.);
#2410=ORIENTED_EDGE('',*,*,#2409,.F.);
#2411=DIRECTION('',(-1.,0.,0.));
#2412=VECTOR('',#2411,1.);
#2413=CARTESIAN_POINT('',(1.26778460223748,11.1022223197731,17.7683332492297));
#2414=LINE('',#2413,#2412);
#2415=CARTESIAN_POINT('',(13.0677846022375,11.1022223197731,17.7683332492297));
#2416=VERTEX_POINT('',#2415);
#2417=EDGE_CURVE('P1_E710',#2416,#2408,#2414,.T.);
#2418=ORIENTED_EDGE('',*,*,#2417,.F.);
#2419=DIRECTION('',(0.,1.,0.));
#2420=VECTOR('',#2419,1.);
#2421=CARTESIAN_POINT('',(13.0677846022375,11.1022223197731,17.7683332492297));
#2422=LINE('',#2421,#2420);
#2423=EDGE_CURVE('P1_E720',#2416,#2186,#2422,.T.);
#2424=ORIENTED_EDGE('',*,*,#2423,.T.);
#2425=ORIENTED_EDGE('',*,*,#2187,.F.);
#2426=DIRECTION('',(0.,-1.,0.));
#2427=VECTOR('',#2426,1.);
#2428=CARTESIAN_POINT('',(20.2677846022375,18.1022223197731,17.7683332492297));
#2429=LINE('',#2428,#2427);
#2430=EDGE_CURVE('P1_E773',#2178,#2386,#2429,.T.);
#2431=ORIENTED_EDGE('',*,*,#2430,.T.);
#2432=EDGE_LOOP('',(#2390,#2398,#2402,#2410,#2418,#2424,#2425,#2431));
#2433=FACE_BOUND('',#2432,.T.);
#2434=ADVANCED_FACE('P1_F905',(#2433),#2380,.F.);
#2435=CARTESIAN_POINT('',(-4.93221539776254,18.1022223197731,17.7683332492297));
#2436=DIRECTION('',(1.,0.,0.));
#2437=DIRECTION('',(0.,0.,-1.));
#2438=AXIS2_PLACEMENT_3D('',#2435,#2436,#2437);
#2439=PLANE('',#2438);
#2440=DIRECTION('',(0.,0.,1.));
#2441=VECTOR('',#2440,1.);
#2442=CARTESIAN_POINT('',(-4.93221539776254,18.1022223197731,17.7683332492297));
#2443=LINE('',#2442,#2441);
#2444=CARTESIAN_POINT('',(-4.93221539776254,18.1022223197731,18.5683332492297));
#2445=VERTEX_POINT('',#2444);
#2446=CARTESIAN_POINT('',(-4.93221539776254,18.1022223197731,26.9683332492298));
#2447=VERTEX_POINT('',#2446);
#2448=EDGE_CURVE('P1_E743',#2445,#2447,#2443,.T.);
#2449=ORIENTED_EDGE('',*,*,#2448,.F.);
#2450=DIRECTION('',(0.,-1.,0.));
#2451=VECTOR('',#2450,1.);
#2452=CARTESIAN_POINT('',(-4.93221539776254,18.1022223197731,18.5683332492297));
#2453=LINE('',#2452,#2451);
#2454=CARTESIAN_POINT('',(-4.93221539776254,8.10222231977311,18.5683332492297));
#2455=VERTEX_POINT('',#2454);
#2456=EDGE_CURVE('P1_E793',#2445,#2455,#2453,.T.);
#2457=ORIENTED_EDGE('',*,*,#2456,.T.);
#2458=DIRECTION('',(0.,0.,1.));
#2459=VECTOR('',#2458,1.);
#2460=CARTESIAN_POINT('',(-4.93221539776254,8.10222231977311,17.7683332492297));
#2461=LINE('',#2460,#2459);
#2462=CARTESIAN_POINT('',(-4.93221539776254,8.10222231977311,26.9683332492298));
#2463=VERTEX_POINT('',#2462);
#2464=EDGE_CURVE('P1_E754',#2455,#2463,#2461,.T.);
#2465=ORIENTED_EDGE('',*,*,#2464,.T.);
#2466=DIRECTION('',(0.,-1.,0.));
#2467=VECTOR('',#2466,1.);
#2468=CARTESIAN_POINT('',(-4.93221539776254,18.1022223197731,26.9683332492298));
#2469=LINE('',#2468,#2467);
#2470=EDGE_CURVE('P1_E788',#2463,#2447,#2469,.F.);
#2471=ORIENTED_EDGE('',*,*,#2470,.T.);
#2472=EDGE_LOOP('',(#2449,#2457,#2465,#2471));
#2473=FACE_BOUND('',#2472,.T.);
#2474=ADVANCED_FACE('P1_F911',(#2473),#2439,.F.);
#2475=CARTESIAN_POINT('',(-4.93221539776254,18.1022223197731,27.7683332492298));
#2476=DIRECTION('',(0.,0.,-1.));
#2477=DIRECTION('',(-1.,0.,0.));
#2478=AXIS2_PLACEMENT_3D('',#2475,#2476,#2477);
#2479=PLANE('',#2478);
#2480=CARTESIAN_POINT('',(-4.13221539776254,18.1022223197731,27.7683332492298));
#2481=VERTEX_POINT('',#2480);
#2482=CARTESIAN_POINT('',(1.26778460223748,18.1022223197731,27.7683332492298));
#2483=VERTEX_POINT('',#2482);
#2484=EDGE_CURVE('P1_E746',#2481,#2483,#2311,.T.);
#2485=ORIENTED_EDGE('',*,*,#2484,.F.);
#2486=DIRECTION('',(0.,-1.,0.));
#2487=VECTOR('',#2486,1.);
#2488=CARTESIAN_POINT('',(-4.13221539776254,18.1022223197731,27.7683332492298));
#2489=LINE('',#2488,#2487);
#2490=CARTESIAN_POINT('',(-4.13221539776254,8.10222231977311,27.7683332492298));
#2491=VERTEX_POINT('',#2490);
#2492=EDGE_CURVE('P1_E782',#2481,#2491,#2489,.T.);
#2493=ORIENTED_EDGE('',*,*,#2492,.T.);
#2494=DIRECTION('',(1.,0.,0.));
#2495=VECTOR('',#2494,1.);
#2496=CARTESIAN_POINT('',(-4.93221539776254,8.10222231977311,27.7683332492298));
#2497=LINE('',#2496,#2495);
#2498=CARTESIAN_POINT('',(20.2677846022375,8.10222231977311,27.7683332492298));
#2499=VERTEX_POINT('',#2498);
#2500=EDGE_CURVE('P1_E756',#2491,#2499,#2497,.T.);
#2501=ORIENTED_EDGE('',*,*,#2500,.T.);
#2502=DIRECTION('',(0.,-1.,0.));
#2503=VECTOR('',#2502,1.);
#2504=CARTESIAN_POINT('',(20.2677846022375,18.1022223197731,27.7683332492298));
#2505=LINE('',#2504,#2503);
#2506=EDGE_CURVE('P1_E769',#2499,#2313,#2505,.F.);
#2507=ORIENTED_EDGE('',*,*,#2506,.T.);
#2508=ORIENTED_EDGE('',*,*,#2314,.F.);
#2509=DIRECTION('',(0.,1.,0.));
#2510=VECTOR('',#2509,1.);
#2511=CARTESIAN_POINT('',(13.0677846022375,11.1022223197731,27.7683332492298));
#2512=LINE('',#2511,#2510);
#2513=CARTESIAN_POINT('',(13.0677846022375,11.1022223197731,27.7683332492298));
#2514=VERTEX_POINT('',#2513);
#2515=EDGE_CURVE('P1_E727',#2514,#2305,#2512,.T.);
#2516=ORIENTED_EDGE('',*,*,#2515,.F.);
#2517=DIRECTION('',(1.,0.,0.));
#2518=VECTOR('',#2517,1.);
#2519=CARTESIAN_POINT('',(1.26778460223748,11.1022223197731,27.7683332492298));
#2520=LINE('',#2519,#2518);
#2521=CARTESIAN_POINT('',(1.26778460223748,11.1022223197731,27.7683332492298));
#2522=VERTEX_POINT('',#2521);
#2523=EDGE_CURVE('P1_E717',#2522,#2514,#2520,.T.);
#2524=ORIENTED_EDGE('',*,*,#2523,.F.);
#2525=DIRECTION('',(0.,1.,0.));
#2526=VECTOR('',#2525,1.);
#2527=CARTESIAN_POINT('',(1.26778460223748,11.1022223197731,27.7683332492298));
#2528=LINE('',#2527,#2526);
#2529=EDGE_CURVE('P1_E730',#2522,#2483,#2528,.T.);
#2530=ORIENTED_EDGE('',*,*,#2529,.T.);
#2531=EDGE_LOOP('',(#2485,#2493,#2501,#2507,#2508,#2516,#2524,#2530));
#2532=FACE_BOUND('',#2531,.T.);
#2533=ADVANCED_FACE('P1_F1044',(#2532),#2479,.F.);
#2534=ORIENTED_EDGE('',*,*,#2401,.T.);
#2535=CARTESIAN_POINT('',(-4.13221539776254,18.1022223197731,18.5683332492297));
#2536=DIRECTION('',(0.,1.,0.));
#2537=DIRECTION('',(0.,0.,1.));
#2538=AXIS2_PLACEMENT_3D('',#2535,#2536,#2537);
#2539=CIRCLE('',#2538,0.8);
#2540=EDGE_CURVE('P1_E800',#2396,#2445,#2539,.T.);
#2541=ORIENTED_EDGE('',*,*,#2540,.T.);
#2542=ORIENTED_EDGE('',*,*,#2448,.T.);
#2543=CARTESIAN_POINT('',(-4.13221539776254,18.1022223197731,26.9683332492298));
#2544=DIRECTION('',(0.,1.,0.));
#2545=DIRECTION('',(0.,0.,1.));
#2546=AXIS2_PLACEMENT_3D('',#2543,#2544,#2545);
#2547=CIRCLE('',#2546,0.8);
#2548=EDGE_CURVE('P1_E791',#2447,#2481,#2547,.T.);
#2549=ORIENTED_EDGE('',*,*,#2548,.T.);
#2550=ORIENTED_EDGE('',*,*,#2484,.T.);
#2551=DIRECTION('',(0.,0.,1.));
#2552=VECTOR('',#2551,1.);
#2553=CARTESIAN_POINT('',(1.26778460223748,18.1022223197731,17.7683332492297));
#2554=LINE('',#2553,#2552);
#2555=CARTESIAN_POINT('',(1.26778460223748,18.1022223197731,25.2683332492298));
#2556=VERTEX_POINT('',#2555);
#2557=EDGE_CURVE('P1_E724',#2556,#2483,#2554,.T.);
#2558=ORIENTED_EDGE('',*,*,#2557,.F.);
#2559=DIRECTION('',(1.,0.,0.));
#2560=VECTOR('',#2559,1.);
#2561=CARTESIAN_POINT('',(-0.232215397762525,18.1022223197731,25.2683332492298));
#2562=LINE('',#2561,#2560);
#2563=CARTESIAN_POINT('',(0.0677846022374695,18.1022223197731,25.2683332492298));
#2564=VERTEX_POINT('',#2563);
#2565=EDGE_CURVE('P1_E486',#2564,#2556,#2562,.T.);
#2566=ORIENTED_EDGE('',*,*,#2565,.F.);
#2567=DIRECTION('',(0.,0.,1.));
#2568=VECTOR('',#2567,1.);
#2569=CARTESIAN_POINT('',(0.0677846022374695,18.1022223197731,30.0982672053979));
#2570=LINE('',#2569,#2568);
#2571=CARTESIAN_POINT('',(0.0677846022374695,18.1022223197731,27.0683332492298));
#2572=VERTEX_POINT('',#2571);
#2573=EDGE_CURVE('P1_E543',#2564,#2572,#2570,.T.);
#2574=ORIENTED_EDGE('',*,*,#2573,.T.);
#2575=DIRECTION('',(-1.,0.,0.));
#2576=VECTOR('',#2575,1.);
#2577=CARTESIAN_POINT('',(151.961726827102,18.1022223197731,27.0683332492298));
#2578=LINE('',#2577,#2576);
#2579=CARTESIAN_POINT('',(-0.932215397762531,18.1022223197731,27.0683332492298));
#2580=VERTEX_POINT('',#2579);
#2581=EDGE_CURVE('P1_E540',#2572,#2580,#2578,.T.);
#2582=ORIENTED_EDGE('',*,*,#2581,.T.);
#2583=DIRECTION('',(0.,0.,-1.));
#2584=VECTOR('',#2583,1.);
#2585=CARTESIAN_POINT('',(-0.932215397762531,18.1022223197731,30.0982672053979));
#2586=LINE('',#2585,#2584);
#2587=CARTESIAN_POINT('',(-0.932215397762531,18.1022223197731,25.7683332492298));
#2588=VERTEX_POINT('',#2587);
#2589=EDGE_CURVE('P1_E537',#2580,#2588,#2586,.T.);
#2590=ORIENTED_EDGE('',*,*,#2589,.T.);
#2591=DIRECTION('',(-1.,0.,0.));
#2592=VECTOR('',#2591,1.);
#2593=CARTESIAN_POINT('',(151.961726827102,18.1022223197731,25.7683332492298));
#2594=LINE('',#2593,#2592);
#2595=CARTESIAN_POINT('',(-1.93221539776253,18.1022223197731,25.7683332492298));
#2596=VERTEX_POINT('',#2595);
#2597=EDGE_CURVE('P1_E534',#2588,#2596,#2594,.T.);
#2598=ORIENTED_EDGE('',*,*,#2597,.T.);
#2599=DIRECTION('',(0.,0.,1.));
#2600=VECTOR('',#2599,1.);
#2601=CARTESIAN_POINT('',(-1.93221539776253,18.1022223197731,30.0982672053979));
#2602=LINE('',#2601,#2600);
#2603=CARTESIAN_POINT('',(-1.93221539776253,18.1022223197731,26.7683332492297));
#2604=VERTEX_POINT('',#2603);
#2605=EDGE_CURVE('P1_E531',#2596,#2604,#2602,.T.);
#2606=ORIENTED_EDGE('',*,*,#2605,.T.);
#2607=DIRECTION('',(-1.,0.,0.));
#2608=VECTOR('',#2607,1.);
#2609=CARTESIAN_POINT('',(151.961726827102,18.1022223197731,26.7683332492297));
#2610=LINE('',#2609,#2608);
#2611=CARTESIAN_POINT('',(-4.23221539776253,18.1022223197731,26.7683332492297));
#2612=VERTEX_POINT('',#2611);
#2613=EDGE_CURVE('P1_E528',#2604,#2612,#2610,.T.);
#2614=ORIENTED_EDGE('',*,*,#2613,.T.);
#2615=DIRECTION('',(0.,0.,1.));
#2616=VECTOR('',#2615,1.);
#2617=CARTESIAN_POINT('',(-4.23221539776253,18.1022223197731,30.0982672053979));
#2618=LINE('',#2617,#2616);
#2619=CARTESIAN_POINT('',(-4.23221539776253,18.1022223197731,18.7683332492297));
#2620=VERTEX_POINT('',#2619);
#2621=EDGE_CURVE('P1_E525',#2620,#2612,#2618,.T.);
#2622=ORIENTED_EDGE('',*,*,#2621,.F.);
#2623=DIRECTION('',(-1.,0.,0.));
#2624=VECTOR('',#2623,1.);
#2625=CARTESIAN_POINT('',(151.961726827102,18.1022223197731,18.7683332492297));
#2626=LINE('',#2625,#2624);
#2627=CARTESIAN_POINT('',(-1.93221539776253,18.1022223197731,18.7683332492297));
#2628=VERTEX_POINT('',#2627);
#2629=EDGE_CURVE('P1_E485',#2628,#2620,#2626,.T.);
#2630=ORIENTED_EDGE('',*,*,#2629,.F.);
#2631=DIRECTION('',(0.,0.,-1.));
#2632=VECTOR('',#2631,1.);
#2633=CARTESIAN_POINT('',(-1.93221539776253,18.1022223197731,30.0982672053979));
#2634=LINE('',#2633,#2632);
#2635=CARTESIAN_POINT('',(-1.93221539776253,18.1022223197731,19.7683332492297));
#2636=VERTEX_POINT('',#2635);
#2637=EDGE_CURVE('P1_E496',#2636,#2628,#2634,.T.);
#2638=ORIENTED_EDGE('',*,*,#2637,.F.);
#2639=DIRECTION('',(-1.,0.,0.));
#2640=VECTOR('',#2639,1.);
#2641=CARTESIAN_POINT('',(151.961726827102,18.1022223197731,19.7683332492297));
#2642=LINE('',#2641,#2640);
#2643=CARTESIAN_POINT('',(-0.932215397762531,18.1022223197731,19.7683332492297));
#2644=VERTEX_POINT('',#2643);
#2645=EDGE_CURVE('P1_E553',#2644,#2636,#2642,.T.);
#2646=ORIENTED_EDGE('',*,*,#2645,.F.);
#2647=DIRECTION('',(0.,0.,1.));
#2648=VECTOR('',#2647,1.);
#2649=CARTESIAN_POINT('',(-0.932215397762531,18.1022223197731,30.0982672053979));
#2650=LINE('',#2649,#2648);
#2651=CARTESIAN_POINT('',(-0.932215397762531,18.1022223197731,18.4683332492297));
#2652=VERTEX_POINT('',#2651);
#2653=EDGE_CURVE('P1_E550',#2652,#2644,#2650,.T.);
#2654=ORIENTED_EDGE('',*,*,#2653,.F.);
#2655=DIRECTION('',(-1.,0.,0.));
#2656=VECTOR('',#2655,1.);
#2657=CARTESIAN_POINT('',(151.961726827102,18.1022223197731,18.4683332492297));
#2658=LINE('',#2657,#2656);
#2659=CARTESIAN_POINT('',(0.0677846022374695,18.1022223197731,18.4683332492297));
#2660=VERTEX_POINT('',#2659);
#2661=EDGE_CURVE('P1_E547',#2660,#2652,#2658,.T.);
#2662=ORIENTED_EDGE('',*,*,#2661,.F.);
#2663=CARTESIAN_POINT('',(0.0677846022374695,18.1022223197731,20.2683332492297));
#2664=VERTEX_POINT('',#2663);
#2665=EDGE_CURVE('P1_E544',#2660,#2664,#2570,.T.);
#2666=ORIENTED_EDGE('',*,*,#2665,.T.);
#2667=DIRECTION('',(1.,0.,0.));
#2668=VECTOR('',#2667,1.);
#2669=CARTESIAN_POINT('',(-0.232215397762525,18.1022223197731,20.2683332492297));
#2670=LINE('',#2669,#2668);
#2671=CARTESIAN_POINT('',(1.26778460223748,18.1022223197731,20.2683332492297));
#2672=VERTEX_POINT('',#2671);
#2673=EDGE_CURVE('P1_E488',#2664,#2672,#2670,.T.);
#2674=ORIENTED_EDGE('',*,*,#2673,.T.);
#2675=EDGE_CURVE('P1_E711',#2400,#2672,#2554,.T.);
#2676=ORIENTED_EDGE('',*,*,#2675,.F.);
#2677=EDGE_LOOP('',(#2534,#2541,#2542,#2549,#2550,#2558,#2566,#2574,#2582,#2590,#2598,#2606,
#2614,#2622,#2630,#2638,#2646,#2654,#2662,#2666,#2674,#2676));
#2678=FACE_BOUND('',#2677,.T.);
#2679=ADVANCED_FACE('P1_F915',(#2678),#2170,.T.);
#2680=CARTESIAN_POINT('',(151.961726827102,8.10222231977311,30.0982672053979));
#2681=DIRECTION('',(0.,1.,0.));
#2682=DIRECTION('',(0.,0.,1.));
#2683=AXIS2_PLACEMENT_3D('',#2680,#2681,#2682);
#2684=PLANE('',#2683);
#2685=DIRECTION('',(-1.,0.,0.));
#2686=VECTOR('',#2685,1.);
#2687=CARTESIAN_POINT('',(18.3177846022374,8.10222231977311,23.5183332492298));
#2688=LINE('',#2687,#2686);
#2689=CARTESIAN_POINT('',(18.8177846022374,8.10222231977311,23.5183332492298));
#2690=VERTEX_POINT('',#2689);
#2691=CARTESIAN_POINT('',(18.3177846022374,8.10222231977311,23.5183332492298));
#2692=VERTEX_POINT('',#2691);
#2693=EDGE_CURVE('P1_E848',#2690,#2692,#2688,.T.);
#2694=ORIENTED_EDGE('',*,*,#2693,.F.);
#2695=DIRECTION('',(0.,0.,1.));
#2696=VECTOR('',#2695,1.);
#2697=CARTESIAN_POINT('',(18.8177846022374,8.10222231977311,22.0183332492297));
#2698=LINE('',#2697,#2696);
#2699=CARTESIAN_POINT('',(18.8177846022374,8.10222231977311,22.0183332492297));
#2700=VERTEX_POINT('',#2699);
#2701=EDGE_CURVE('P1_E429',#2700,#2690,#2698,.T.);
#2702=ORIENTED_EDGE('',*,*,#2701,.F.);
#2703=DIRECTION('',(1.,0.,0.));
#2704=VECTOR('',#2703,1.);
#2705=CARTESIAN_POINT('',(18.3177846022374,8.10222231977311,22.0183332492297));
#2706=LINE('',#2705,#2704);
#2707=CARTESIAN_POINT('',(18.3177846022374,8.10222231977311,22.0183332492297));
#2708=VERTEX_POINT('',#2707);
#2709=EDGE_CURVE('P1_E434',#2708,#2700,#2706,.T.);
#2710=ORIENTED_EDGE('',*,*,#2709,.F.);
#2711=DIRECTION('',(0.,0.,-1.));
#2712=VECTOR('',#2711,1.);
#2713=CARTESIAN_POINT('',(18.3177846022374,8.10222231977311,22.0183332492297));
#2714=LINE('',#2713,#2712);
#2715=EDGE_CURVE('P1_E851',#2692,#2708,#2714,.T.);
#2716=ORIENTED_EDGE('',*,*,#2715,.F.);
#2717=EDGE_LOOP('',(#2694,#2702,#2710,#2716));
#2718=FACE_BOUND('',#2717,.T.);
#2719=DIRECTION('',(-1.,0.,0.));
#2720=VECTOR('',#2719,1.);
#2721=CARTESIAN_POINT('',(-4.18221539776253,8.10222231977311,23.5183332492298));
#2722=LINE('',#2721,#2720);
#2723=CARTESIAN_POINT('',(-3.68221539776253,8.10222231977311,23.5183332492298));
#2724=VERTEX_POINT('',#2723);
#2725=CARTESIAN_POINT('',(-4.18221539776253,8.10222231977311,23.5183332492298));
#2726=VERTEX_POINT('',#2725);
#2727=EDGE_CURVE('P1_E415',#2724,#2726,#2722,.T.);
#2728=ORIENTED_EDGE('',*,*,#2727,.F.);
#2729=DIRECTION('',(0.,0.,1.));
#2730=VECTOR('',#2729,1.);
#2731=CARTESIAN_POINT('',(-3.68221539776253,8.10222231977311,22.0183332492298));
#2732=LINE('',#2731,#2730);
#2733=CARTESIAN_POINT('',(-3.68221539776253,8.10222231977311,22.0183332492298));
#2734=VERTEX_POINT('',#2733);
#2735=EDGE_CURVE('P1_E422',#2734,#2724,#2732,.T.);
#2736=ORIENTED_EDGE('',*,*,#2735,.F.);
#2737=DIRECTION('',(1.,0.,0.));
#2738=VECTOR('',#2737,1.);
#2739=CARTESIAN_POINT('',(-4.18221539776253,8.10222231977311,22.0183332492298));
#2740=LINE('',#2739,#2738);
#2741=CARTESIAN_POINT('',(-4.18221539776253,8.10222231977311,22.0183332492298));
#2742=VERTEX_POINT('',#2741);
#2743=EDGE_CURVE('P1_E418',#2742,#2734,#2740,.T.);
#2744=ORIENTED_EDGE('',*,*,#2743,.F.);
#2745=DIRECTION('',(0.,0.,-1.));
#2746=VECTOR('',#2745,1.);
#2747=CARTESIAN_POINT('',(-4.18221539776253,8.10222231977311,22.0183332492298));
#2748=LINE('',#2747,#2746);
#2749=EDGE_CURVE('P1_E401',#2726,#2742,#2748,.T.);
#2750=ORIENTED_EDGE('',*,*,#2749,.F.);
#2751=EDGE_LOOP('',(#2728,#2736,#2744,#2750));
#2752=FACE_BOUND('',#2751,.T.);
#2753=ORIENTED_EDGE('',*,*,#2464,.F.);
#2754=CARTESIAN_POINT('',(-4.13221539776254,8.10222231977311,18.5683332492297));
#2755=DIRECTION('',(0.,1.,0.));
#2756=DIRECTION('',(0.,0.,1.));
#2757=AXIS2_PLACEMENT_3D('',#2754,#2755,#2756);
#2758=CIRCLE('',#2757,0.8);
#2759=EDGE_CURVE('P1_E796',#2455,#2388,#2758,.F.);
#2760=ORIENTED_EDGE('',*,*,#2759,.T.);
#2761=ORIENTED_EDGE('',*,*,#2389,.F.);
#2762=CARTESIAN_POINT('',(20.2677846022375,8.10222231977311,18.5683332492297));
#2763=DIRECTION('',(0.,1.,0.));
#2764=DIRECTION('',(0.,0.,1.));
#2765=AXIS2_PLACEMENT_3D('',#2762,#2763,#2764);
#2766=CIRCLE('',#2765,0.8);
#2767=EDGE_CURVE('P1_E776',#2386,#2089,#2766,.F.);
#2768=ORIENTED_EDGE('',*,*,#2767,.T.);
#2769=ORIENTED_EDGE('',*,*,#2090,.F.);
#2770=DIRECTION('',(1.,0.,0.));
#2771=VECTOR('',#2770,1.);
#2772=CARTESIAN_POINT('',(19.5677846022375,8.10222231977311,19.7683332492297));
#2773=LINE('',#2772,#2771);
#2774=CARTESIAN_POINT('',(19.5677846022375,8.10222231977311,19.7683332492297));
#2775=VERTEX_POINT('',#2774);
#2776=EDGE_CURVE('P1_E460',#2775,#2087,#2773,.T.);
#2777=ORIENTED_EDGE('',*,*,#2776,.F.);
#2778=DIRECTION('',(0.,0.,-1.));
#2779=VECTOR('',#2778,1.);
#2780=CARTESIAN_POINT('',(19.5677846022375,8.10222231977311,25.7683332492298));
#2781=LINE('',#2780,#2779);
#2782=CARTESIAN_POINT('',(19.5677846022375,8.10222231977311,25.7683332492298));
#2783=VERTEX_POINT('',#2782);
#2784=EDGE_CURVE('P1_E448',#2783,#2775,#2781,.T.);
#2785=ORIENTED_EDGE('',*,*,#2784,.F.);
#2786=DIRECTION('',(1.,0.,0.));
#2787=VECTOR('',#2786,1.);
#2788=CARTESIAN_POINT('',(19.5677846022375,8.10222231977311,25.7683332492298));
#2789=LINE('',#2788,#2787);
#2790=EDGE_CURVE('P1_E464',#2783,#2364,#2789,.T.);
#2791=ORIENTED_EDGE('',*,*,#2790,.T.);
#2792=ORIENTED_EDGE('',*,*,#2365,.F.);
#2793=CARTESIAN_POINT('',(20.2677846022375,8.10222231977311,26.9683332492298));
#2794=DIRECTION('',(0.,1.,0.));
#2795=DIRECTION('',(0.,0.,1.));
#2796=AXIS2_PLACEMENT_3D('',#2793,#2794,#2795);
#2797=CIRCLE('',#2796,0.8);
#2798=EDGE_CURVE('P1_E766',#2360,#2499,#2797,.F.);
#2799=ORIENTED_EDGE('',*,*,#2798,.T.);
#2800=ORIENTED_EDGE('',*,*,#2500,.F.);
#2801=CARTESIAN_POINT('',(-4.13221539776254,8.10222231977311,26.9683332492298));
#2802=DIRECTION('',(0.,1.,0.));
#2803=DIRECTION('',(0.,0.,1.));
#2804=AXIS2_PLACEMENT_3D('',#2801,#2802,#2803);
#2805=CIRCLE('',#2804,0.8);
#2806=EDGE_CURVE('P1_E785',#2491,#2463,#2805,.F.);
#2807=ORIENTED_EDGE('',*,*,#2806,.T.);
#2808=EDGE_LOOP('',(#2753,#2760,#2761,#2768,#2769,#2777,#2785,#2791,#2792,#2799,#2800,#2807));
#2809=FACE_BOUND('',#2808,.T.);
#2810=ADVANCED_FACE('P1_F412',(#2718,#2752,#2809),#2684,.F.);
#2811=CARTESIAN_POINT('',(13.0677846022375,11.1022223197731,17.7683332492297));
#2812=DIRECTION('',(1.,0.,0.));
#2813=DIRECTION('',(0.,0.,-1.));
#2814=AXIS2_PLACEMENT_3D('',#2811,#2812,#2813);
#2815=PLANE('',#2814);
#2816=ORIENTED_EDGE('',*,*,#2306,.T.);
#2817=DIRECTION('',(0.,1.,0.));
#2818=VECTOR('',#2817,1.);
#2819=CARTESIAN_POINT('',(13.0677846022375,18.1022223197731,25.2683332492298));
#2820=LINE('',#2819,#2818);
#2821=CARTESIAN_POINT('',(13.0677846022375,14.1022223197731,25.2683332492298));
#2822=VERTEX_POINT('',#2821);
#2823=EDGE_CURVE('P1_E588',#2822,#2301,#2820,.T.);
#2824=ORIENTED_EDGE('',*,*,#2823,.F.);
#2825=CARTESIAN_POINT('',(13.0677846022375,14.1022223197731,22.7683332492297));
#2826=DIRECTION('',(-1.,0.,0.));
#2827=DIRECTION('',(0.,0.,1.));
#2828=AXIS2_PLACEMENT_3D('',#2825,#2826,#2827);
#2829=CIRCLE('',#2828,2.5);
#2830=CARTESIAN_POINT('',(13.0677846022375,14.1022223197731,20.2683332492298));
#2831=VERTEX_POINT('',#2830);
#2832=EDGE_CURVE('P1_E599',#2831,#2822,#2829,.T.);
#2833=ORIENTED_EDGE('',*,*,#2832,.F.);
#2834=DIRECTION('',(0.,-1.,0.));
#2835=VECTOR('',#2834,1.);
#2836=CARTESIAN_POINT('',(13.0677846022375,14.1022223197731,20.2683332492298));
#2837=LINE('',#2836,#2835);
#2838=EDGE_CURVE('P1_E560',#2194,#2831,#2837,.T.);
#2839=ORIENTED_EDGE('',*,*,#2838,.F.);
#2840=ORIENTED_EDGE('',*,*,#2195,.T.);
#2841=ORIENTED_EDGE('',*,*,#2423,.F.);
#2842=DIRECTION('',(0.,0.,-1.));
#2843=VECTOR('',#2842,1.);
#2844=CARTESIAN_POINT('',(13.0677846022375,11.1022223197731,17.7683332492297));
#2845=LINE('',#2844,#2843);
#2846=EDGE_CURVE('P1_E707',#2514,#2416,#2845,.T.);
#2847=ORIENTED_EDGE('',*,*,#2846,.F.);
#2848=ORIENTED_EDGE('',*,*,#2515,.T.);
#2849=EDGE_LOOP('',(#2816,#2824,#2833,#2839,#2840,#2841,#2847,#2848));
#2850=FACE_BOUND('',#2849,.T.);
#2851=ADVANCED_FACE('P1_F963',(#2850),#2815,.F.);
#2852=CARTESIAN_POINT('',(1.26778460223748,11.1022223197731,17.7683332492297));
#2853=DIRECTION('',(-1.,0.,0.));
#2854=DIRECTION('',(0.,0.,1.));
#2855=AXIS2_PLACEMENT_3D('',#2852,#2853,#2854);
#2856=PLANE('',#2855);
#2857=CARTESIAN_POINT('',(1.26778460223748,14.1022223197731,22.7683332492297));
#2858=DIRECTION('',(1.,0.,0.));
#2859=DIRECTION('',(0.,0.,-1.));
#2860=AXIS2_PLACEMENT_3D('',#2857,#2858,#2859);
#2861=CIRCLE('',#2860,2.5);
#2862=CARTESIAN_POINT('',(1.26778460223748,14.1022223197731,25.2683332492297));
#2863=VERTEX_POINT('',#2862);
#2864=CARTESIAN_POINT('',(1.26778460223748,14.1022223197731,20.2683332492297));
#2865=VERTEX_POINT('',#2864);
#2866=EDGE_CURVE('P1_E467',#2863,#2865,#2861,.T.);
#2867=ORIENTED_EDGE('',*,*,#2866,.F.);
#2868=DIRECTION('',(0.,-1.,0.));
#2869=VECTOR('',#2868,1.);
#2870=CARTESIAN_POINT('',(1.26778460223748,14.1022223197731,25.2683332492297));
#2871=LINE('',#2870,#2869);
#2872=EDGE_CURVE('P1_E479',#2556,#2863,#2871,.T.);
#2873=ORIENTED_EDGE('',*,*,#2872,.F.);
#2874=ORIENTED_EDGE('',*,*,#2557,.T.);
#2875=ORIENTED_EDGE('',*,*,#2529,.F.);
#2876=DIRECTION('',(0.,0.,1.));
#2877=VECTOR('',#2876,1.);
#2878=CARTESIAN_POINT('',(1.26778460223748,11.1022223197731,17.7683332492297));
#2879=LINE('',#2878,#2877);
#2880=EDGE_CURVE('P1_E714',#2408,#2522,#2879,.T.);
#2881=ORIENTED_EDGE('',*,*,#2880,.F.);
#2882=ORIENTED_EDGE('',*,*,#2409,.T.);
#2883=ORIENTED_EDGE('',*,*,#2675,.T.);
#2884=DIRECTION('',(0.,1.,0.));
#2885=VECTOR('',#2884,1.);
#2886=CARTESIAN_POINT('',(1.26778460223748,18.1022223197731,20.2683332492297));
#2887=LINE('',#2886,#2885);
#2888=EDGE_CURVE('P1_E477',#2865,#2672,#2887,.T.);
#2889=ORIENTED_EDGE('',*,*,#2888,.F.);
#2890=EDGE_LOOP('',(#2867,#2873,#2874,#2875,#2881,#2882,#2883,#2889));
#2891=FACE_BOUND('',#2890,.T.);
#2892=ADVANCED_FACE('P1_F1064',(#2891),#2856,.F.);
#2893=CARTESIAN_POINT('',(151.961726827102,11.1022223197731,30.0982672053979));
#2894=DIRECTION('',(0.,1.,0.));
#2895=DIRECTION('',(0.,0.,1.));
#2896=AXIS2_PLACEMENT_3D('',#2893,#2894,#2895);
#2897=PLANE('',#2896);
#2898=ORIENTED_EDGE('',*,*,#2846,.T.);
#2899=ORIENTED_EDGE('',*,*,#2417,.T.);
#2900=ORIENTED_EDGE('',*,*,#2880,.T.);
#2901=ORIENTED_EDGE('',*,*,#2523,.T.);
#2902=EDGE_LOOP('',(#2898,#2899,#2900,#2901));
#2903=FACE_BOUND('',#2902,.T.);
#2904=ADVANCED_FACE('P1_F1066',(#2903),#2897,.T.);
#2905=CARTESIAN_POINT('',(15.0677846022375,14.1022223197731,20.2683332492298));
#2906=VERTEX_POINT('',#2905);
#2907=CARTESIAN_POINT('',(15.0677846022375,11.8022223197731,21.7885373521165));
#2908=VERTEX_POINT('',#2907);
#2909=EDGE_CURVE('P1_E589',#2906,#2908,#2160,.T.);
#2910=ORIENTED_EDGE('',*,*,#2909,.T.);
#2911=CARTESIAN_POINT('',(15.0677846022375,11.8022223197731,18.4683332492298));
#2912=VERTEX_POINT('',#2911);
#2913=EDGE_CURVE('P1_E617',#2908,#2912,#2151,.T.);
#2914=ORIENTED_EDGE('',*,*,#2913,.T.);
#2915=DIRECTION('',(0.,1.,0.));
#2916=VECTOR('',#2915,1.);
#2917=CARTESIAN_POINT('',(15.0677846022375,11.8022223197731,18.4683332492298));
#2918=LINE('',#2917,#2916);
#2919=EDGE_CURVE('P1_E681',#2912,#2206,#2918,.T.);
#2920=ORIENTED_EDGE('',*,*,#2919,.T.);
#2921=ORIENTED_EDGE('',*,*,#2207,.F.);
#2922=DIRECTION('',(0.,-1.,0.));
#2923=VECTOR('',#2922,1.);
#2924=CARTESIAN_POINT('',(15.0677846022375,14.1022223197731,20.2683332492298));
#2925=LINE('',#2924,#2923);
#2926=EDGE_CURVE('P1_E584',#2202,#2906,#2925,.T.);
#2927=ORIENTED_EDGE('',*,*,#2926,.T.);
#2928=EDGE_LOOP('',(#2910,#2914,#2920,#2921,#2927));
#2929=FACE_BOUND('',#2928,.T.);
#2930=ADVANCED_FACE('P1_F900',(#2929),#2121,.T.);
#2931=CARTESIAN_POINT('',(151.961726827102,11.8022223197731,18.4683332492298));
#2932=DIRECTION('',(0.,0.,-1.));
#2933=DIRECTION('',(-1.,0.,0.));
#2934=AXIS2_PLACEMENT_3D('',#2931,#2932,#2933);
#2935=PLANE('',#2934);
#2936=ORIENTED_EDGE('',*,*,#2215,.T.);
#2937=ORIENTED_EDGE('',*,*,#2919,.F.);
#2938=DIRECTION('',(-1.,0.,0.));
#2939=VECTOR('',#2938,1.);
#2940=CARTESIAN_POINT('',(151.961726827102,11.8022223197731,18.4683332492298));
#2941=LINE('',#2940,#2939);
#2942=CARTESIAN_POINT('',(16.0677846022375,11.8022223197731,18.4683332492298));
#2943=VERTEX_POINT('',#2942);
#2944=EDGE_CURVE('P1_E641',#2943,#2912,#2941,.T.);
#2945=ORIENTED_EDGE('',*,*,#2944,.F.);
#2946=DIRECTION('',(0.,1.,0.));
#2947=VECTOR('',#2946,1.);
#2948=CARTESIAN_POINT('',(16.0677846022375,11.8022223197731,18.4683332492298));
#2949=LINE('',#2948,#2947);
#2950=EDGE_CURVE('P1_E685',#2943,#2214,#2949,.T.);
#2951=ORIENTED_EDGE('',*,*,#2950,.T.);
#2952=EDGE_LOOP('',(#2936,#2937,#2945,#2951));
#2953=FACE_BOUND('',#2952,.T.);
#2954=ADVANCED_FACE('P1_F976',(#2953),#2935,.F.);
#2955=CARTESIAN_POINT('',(16.0677846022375,11.8022223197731,30.0982672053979));
#2956=DIRECTION('',(1.,0.,0.));
#2957=DIRECTION('',(0.,0.,-1.));
#2958=AXIS2_PLACEMENT_3D('',#2955,#2956,#2957);
#2959=PLANE('',#2958);
#2960=ORIENTED_EDGE('',*,*,#2223,.T.);
#2961=ORIENTED_EDGE('',*,*,#2950,.F.);
#2962=DIRECTION('',(0.,0.,-1.));
#2963=VECTOR('',#2962,1.);
#2964=CARTESIAN_POINT('',(16.0677846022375,11.8022223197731,30.0982672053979));
#2965=LINE('',#2964,#2963);
#2966=CARTESIAN_POINT('',(16.0677846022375,11.8022223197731,19.7683332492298));
#2967=VERTEX_POINT('',#2966);
#2968=EDGE_CURVE('P1_E638',#2967,#2943,#2965,.T.);
#2969=ORIENTED_EDGE('',*,*,#2968,.F.);
#2970=DIRECTION('',(0.,1.,0.));
#2971=VECTOR('',#2970,1.);
#2972=CARTESIAN_POINT('',(16.0677846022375,11.8022223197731,19.7683332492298));
#2973=LINE('',#2972,#2971);
#2974=EDGE_CURVE('P1_E687',#2967,#2222,#2973,.T.);
#2975=ORIENTED_EDGE('',*,*,#2974,.T.);
#2976=EDGE_LOOP('',(#2960,#2961,#2969,#2975));
#2977=FACE_BOUND('',#2976,.T.);
#2978=ADVANCED_FACE('P1_F980',(#2977),#2959,.F.);
#2979=CARTESIAN_POINT('',(151.961726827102,11.8022223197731,19.7683332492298));
#2980=DIRECTION('',(0.,0.,-1.));
#2981=DIRECTION('',(-1.,0.,0.));
#2982=AXIS2_PLACEMENT_3D('',#2979,#2980,#2981);
#2983=PLANE('',#2982);
#2984=ORIENTED_EDGE('',*,*,#2231,.T.);
#2985=ORIENTED_EDGE('',*,*,#2974,.F.);
#2986=DIRECTION('',(-1.,0.,0.));
#2987=VECTOR('',#2986,1.);
#2988=CARTESIAN_POINT('',(151.961726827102,11.8022223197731,19.7683332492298));
#2989=LINE('',#2988,#2987);
#2990=CARTESIAN_POINT('',(17.0677846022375,11.8022223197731,19.7683332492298));
#2991=VERTEX_POINT('',#2990);
#2992=EDGE_CURVE('P1_E635',#2991,#2967,#2989,.T.);
#2993=ORIENTED_EDGE('',*,*,#2992,.F.);
#2994=DIRECTION('',(0.,1.,0.));
#2995=VECTOR('',#2994,1.);
#2996=CARTESIAN_POINT('',(17.0677846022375,11.8022223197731,19.7683332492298));
#2997=LINE('',#2996,#2995);
#2998=EDGE_CURVE('P1_E689',#2991,#2230,#2997,.T.);
#2999=ORIENTED_EDGE('',*,*,#2998,.T.);
#3000=EDGE_LOOP('',(#2984,#2985,#2993,#2999));
#3001=FACE_BOUND('',#3000,.T.);
#3002=ADVANCED_FACE('P1_F984',(#3001),#2983,.F.);
#3003=CARTESIAN_POINT('',(17.0677846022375,11.8022223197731,30.0982672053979));
#3004=DIRECTION('',(1.,0.,0.));
#3005=DIRECTION('',(0.,0.,-1.));
#3006=AXIS2_PLACEMENT_3D('',#3003,#3004,#3005);
#3007=PLANE('',#3006);
#3008=ORIENTED_EDGE('',*,*,#2239,.F.);
#3009=ORIENTED_EDGE('',*,*,#2998,.F.);
#3010=DIRECTION('',(0.,0.,-1.));
#3011=VECTOR('',#3010,1.);
#3012=CARTESIAN_POINT('',(17.0677846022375,11.8022223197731,30.0982672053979));
#3013=LINE('',#3012,#3011);
#3014=CARTESIAN_POINT('',(17.0677846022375,11.8022223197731,18.7683332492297));
#3015=VERTEX_POINT('',#3014);
#3016=EDGE_CURVE('P1_E633',#2991,#3015,#3013,.T.);
#3017=ORIENTED_EDGE('',*,*,#3016,.T.);
#3018=DIRECTION('',(0.,1.,0.));
#3019=VECTOR('',#3018,1.);
#3020=CARTESIAN_POINT('',(17.0677846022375,11.8022223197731,18.7683332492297));
#3021=LINE('',#3020,#3019);
#3022=EDGE_CURVE('P1_E691',#3015,#2238,#3021,.T.);
#3023=ORIENTED_EDGE('',*,*,#3022,.T.);
#3024=EDGE_LOOP('',(#3008,#3009,#3017,#3023));
#3025=FACE_BOUND('',#3024,.T.);
#3026=ADVANCED_FACE('P1_F988',(#3025),#3007,.T.);
#3027=CARTESIAN_POINT('',(151.961726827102,11.8022223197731,18.7683332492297));
#3028=DIRECTION('',(0.,0.,-1.));
#3029=DIRECTION('',(-1.,0.,0.));
#3030=AXIS2_PLACEMENT_3D('',#3027,#3028,#3029);
#3031=PLANE('',#3030);
#3032=ORIENTED_EDGE('',*,*,#2247,.T.);
#3033=ORIENTED_EDGE('',*,*,#3022,.F.);
#3034=DIRECTION('',(-1.,0.,0.));
#3035=VECTOR('',#3034,1.);
#3036=CARTESIAN_POINT('',(151.961726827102,11.8022223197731,18.7683332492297));
#3037=LINE('',#3036,#3035);
#3038=CARTESIAN_POINT('',(19.0677846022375,11.8022223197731,18.7683332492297));
#3039=VERTEX_POINT('',#3038);
#3040=EDGE_CURVE('P1_E630',#3039,#3015,#3037,.T.);
#3041=ORIENTED_EDGE('',*,*,#3040,.F.);
#3042=DIRECTION('',(0.,1.,0.));
#3043=VECTOR('',#3042,1.);
#3044=CARTESIAN_POINT('',(19.0677846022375,11.8022223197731,18.7683332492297));
#3045=LINE('',#3044,#3043);
#3046=EDGE_CURVE('P1_E693',#3039,#2246,#3045,.T.);
#3047=ORIENTED_EDGE('',*,*,#3046,.T.);
#3048=EDGE_LOOP('',(#3032,#3033,#3041,#3047));
#3049=FACE_BOUND('',#3048,.T.);
#3050=ADVANCED_FACE('P1_F993',(#3049),#3031,.F.);
#3051=CARTESIAN_POINT('',(19.0677846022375,11.8022223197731,30.0982672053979));
#3052=DIRECTION('',(1.,0.,0.));
#3053=DIRECTION('',(0.,0.,-1.));
#3054=AXIS2_PLACEMENT_3D('',#3051,#3052,#3053);
#3055=PLANE('',#3054);
#3056=ORIENTED_EDGE('',*,*,#2255,.T.);
#3057=ORIENTED_EDGE('',*,*,#3046,.F.);
#3058=DIRECTION('',(0.,0.,-1.));
#3059=VECTOR('',#3058,1.);
#3060=CARTESIAN_POINT('',(19.0677846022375,11.8022223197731,30.0982672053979));
#3061=LINE('',#3060,#3059);
#3062=CARTESIAN_POINT('',(19.0677846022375,11.8022223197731,26.7683332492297));
#3063=VERTEX_POINT('',#3062);
#3064=EDGE_CURVE('P1_E627',#3063,#3039,#3061,.T.);
#3065=ORIENTED_EDGE('',*,*,#3064,.F.);
#3066=DIRECTION('',(0.,1.,0.));
#3067=VECTOR('',#3066,1.);
#3068=CARTESIAN_POINT('',(19.0677846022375,11.8022223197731,26.7683332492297));
#3069=LINE('',#3068,#3067);
#3070=EDGE_CURVE('P1_E695',#3063,#2254,#3069,.T.);
#3071=ORIENTED_EDGE('',*,*,#3070,.T.);
#3072=EDGE_LOOP('',(#3056,#3057,#3065,#3071));
#3073=FACE_BOUND('',#3072,.T.);
#3074=ADVANCED_FACE('P1_F997',(#3073),#3055,.F.);
#3075=CARTESIAN_POINT('',(151.961726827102,11.8022223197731,26.7683332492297));
#3076=DIRECTION('',(0.,0.,-1.));
#3077=DIRECTION('',(-1.,0.,0.));
#3078=AXIS2_PLACEMENT_3D('',#3075,#3076,#3077);
#3079=PLANE('',#3078);
#3080=ORIENTED_EDGE('',*,*,#2263,.F.);
#3081=ORIENTED_EDGE('',*,*,#3070,.F.);
#3082=DIRECTION('',(-1.,0.,0.));
#3083=VECTOR('',#3082,1.);
#3084=CARTESIAN_POINT('',(151.961726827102,11.8022223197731,26.7683332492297));
#3085=LINE('',#3084,#3083);
#3086=CARTESIAN_POINT('',(17.0677846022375,11.8022223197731,26.7683332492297));
#3087=VERTEX_POINT('',#3086);
#3088=EDGE_CURVE('P1_E625',#3063,#3087,#3085,.T.);
#3089=ORIENTED_EDGE('',*,*,#3088,.T.);
#3090=DIRECTION('',(0.,1.,0.));
#3091=VECTOR('',#3090,1.);
#3092=CARTESIAN_POINT('',(17.0677846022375,11.8022223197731,26.7683332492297));
#3093=LINE('',#3092,#3091);
#3094=EDGE_CURVE('P1_E697',#3087,#2262,#3093,.T.);
#3095=ORIENTED_EDGE('',*,*,#3094,.T.);
#3096=EDGE_LOOP('',(#3080,#3081,#3089,#3095));
#3097=FACE_BOUND('',#3096,.T.);
#3098=ADVANCED_FACE('P1_F1001',(#3097),#3079,.T.);
#3099=CARTESIAN_POINT('',(17.0677846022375,11.8022223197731,30.0982672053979));
#3100=DIRECTION('',(1.,0.,0.));
#3101=DIRECTION('',(0.,0.,-1.));
#3102=AXIS2_PLACEMENT_3D('',#3099,#3100,#3101);
#3103=PLANE('',#3102);
#3104=ORIENTED_EDGE('',*,*,#2271,.F.);
#3105=ORIENTED_EDGE('',*,*,#3094,.F.);
#3106=DIRECTION('',(0.,0.,-1.));
#3107=VECTOR('',#3106,1.);
#3108=CARTESIAN_POINT('',(17.0677846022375,11.8022223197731,30.0982672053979));
#3109=LINE('',#3108,#3107);
#3110=CARTESIAN_POINT('',(17.0677846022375,11.8022223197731,25.7683332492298));
#3111=VERTEX_POINT('',#3110);
#3112=EDGE_CURVE('P1_E623',#3087,#3111,#3109,.T.);
#3113=ORIENTED_EDGE('',*,*,#3112,.T.);
#3114=DIRECTION('',(0.,1.,0.));
#3115=VECTOR('',#3114,1.);
#3116=CARTESIAN_POINT('',(17.0677846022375,11.8022223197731,25.7683332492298));
#3117=LINE('',#3116,#3115);
#3118=EDGE_CURVE('P1_E699',#3111,#2270,#3117,.T.);
#3119=ORIENTED_EDGE('',*,*,#3118,.T.);
#3120=EDGE_LOOP('',(#3104,#3105,#3113,#3119));
#3121=FACE_BOUND('',#3120,.T.);
#3122=ADVANCED_FACE('P1_F1006',(#3121),#3103,.T.);
#3123=CARTESIAN_POINT('',(151.961726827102,11.8022223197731,25.7683332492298));
#3124=DIRECTION('',(0.,0.,-1.));
#3125=DIRECTION('',(-1.,0.,0.));
#3126=AXIS2_PLACEMENT_3D('',#3123,#3124,#3125);
#3127=PLANE('',#3126);
#3128=ORIENTED_EDGE('',*,*,#2279,.F.);
#3129=ORIENTED_EDGE('',*,*,#3118,.F.);
#3130=DIRECTION('',(-1.,0.,0.));
#3131=VECTOR('',#3130,1.);
#3132=CARTESIAN_POINT('',(151.961726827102,11.8022223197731,25.7683332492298));
#3133=LINE('',#3132,#3131);
#3134=CARTESIAN_POINT('',(16.0677846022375,11.8022223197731,25.7683332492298));
#3135=VERTEX_POINT('',#3134);
#3136=EDGE_CURVE('P1_E621',#3111,#3135,#3133,.T.);
#3137=ORIENTED_EDGE('',*,*,#3136,.T.);
#3138=DIRECTION('',(0.,1.,0.));
#3139=VECTOR('',#3138,1.);
#3140=CARTESIAN_POINT('',(16.0677846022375,11.8022223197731,25.7683332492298));
#3141=LINE('',#3140,#3139);
#3142=EDGE_CURVE('P1_E701',#3135,#2278,#3141,.T.);
#3143=ORIENTED_EDGE('',*,*,#3142,.T.);
#3144=EDGE_LOOP('',(#3128,#3129,#3137,#3143));
#3145=FACE_BOUND('',#3144,.T.);
#3146=ADVANCED_FACE('P1_F1011',(#3145),#3127,.T.);
#3147=CARTESIAN_POINT('',(16.0677846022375,11.8022223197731,30.0982672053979));
#3148=DIRECTION('',(-1.,0.,0.));
#3149=DIRECTION('',(0.,0.,1.));
#3150=AXIS2_PLACEMENT_3D('',#3147,#3148,#3149);
#3151=PLANE('',#3150);
#3152=ORIENTED_EDGE('',*,*,#2287,.F.);
#3153=ORIENTED_EDGE('',*,*,#3142,.F.);
#3154=DIRECTION('',(0.,0.,1.));
#3155=VECTOR('',#3154,1.);
#3156=CARTESIAN_POINT('',(16.0677846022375,11.8022223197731,30.0982672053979));
#3157=LINE('',#3156,#3155);
#3158=CARTESIAN_POINT('',(16.0677846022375,11.8022223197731,27.0683332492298));
#3159=VERTEX_POINT('',#3158);
#3160=EDGE_CURVE('P1_E619',#3135,#3159,#3157,.T.);
#3161=ORIENTED_EDGE('',*,*,#3160,.T.);
#3162=DIRECTION('',(0.,1.,0.));
#3163=VECTOR('',#3162,1.);
#3164=CARTESIAN_POINT('',(16.0677846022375,11.8022223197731,27.0683332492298));
#3165=LINE('',#3164,#3163);
#3166=EDGE_CURVE('P1_E703',#3159,#2286,#3165,.T.);
#3167=ORIENTED_EDGE('',*,*,#3166,.T.);
#3168=EDGE_LOOP('',(#3152,#3153,#3161,#3167));
#3169=FACE_BOUND('',#3168,.T.);
#3170=ADVANCED_FACE('P1_F1016',(#3169),#3151,.T.);
#3171=CARTESIAN_POINT('',(151.961726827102,11.8022223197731,27.0683332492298));
#3172=DIRECTION('',(0.,0.,-1.));
#3173=DIRECTION('',(-1.,0.,0.));
#3174=AXIS2_PLACEMENT_3D('',#3171,#3172,#3173);
#3175=PLANE('',#3174);
#3176=ORIENTED_EDGE('',*,*,#2293,.F.);
#3177=ORIENTED_EDGE('',*,*,#3166,.F.);
#3178=DIRECTION('',(-1.,0.,0.));
#3179=VECTOR('',#3178,1.);
#3180=CARTESIAN_POINT('',(151.961726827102,11.8022223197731,27.0683332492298));
#3181=LINE('',#3180,#3179);
#3182=EDGE_CURVE('P1_E615',#3159,#2145,#3181,.T.);
#3183=ORIENTED_EDGE('',*,*,#3182,.T.);
#3184=ORIENTED_EDGE('',*,*,#2146,.T.);
#3185=EDGE_LOOP('',(#3176,#3177,#3183,#3184));
#3186=FACE_BOUND('',#3185,.T.);
#3187=ADVANCED_FACE('P1_F1020',(#3186),#3175,.T.);
#3188=CARTESIAN_POINT('',(151.961726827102,11.8022223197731,30.0982672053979));
#3189=DIRECTION('',(0.,1.,0.));
#3190=DIRECTION('',(0.,0.,1.));
#3191=AXIS2_PLACEMENT_3D('',#3188,#3189,#3190);
#3192=PLANE('',#3191);
#3193=ORIENTED_EDGE('',*,*,#2154,.F.);
#3194=ORIENTED_EDGE('',*,*,#3182,.F.);
#3195=ORIENTED_EDGE('',*,*,#3160,.F.);
#3196=ORIENTED_EDGE('',*,*,#3136,.F.);
#3197=ORIENTED_EDGE('',*,*,#3112,.F.);
#3198=ORIENTED_EDGE('',*,*,#3088,.F.);
#3199=ORIENTED_EDGE('',*,*,#3064,.T.);
#3200=ORIENTED_EDGE('',*,*,#3040,.T.);
#3201=ORIENTED_EDGE('',*,*,#3016,.F.);
#3202=ORIENTED_EDGE('',*,*,#2992,.T.);
#3203=ORIENTED_EDGE('',*,*,#2968,.T.);
#3204=ORIENTED_EDGE('',*,*,#2944,.T.);
#3205=ORIENTED_EDGE('',*,*,#2913,.F.);
#3206=EDGE_CURVE('P1_E616',#2153,#2908,#2151,.T.);
#3207=ORIENTED_EDGE('',*,*,#3206,.F.);
#3208=EDGE_LOOP('',(#3193,#3194,#3195,#3196,#3197,#3198,#3199,#3200,#3201,#3202,#3203,#3204,
#3205,#3207));
#3209=FACE_BOUND('',#3208,.T.);
#3210=ADVANCED_FACE('P1_F1027',(#3209),#3192,.T.);
#3211=CARTESIAN_POINT('',(15.0677846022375,18.1022223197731,25.2683332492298));
#3212=DIRECTION('',(0.,0.,1.));
#3213=DIRECTION('',(1.,0.,0.));
#3214=AXIS2_PLACEMENT_3D('',#3211,#3212,#3213);
#3215=PLANE('',#3214);
#3216=ORIENTED_EDGE('',*,*,#2823,.T.);
#3217=ORIENTED_EDGE('',*,*,#2302,.F.);
#3218=ORIENTED_EDGE('',*,*,#2130,.F.);
#3219=DIRECTION('',(-1.,0.,0.));
#3220=VECTOR('',#3219,1.);
#3221=CARTESIAN_POINT('',(15.0677846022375,14.1022223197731,25.2683332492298));
#3222=LINE('',#3221,#3220);
#3223=EDGE_CURVE('P1_E607',#2127,#2822,#3222,.T.);
#3224=ORIENTED_EDGE('',*,*,#3223,.T.);
#3225=EDGE_LOOP('',(#3216,#3217,#3218,#3224));
#3226=FACE_BOUND('',#3225,.T.);
#3227=ADVANCED_FACE('P1_F1036',(#3226),#3215,.F.);
#3228=CARTESIAN_POINT('',(15.0677846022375,14.1022223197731,22.7683332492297));
#3229=DIRECTION('',(-1.,0.,0.));
#3230=DIRECTION('',(0.,0.,1.));
#3231=AXIS2_PLACEMENT_3D('',#3228,#3229,#3230);
#3232=CYLINDRICAL_SURFACE('',#3231,2.5);
#3233=ORIENTED_EDGE('',*,*,#2832,.T.);
#3234=ORIENTED_EDGE('',*,*,#3223,.F.);
#3235=ORIENTED_EDGE('',*,*,#2161,.F.);
#3236=EDGE_CURVE('P1_E593',#2908,#2153,#2160,.T.);
#3237=ORIENTED_EDGE('',*,*,#3236,.F.);
#3238=ORIENTED_EDGE('',*,*,#2909,.F.);
#3239=DIRECTION('',(-1.,0.,0.));
#3240=VECTOR('',#3239,1.);
#3241=CARTESIAN_POINT('',(15.0677846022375,14.1022223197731,20.2683332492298));
#3242=LINE('',#3241,#3240);
#3243=EDGE_CURVE('P1_E609',#2906,#2831,#3242,.T.);
#3244=ORIENTED_EDGE('',*,*,#3243,.T.);
#3245=EDGE_LOOP('',(#3233,#3234,#3235,#3237,#3238,#3244));
#3246=FACE_BOUND('',#3245,.T.);
#3247=ADVANCED_FACE('P1_F1033',(#3246),#3232,.F.);
#3248=CARTESIAN_POINT('',(15.0677846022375,14.1022223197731,20.2683332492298));
#3249=DIRECTION('',(0.,0.,-1.));
#3250=DIRECTION('',(0.,1.,0.));
#3251=AXIS2_PLACEMENT_3D('',#3248,#3249,#3250);
#3252=PLANE('',#3251);
#3253=ORIENTED_EDGE('',*,*,#2838,.T.);
#3254=ORIENTED_EDGE('',*,*,#3243,.F.);
#3255=ORIENTED_EDGE('',*,*,#2926,.F.);
#3256=ORIENTED_EDGE('',*,*,#2203,.T.);
#3257=EDGE_LOOP('',(#3253,#3254,#3255,#3256));
#3258=FACE_BOUND('',#3257,.T.);
#3259=ADVANCED_FACE('P1_F967',(#3258),#3252,.F.);
#3260=CARTESIAN_POINT('',(15.0677846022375,14.1022223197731,22.7683332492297));
#3261=DIRECTION('',(-1.,0.,0.));
#3262=DIRECTION('',(0.,0.,1.));
#3263=AXIS2_PLACEMENT_3D('',#3260,#3261,#3262);
#3264=PLANE('',#3263);
#3265=ORIENTED_EDGE('',*,*,#3236,.T.);
#3266=ORIENTED_EDGE('',*,*,#3206,.T.);
#3267=EDGE_LOOP('',(#3265,#3266));
#3268=FACE_BOUND('',#3267,.T.);
#3269=ADVANCED_FACE('P1_F1030',(#3268),#3264,.T.);
#3270=CARTESIAN_POINT('',(151.961726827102,9.10222231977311,18.7683332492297));
#3271=DIRECTION('',(0.,0.,-1.));
#3272=DIRECTION('',(-1.,0.,0.));
#3273=AXIS2_PLACEMENT_3D('',#3270,#3271,#3272);
#3274=PLANE('',#3273);
#3275=ORIENTED_EDGE('',*,*,#2629,.T.);
#3276=DIRECTION('',(0.,1.,0.));
#3277=VECTOR('',#3276,1.);
#3278=CARTESIAN_POINT('',(-4.23221539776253,9.10222231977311,18.7683332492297));
#3279=LINE('',#3278,#3277);
#3280=CARTESIAN_POINT('',(-4.23221539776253,9.10222231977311,18.7683332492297));
#3281=VERTEX_POINT('',#3280);
#3282=EDGE_CURVE('P1_E523',#3281,#2620,#3279,.T.);
#3283=ORIENTED_EDGE('',*,*,#3282,.F.);
#3284=DIRECTION('',(-1.,0.,0.));
#3285=VECTOR('',#3284,1.);
#3286=CARTESIAN_POINT('',(151.961726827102,9.10222231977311,18.7683332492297));
#3287=LINE('',#3286,#3285);
#3288=CARTESIAN_POINT('',(-1.93221539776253,9.10222231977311,18.7683332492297));
#3289=VERTEX_POINT('',#3288);
#3290=EDGE_CURVE('P1_E492',#3289,#3281,#3287,.T.);
#3291=ORIENTED_EDGE('',*,*,#3290,.F.);
#3292=DIRECTION('',(0.,1.,0.));
#3293=VECTOR('',#3292,1.);
#3294=CARTESIAN_POINT('',(-1.93221539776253,9.10222231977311,18.7683332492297));
#3295=LINE('',#3294,#3293);
#3296=EDGE_CURVE('P1_E558',#3289,#2628,#3295,.T.);
#3297=ORIENTED_EDGE('',*,*,#3296,.T.);
#3298=EDGE_LOOP('',(#3275,#3283,#3291,#3297));
#3299=FACE_BOUND('',#3298,.T.);
#3300=ADVANCED_FACE('P1_F1250',(#3299),#3274,.F.);
#3301=CARTESIAN_POINT('',(-1.93221539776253,9.10222231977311,30.0982672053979));
#3302=DIRECTION('',(1.,0.,0.));
#3303=DIRECTION('',(0.,0.,-1.));
#3304=AXIS2_PLACEMENT_3D('',#3301,#3302,#3303);
#3305=PLANE('',#3304);
#3306=ORIENTED_EDGE('',*,*,#2637,.T.);
#3307=ORIENTED_EDGE('',*,*,#3296,.F.);
#3308=DIRECTION('',(0.,0.,-1.));
#3309=VECTOR('',#3308,1.);
#3310=CARTESIAN_POINT('',(-1.93221539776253,9.10222231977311,30.0982672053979));
#3311=LINE('',#3310,#3309);
#3312=CARTESIAN_POINT('',(-1.93221539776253,9.10222231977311,19.7683332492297));
#3313=VERTEX_POINT('',#3312);
#3314=EDGE_CURVE('P1_E520',#3313,#3289,#3311,.T.);
#3315=ORIENTED_EDGE('',*,*,#3314,.F.);
#3316=DIRECTION('',(0.,1.,0.));
#3317=VECTOR('',#3316,1.);
#3318=CARTESIAN_POINT('',(-1.93221539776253,9.10222231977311,19.7683332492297));
#3319=LINE('',#3318,#3317);
#3320=EDGE_CURVE('P1_E561',#3313,#2636,#3319,.T.);
#3321=ORIENTED_EDGE('',*,*,#3320,.T.);
#3322=EDGE_LOOP('',(#3306,#3307,#3315,#3321));
#3323=FACE_BOUND('',#3322,.T.);
#3324=ADVANCED_FACE('P1_F1259',(#3323),#3305,.F.);
#3325=CARTESIAN_POINT('',(151.961726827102,9.10222231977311,19.7683332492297));
#3326=DIRECTION('',(0.,0.,-1.));
#3327=DIRECTION('',(-1.,0.,0.));
#3328=AXIS2_PLACEMENT_3D('',#3325,#3326,#3327);
#3329=PLANE('',#3328);
#3330=ORIENTED_EDGE('',*,*,#2645,.T.);
#3331=ORIENTED_EDGE('',*,*,#3320,.F.);
#3332=DIRECTION('',(-1.,0.,0.));
#3333=VECTOR('',#3332,1.);
#3334=CARTESIAN_POINT('',(151.961726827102,9.10222231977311,19.7683332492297));
#3335=LINE('',#3334,#3333);
#3336=CARTESIAN_POINT('',(-0.932215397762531,9.10222231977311,19.7683332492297));
#3337=VERTEX_POINT('',#3336);
#3338=EDGE_CURVE('P1_E517',#3337,#3313,#3335,.T.);
#3339=ORIENTED_EDGE('',*,*,#3338,.F.);
#3340=DIRECTION('',(0.,1.,0.));
#3341=VECTOR('',#3340,1.);
#3342=CARTESIAN_POINT('',(-0.932215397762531,9.10222231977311,19.7683332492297));
#3343=LINE('',#3342,#3341);
#3344=EDGE_CURVE('P1_E563',#3337,#2644,#3343,.T.);
#3345=ORIENTED_EDGE('',*,*,#3344,.T.);
#3346=EDGE_LOOP('',(#3330,#3331,#3339,#3345));
#3347=FACE_BOUND('',#3346,.T.);
#3348=ADVANCED_FACE('P1_F1269',(#3347),#3329,.F.);
#3349=CARTESIAN_POINT('',(-0.932215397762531,9.10222231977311,30.0982672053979));
#3350=DIRECTION('',(-1.,0.,0.));
#3351=DIRECTION('',(0.,0.,1.));
#3352=AXIS2_PLACEMENT_3D('',#3349,#3350,#3351);
#3353=PLANE('',#3352);
#3354=ORIENTED_EDGE('',*,*,#2653,.T.);
#3355=ORIENTED_EDGE('',*,*,#3344,.F.);
#3356=DIRECTION('',(0.,0.,1.));
#3357=VECTOR('',#3356,1.);
#3358=CARTESIAN_POINT('',(-0.932215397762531,9.10222231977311,30.0982672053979));
#3359=LINE('',#3358,#3357);
#3360=CARTESIAN_POINT('',(-0.932215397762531,9.10222231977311,18.4683332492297));
#3361=VERTEX_POINT('',#3360);
#3362=EDGE_CURVE('P1_E514',#3361,#3337,#3359,.T.);
#3363=ORIENTED_EDGE('',*,*,#3362,.F.);
#3364=DIRECTION('',(0.,1.,0.));
#3365=VECTOR('',#3364,1.);
#3366=CARTESIAN_POINT('',(-0.932215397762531,9.10222231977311,18.4683332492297));
#3367=LINE('',#3366,#3365);
#3368=EDGE_CURVE('P1_E565',#3361,#2652,#3367,.T.);
#3369=ORIENTED_EDGE('',*,*,#3368,.T.);
#3370=EDGE_LOOP('',(#3354,#3355,#3363,#3369));
#3371=FACE_BOUND('',#3370,.T.);
#3372=ADVANCED_FACE('P1_F1279',(#3371),#3353,.F.);
#3373=CARTESIAN_POINT('',(151.961726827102,9.10222231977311,18.4683332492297));
#3374=DIRECTION('',(0.,0.,-1.));
#3375=DIRECTION('',(-1.,0.,0.));
#3376=AXIS2_PLACEMENT_3D('',#3373,#3374,#3375);
#3377=PLANE('',#3376);
#3378=ORIENTED_EDGE('',*,*,#2661,.T.);
#3379=ORIENTED_EDGE('',*,*,#3368,.F.);
#3380=DIRECTION('',(-1.,0.,0.));
#3381=VECTOR('',#3380,1.);
#3382=CARTESIAN_POINT('',(151.961726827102,9.10222231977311,18.4683332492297));
#3383=LINE('',#3382,#3381);
#3384=CARTESIAN_POINT('',(0.0677846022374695,9.10222231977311,18.4683332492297));
#3385=VERTEX_POINT('',#3384);
#3386=EDGE_CURVE('P1_E511',#3385,#3361,#3383,.T.);
#3387=ORIENTED_EDGE('',*,*,#3386,.F.);
#3388=DIRECTION('',(0.,1.,0.));
#3389=VECTOR('',#3388,1.);
#3390=CARTESIAN_POINT('',(0.0677846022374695,9.10222231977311,18.4683332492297));
#3391=LINE('',#3390,#3389);
#3392=EDGE_CURVE('P1_E567',#3385,#2660,#3391,.T.);
#3393=ORIENTED_EDGE('',*,*,#3392,.T.);
#3394=EDGE_LOOP('',(#3378,#3379,#3387,#3393));
#3395=FACE_BOUND('',#3394,.T.);
#3396=ADVANCED_FACE('P1_F1289',(#3395),#3377,.F.);
#3397=CARTESIAN_POINT('',(0.0677846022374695,9.10222231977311,30.0982672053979));
#3398=DIRECTION('',(-1.,0.,0.));
#3399=DIRECTION('',(0.,0.,1.));
#3400=AXIS2_PLACEMENT_3D('',#3397,#3398,#3399);
#3401=PLANE('',#3400);
#3402=DIRECTION('',(0.,1.,0.));
#3403=VECTOR('',#3402,1.);
#3404=CARTESIAN_POINT('',(0.0677846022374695,9.10222231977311,25.2683332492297));
#3405=LINE('',#3404,#3403);
#3406=CARTESIAN_POINT('',(0.0677846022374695,14.1022223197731,25.2683332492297));
#3407=VERTEX_POINT('',#3406);
#3408=EDGE_CURVE('P1_E761',#3407,#2564,#3405,.T.);
#3409=ORIENTED_EDGE('',*,*,#3408,.F.);
#3410=CARTESIAN_POINT('',(0.0677846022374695,14.1022223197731,22.7683332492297));
#3411=DIRECTION('',(-1.,0.,0.));
#3412=DIRECTION('',(0.,0.,1.));
#3413=AXIS2_PLACEMENT_3D('',#3410,#3411,#3412);
#3414=CIRCLE('',#3413,2.5);
#3415=CARTESIAN_POINT('',(0.0677846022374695,14.1022223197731,20.2683332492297));
#3416=VERTEX_POINT('',#3415);
#3417=EDGE_CURVE('P1_E759',#3416,#3407,#3414,.T.);
#3418=ORIENTED_EDGE('',*,*,#3417,.F.);
#3419=DIRECTION('',(0.,-1.,0.));
#3420=VECTOR('',#3419,1.);
#3421=CARTESIAN_POINT('',(0.0677846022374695,9.10222231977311,20.2683332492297));
#3422=LINE('',#3421,#3420);
#3423=EDGE_CURVE('P1_E748',#2664,#3416,#3422,.T.);
#3424=ORIENTED_EDGE('',*,*,#3423,.F.);
#3425=ORIENTED_EDGE('',*,*,#2665,.F.);
#3426=ORIENTED_EDGE('',*,*,#3392,.F.);
#3427=DIRECTION('',(0.,0.,1.));
#3428=VECTOR('',#3427,1.);
#3429=CARTESIAN_POINT('',(0.0677846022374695,9.10222231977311,30.0982672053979));
#3430=LINE('',#3429,#3428);
#3431=CARTESIAN_POINT('',(0.0677846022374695,9.10222231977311,27.0683332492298));
#3432=VERTEX_POINT('',#3431);
#3433=EDGE_CURVE('P1_E509',#3385,#3432,#3430,.T.);
#3434=ORIENTED_EDGE('',*,*,#3433,.T.);
#3435=DIRECTION('',(0.,1.,0.));
#3436=VECTOR('',#3435,1.);
#3437=CARTESIAN_POINT('',(0.0677846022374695,9.10222231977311,27.0683332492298));
#3438=LINE('',#3437,#3436);
#3439=EDGE_CURVE('P1_E569',#3432,#2572,#3438,.T.);
#3440=ORIENTED_EDGE('',*,*,#3439,.T.);
#3441=ORIENTED_EDGE('',*,*,#2573,.F.);
#3442=EDGE_LOOP('',(#3409,#3418,#3424,#3425,#3426,#3434,#3440,#3441));
#3443=FACE_BOUND('',#3442,.T.);
#3444=ADVANCED_FACE('P1_F1299',(#3443),#3401,.T.);
#3445=CARTESIAN_POINT('',(151.961726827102,9.10222231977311,27.0683332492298));
#3446=DIRECTION('',(0.,0.,-1.));
#3447=DIRECTION('',(-1.,0.,0.));
#3448=AXIS2_PLACEMENT_3D('',#3445,#3446,#3447);
#3449=PLANE('',#3448);
#3450=ORIENTED_EDGE('',*,*,#2581,.F.);
#3451=ORIENTED_EDGE('',*,*,#3439,.F.);
#3452=DIRECTION('',(-1.,0.,0.));
#3453=VECTOR('',#3452,1.);
#3454=CARTESIAN_POINT('',(151.961726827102,9.10222231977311,27.0683332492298));
#3455=LINE('',#3454,#3453);
#3456=CARTESIAN_POINT('',(-0.932215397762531,9.10222231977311,27.0683332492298));
#3457=VERTEX_POINT('',#3456);
#3458=EDGE_CURVE('P1_E507',#3432,#3457,#3455,.T.);
#3459=ORIENTED_EDGE('',*,*,#3458,.T.);
#3460=DIRECTION('',(0.,1.,0.));
#3461=VECTOR('',#3460,1.);
#3462=CARTESIAN_POINT('',(-0.932215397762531,9.10222231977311,27.0683332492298));
#3463=LINE('',#3462,#3461);
#3464=EDGE_CURVE('P1_E572',#3457,#2580,#3463,.T.);
#3465=ORIENTED_EDGE('',*,*,#3464,.T.);
#3466=EDGE_LOOP('',(#3450,#3451,#3459,#3465));
#3467=FACE_BOUND('',#3466,.T.);
#3468=ADVANCED_FACE('P1_F1309',(#3467),#3449,.T.);
#3469=CARTESIAN_POINT('',(-0.932215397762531,9.10222231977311,30.0982672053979));
#3470=DIRECTION('',(1.,0.,0.));
#3471=DIRECTION('',(0.,0.,-1.));
#3472=AXIS2_PLACEMENT_3D('',#3469,#3470,#3471);
#3473=PLANE('',#3472);
#3474=ORIENTED_EDGE('',*,*,#2589,.F.);
#3475=ORIENTED_EDGE('',*,*,#3464,.F.);
#3476=DIRECTION('',(0.,0.,-1.));
#3477=VECTOR('',#3476,1.);
#3478=CARTESIAN_POINT('',(-0.932215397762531,9.10222231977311,30.0982672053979));
#3479=LINE('',#3478,#3477);
#3480=CARTESIAN_POINT('',(-0.932215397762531,9.10222231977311,25.7683332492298));
#3481=VERTEX_POINT('',#3480);
#3482=EDGE_CURVE('P1_E505',#3457,#3481,#3479,.T.);
#3483=ORIENTED_EDGE('',*,*,#3482,.T.);
#3484=DIRECTION('',(0.,1.,0.));
#3485=VECTOR('',#3484,1.);
#3486=CARTESIAN_POINT('',(-0.932215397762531,9.10222231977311,25.7683332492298));
#3487=LINE('',#3486,#3485);
#3488=EDGE_CURVE('P1_E574',#3481,#2588,#3487,.T.);
#3489=ORIENTED_EDGE('',*,*,#3488,.T.);
#3490=EDGE_LOOP('',(#3474,#3475,#3483,#3489));
#3491=FACE_BOUND('',#3490,.T.);
#3492=ADVANCED_FACE('P1_F1319',(#3491),#3473,.T.);
#3493=CARTESIAN_POINT('',(151.961726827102,9.10222231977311,25.7683332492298));
#3494=DIRECTION('',(0.,0.,-1.));
#3495=DIRECTION('',(-1.,0.,0.));
#3496=AXIS2_PLACEMENT_3D('',#3493,#3494,#3495);
#3497=PLANE('',#3496);
#3498=ORIENTED_EDGE('',*,*,#2597,.F.);
#3499=ORIENTED_EDGE('',*,*,#3488,.F.);
#3500=DIRECTION('',(-1.,0.,0.));
#3501=VECTOR('',#3500,1.);
#3502=CARTESIAN_POINT('',(151.961726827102,9.10222231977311,25.7683332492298));
#3503=LINE('',#3502,#3501);
#3504=CARTESIAN_POINT('',(-1.93221539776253,9.10222231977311,25.7683332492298));
#3505=VERTEX_POINT('',#3504);
#3506=EDGE_CURVE('P1_E503',#3481,#3505,#3503,.T.);
#3507=ORIENTED_EDGE('',*,*,#3506,.T.);
#3508=DIRECTION('',(0.,1.,0.));
#3509=VECTOR('',#3508,1.);
#3510=CARTESIAN_POINT('',(-1.93221539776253,9.10222231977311,25.7683332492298));
#3511=LINE('',#3510,#3509);
#3512=EDGE_CURVE('P1_E576',#3505,#2596,#3511,.T.);
#3513=ORIENTED_EDGE('',*,*,#3512,.T.);
#3514=EDGE_LOOP('',(#3498,#3499,#3507,#3513));
#3515=FACE_BOUND('',#3514,.T.);
#3516=ADVANCED_FACE('P1_F1329',(#3515),#3497,.T.);
#3517=CARTESIAN_POINT('',(-1.93221539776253,9.10222231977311,30.0982672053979));
#3518=DIRECTION('',(-1.,0.,0.));
#3519=DIRECTION('',(0.,0.,1.));
#3520=AXIS2_PLACEMENT_3D('',#3517,#3518,#3519);
#3521=PLANE('',#3520);
#3522=ORIENTED_EDGE('',*,*,#2605,.F.);
#3523=ORIENTED_EDGE('',*,*,#3512,.F.);
#3524=DIRECTION('',(0.,0.,1.));
#3525=VECTOR('',#3524,1.);
#3526=CARTESIAN_POINT('',(-1.93221539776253,9.10222231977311,30.0982672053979));
#3527=LINE('',#3526,#3525);
#3528=CARTESIAN_POINT('',(-1.93221539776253,9.10222231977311,26.7683332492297));
#3529=VERTEX_POINT('',#3528);
#3530=EDGE_CURVE('P1_E501',#3505,#3529,#3527,.T.);
#3531=ORIENTED_EDGE('',*,*,#3530,.T.);
#3532=DIRECTION('',(0.,1.,0.));
#3533=VECTOR('',#3532,1.);
#3534=CARTESIAN_POINT('',(-1.93221539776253,9.10222231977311,26.7683332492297));
#3535=LINE('',#3534,#3533);
#3536=EDGE_CURVE('P1_E578',#3529,#2604,#3535,.T.);
#3537=ORIENTED_EDGE('',*,*,#3536,.T.);
#3538=EDGE_LOOP('',(#3522,#3523,#3531,#3537));
#3539=FACE_BOUND('',#3538,.T.);
#3540=ADVANCED_FACE('P1_F1339',(#3539),#3521,.T.);
#3541=CARTESIAN_POINT('',(151.961726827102,9.10222231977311,26.7683332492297));
#3542=DIRECTION('',(0.,0.,-1.));
#3543=DIRECTION('',(-1.,0.,0.));
#3544=AXIS2_PLACEMENT_3D('',#3541,#3542,#3543);
#3545=PLANE('',#3544);
#3546=ORIENTED_EDGE('',*,*,#2613,.F.);
#3547=ORIENTED_EDGE('',*,*,#3536,.F.);
#3548=DIRECTION('',(-1.,0.,0.));
#3549=VECTOR('',#3548,1.);
#3550=CARTESIAN_POINT('',(151.961726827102,9.10222231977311,26.7683332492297));
#3551=LINE('',#3550,#3549);
#3552=CARTESIAN_POINT('',(-4.23221539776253,9.10222231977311,26.7683332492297));
#3553=VERTEX_POINT('',#3552);
#3554=EDGE_CURVE('P1_E499',#3529,#3553,#3551,.T.);
#3555=ORIENTED_EDGE('',*,*,#3554,.T.);
#3556=DIRECTION('',(0.,1.,0.));
#3557=VECTOR('',#3556,1.);
#3558=CARTESIAN_POINT('',(-4.23221539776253,9.10222231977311,26.7683332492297));
#3559=LINE('',#3558,#3557);
#3560=EDGE_CURVE('P1_E580',#3553,#2612,#3559,.T.);
#3561=ORIENTED_EDGE('',*,*,#3560,.T.);
#3562=EDGE_LOOP('',(#3546,#3547,#3555,#3561));
#3563=FACE_BOUND('',#3562,.T.);
#3564=ADVANCED_FACE('P1_F1349',(#3563),#3545,.T.);
#3565=CARTESIAN_POINT('',(-4.23221539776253,9.10222231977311,30.0982672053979));
#3566=DIRECTION('',(-1.,0.,0.));
#3567=DIRECTION('',(0.,0.,1.));
#3568=AXIS2_PLACEMENT_3D('',#3565,#3566,#3567);
#3569=PLANE('',#3568);
#3570=ORIENTED_EDGE('',*,*,#2621,.T.);
#3571=ORIENTED_EDGE('',*,*,#3560,.F.);
#3572=DIRECTION('',(0.,0.,1.));
#3573=VECTOR('',#3572,1.);
#3574=CARTESIAN_POINT('',(-4.23221539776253,9.10222231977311,30.0982672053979));
#3575=LINE('',#3574,#3573);
#3576=EDGE_CURVE('P1_E495',#3281,#3553,#3575,.T.);
#3577=ORIENTED_EDGE('',*,*,#3576,.F.);
#3578=ORIENTED_EDGE('',*,*,#3282,.T.);
#3579=EDGE_LOOP('',(#3570,#3571,#3577,#3578));
#3580=FACE_BOUND('',#3579,.T.);
#3581=ADVANCED_FACE('P1_F1359',(#3580),#3569,.F.);
#3582=CARTESIAN_POINT('',(151.961726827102,9.10222231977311,30.0982672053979));
#3583=DIRECTION('',(0.,1.,0.));
#3584=DIRECTION('',(0.,0.,1.));
#3585=AXIS2_PLACEMENT_3D('',#3582,#3583,#3584);
#3586=PLANE('',#3585);
#3587=ORIENTED_EDGE('',*,*,#3290,.T.);
#3588=ORIENTED_EDGE('',*,*,#3576,.T.);
#3589=ORIENTED_EDGE('',*,*,#3554,.F.);
#3590=ORIENTED_EDGE('',*,*,#3530,.F.);
#3591=ORIENTED_EDGE('',*,*,#3506,.F.);
#3592=ORIENTED_EDGE('',*,*,#3482,.F.);
#3593=ORIENTED_EDGE('',*,*,#3458,.F.);
#3594=ORIENTED_EDGE('',*,*,#3433,.F.);
#3595=ORIENTED_EDGE('',*,*,#3386,.T.);
#3596=ORIENTED_EDGE('',*,*,#3362,.T.);
#3597=ORIENTED_EDGE('',*,*,#3338,.T.);
#3598=ORIENTED_EDGE('',*,*,#3314,.T.);
#3599=EDGE_LOOP('',(#3587,#3588,#3589,#3590,#3591,#3592,#3593,#3594,#3595,#3596,#3597,#3598));
#3600=FACE_BOUND('',#3599,.T.);
#3601=ADVANCED_FACE('P1_F1369',(#3600),#3586,.T.);
#3602=CARTESIAN_POINT('',(-0.232215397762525,14.1022223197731,22.7683332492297));
#3603=DIRECTION('',(1.,0.,0.));
#3604=DIRECTION('',(0.,0.,-1.));
#3605=AXIS2_PLACEMENT_3D('',#3602,#3603,#3604);
#3606=CYLINDRICAL_SURFACE('',#3605,2.5);
#3607=ORIENTED_EDGE('',*,*,#3417,.T.);
#3608=DIRECTION('',(1.,0.,0.));
#3609=VECTOR('',#3608,1.);
#3610=CARTESIAN_POINT('',(-0.232215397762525,14.1022223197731,25.2683332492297));
#3611=LINE('',#3610,#3609);
#3612=EDGE_CURVE('P1_E483',#3407,#2863,#3611,.T.);
#3613=ORIENTED_EDGE('',*,*,#3612,.T.);
#3614=ORIENTED_EDGE('',*,*,#2866,.T.);
#3615=DIRECTION('',(1.,0.,0.));
#3616=VECTOR('',#3615,1.);
#3617=CARTESIAN_POINT('',(-0.232215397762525,14.1022223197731,20.2683332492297));
#3618=LINE('',#3617,#3616);
#3619=EDGE_CURVE('P1_E482',#3416,#2865,#3618,.T.);
#3620=ORIENTED_EDGE('',*,*,#3619,.F.);
#3621=EDGE_LOOP('',(#3607,#3613,#3614,#3620));
#3622=FACE_BOUND('',#3621,.T.);
#3623=ADVANCED_FACE('P1_F1379',(#3622),#3606,.F.);
#3624=CARTESIAN_POINT('',(-0.232215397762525,14.1022223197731,25.2683332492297));
#3625=DIRECTION('',(0.,0.,1.));
#3626=DIRECTION('',(0.,-1.,0.));
#3627=AXIS2_PLACEMENT_3D('',#3624,#3625,#3626);
#3628=PLANE('',#3627);
#3629=ORIENTED_EDGE('',*,*,#3408,.T.);
#3630=ORIENTED_EDGE('',*,*,#2565,.T.);
#3631=ORIENTED_EDGE('',*,*,#2872,.T.);
#3632=ORIENTED_EDGE('',*,*,#3612,.F.);
#3633=EDGE_LOOP('',(#3629,#3630,#3631,#3632));
#3634=FACE_BOUND('',#3633,.T.);
#3635=ADVANCED_FACE('P1_F1389',(#3634),#3628,.F.);
#3636=CARTESIAN_POINT('',(-0.232215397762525,18.1022223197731,20.2683332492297));
#3637=DIRECTION('',(0.,0.,-1.));
#3638=DIRECTION('',(-1.,0.,0.));
#3639=AXIS2_PLACEMENT_3D('',#3636,#3637,#3638);
#3640=PLANE('',#3639);
#3641=ORIENTED_EDGE('',*,*,#3423,.T.);
#3642=ORIENTED_EDGE('',*,*,#3619,.T.);
#3643=ORIENTED_EDGE('',*,*,#2888,.T.);
#3644=ORIENTED_EDGE('',*,*,#2673,.F.);
#3645=EDGE_LOOP('',(#3641,#3642,#3643,#3644));
#3646=FACE_BOUND('',#3645,.T.);
#3647=ADVANCED_FACE('P1_F1399',(#3646),#3640,.F.);
#3648=CARTESIAN_POINT('',(19.5677846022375,17.1022223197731,25.7683332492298));
#3649=DIRECTION('',(0.,0.,1.));
#3650=DIRECTION('',(1.,0.,0.));
#3651=AXIS2_PLACEMENT_3D('',#3648,#3649,#3650);
#3652=PLANE('',#3651);
#3653=ORIENTED_EDGE('',*,*,#2371,.T.);
#3654=ORIENTED_EDGE('',*,*,#2790,.F.);
#3655=DIRECTION('',(0.,-1.,0.));
#3656=VECTOR('',#3655,1.);
#3657=CARTESIAN_POINT('',(19.5677846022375,17.1022223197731,25.7683332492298));
#3658=LINE('',#3657,#3656);
#3659=CARTESIAN_POINT('',(19.5677846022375,17.1022223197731,25.7683332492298));
#3660=VERTEX_POINT('',#3659);
#3661=EDGE_CURVE('P1_E458',#3660,#2783,#3658,.T.);
#3662=ORIENTED_EDGE('',*,*,#3661,.F.);
#3663=DIRECTION('',(1.,0.,0.));
#3664=VECTOR('',#3663,1.);
#3665=CARTESIAN_POINT('',(19.5677846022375,17.1022223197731,25.7683332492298));
#3666=LINE('',#3665,#3664);
#3667=CARTESIAN_POINT('',(20.3677846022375,17.1022223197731,25.7683332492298));
#3668=VERTEX_POINT('',#3667);
#3669=EDGE_CURVE('P1_E468',#3660,#3668,#3666,.T.);
#3670=ORIENTED_EDGE('',*,*,#3669,.T.);
#3671=DIRECTION('',(0.,-1.,0.));
#3672=VECTOR('',#3671,1.);
#3673=CARTESIAN_POINT('',(20.3677846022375,17.1022223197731,25.7683332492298));
#3674=LINE('',#3673,#3672);
#3675=EDGE_CURVE('P1_E437',#2334,#3668,#3674,.T.);
#3676=ORIENTED_EDGE('',*,*,#3675,.F.);
#3677=ORIENTED_EDGE('',*,*,#2335,.T.);
#3678=EDGE_LOOP('',(#3653,#3654,#3662,#3670,#3676,#3677));
#3679=FACE_BOUND('',#3678,.T.);
#3680=ADVANCED_FACE('P1_F930',(#3679),#3652,.F.);
#3681=CARTESIAN_POINT('',(19.5677846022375,17.1022223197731,25.7683332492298));
#3682=DIRECTION('',(0.,1.,0.));
#3683=DIRECTION('',(0.,0.,1.));
#3684=AXIS2_PLACEMENT_3D('',#3681,#3682,#3683);
#3685=PLANE('',#3684);
#3686=DIRECTION('',(1.,0.,0.));
#3687=VECTOR('',#3686,1.);
#3688=CARTESIAN_POINT('',(19.5677846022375,17.1022223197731,19.7683332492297));
#3689=LINE('',#3688,#3687);
#3690=CARTESIAN_POINT('',(19.5677846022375,17.1022223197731,19.7683332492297));
#3691=VERTEX_POINT('',#3690);
#3692=CARTESIAN_POINT('',(20.3677846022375,17.1022223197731,19.7683332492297));
#3693=VERTEX_POINT('',#3692);
#3694=EDGE_CURVE('P1_E471',#3691,#3693,#3689,.T.);
#3695=ORIENTED_EDGE('',*,*,#3694,.T.);
#3696=DIRECTION('',(0.,0.,-1.));
#3697=VECTOR('',#3696,1.);
#3698=CARTESIAN_POINT('',(20.3677846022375,17.1022223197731,25.7683332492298));
#3699=LINE('',#3698,#3697);
#3700=EDGE_CURVE('P1_E439',#3668,#3693,#3699,.T.);
#3701=ORIENTED_EDGE('',*,*,#3700,.F.);
#3702=ORIENTED_EDGE('',*,*,#3669,.F.);
#3703=DIRECTION('',(0.,0.,1.));
#3704=VECTOR('',#3703,1.);
#3705=CARTESIAN_POINT('',(19.5677846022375,17.1022223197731,25.7683332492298));
#3706=LINE('',#3705,#3704);
#3707=EDGE_CURVE('P1_E455',#3691,#3660,#3706,.T.);
#3708=ORIENTED_EDGE('',*,*,#3707,.F.);
#3709=EDGE_LOOP('',(#3695,#3701,#3702,#3708));
#3710=FACE_BOUND('',#3709,.T.);
#3711=ADVANCED_FACE('P1_F943',(#3710),#3685,.F.);
#3712=CARTESIAN_POINT('',(19.5677846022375,17.1022223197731,19.7683332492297));
#3713=DIRECTION('',(0.,0.,-1.));
#3714=DIRECTION('',(-1.,0.,0.));
#3715=AXIS2_PLACEMENT_3D('',#3712,#3713,#3714);
#3716=PLANE('',#3715);
#3717=ORIENTED_EDGE('',*,*,#2112,.T.);
#3718=ORIENTED_EDGE('',*,*,#2349,.F.);
#3719=DIRECTION('',(0.,1.,0.));
#3720=VECTOR('',#3719,1.);
#3721=CARTESIAN_POINT('',(20.3677846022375,17.1022223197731,19.7683332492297));
#3722=LINE('',#3721,#3720);
#3723=EDGE_CURVE('P1_E430',#3693,#2342,#3722,.T.);
#3724=ORIENTED_EDGE('',*,*,#3723,.F.);
#3725=ORIENTED_EDGE('',*,*,#3694,.F.);
#3726=DIRECTION('',(0.,1.,0.));
#3727=VECTOR('',#3726,1.);
#3728=CARTESIAN_POINT('',(19.5677846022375,17.1022223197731,19.7683332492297));
#3729=LINE('',#3728,#3727);
#3730=EDGE_CURVE('P1_E451',#2775,#3691,#3729,.T.);
#3731=ORIENTED_EDGE('',*,*,#3730,.F.);
#3732=ORIENTED_EDGE('',*,*,#2776,.T.);
#3733=EDGE_LOOP('',(#3717,#3718,#3724,#3725,#3731,#3732));
#3734=FACE_BOUND('',#3733,.T.);
#3735=ADVANCED_FACE('P1_F940',(#3734),#3716,.F.);
#3736=CARTESIAN_POINT('',(19.5677846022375,8.10222231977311,30.0982672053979));
#3737=DIRECTION('',(-1.,0.,0.));
#3738=DIRECTION('',(0.,0.,1.));
#3739=AXIS2_PLACEMENT_3D('',#3736,#3737,#3738);
#3740=PLANE('',#3739);
#3741=ORIENTED_EDGE('',*,*,#2784,.T.);
#3742=ORIENTED_EDGE('',*,*,#3730,.T.);
#3743=ORIENTED_EDGE('',*,*,#3707,.T.);
#3744=ORIENTED_EDGE('',*,*,#3661,.T.);
#3745=EDGE_LOOP('',(#3741,#3742,#3743,#3744));
#3746=FACE_BOUND('',#3745,.T.);
#3747=ADVANCED_FACE('P1_F945',(#3746),#3740,.F.);
#3748=CARTESIAN_POINT('',(20.3677846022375,8.10222231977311,30.0982672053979));
#3749=DIRECTION('',(-1.,0.,0.));
#3750=DIRECTION('',(0.,0.,1.));
#3751=AXIS2_PLACEMENT_3D('',#3748,#3749,#3750);
#3752=PLANE('',#3751);
#3753=ORIENTED_EDGE('',*,*,#3723,.T.);
#3754=ORIENTED_EDGE('',*,*,#2343,.T.);
#3755=ORIENTED_EDGE('',*,*,#3675,.T.);
#3756=ORIENTED_EDGE('',*,*,#3700,.T.);
#3757=EDGE_LOOP('',(#3753,#3754,#3755,#3756));
#3758=FACE_BOUND('',#3757,.T.);
#3759=ADVANCED_FACE('P1_F936',(#3758),#3752,.F.);
#3760=CARTESIAN_POINT('',(20.2677846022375,18.1022223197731,26.9683332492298));
#3761=DIRECTION('',(0.,-1.,0.));
#3762=DIRECTION('',(0.,0.,-1.));
#3763=AXIS2_PLACEMENT_3D('',#3760,#3761,#3762);
#3764=CYLINDRICAL_SURFACE('',#3763,0.8);
#3765=ORIENTED_EDGE('',*,*,#2323,.F.);
#3766=ORIENTED_EDGE('',*,*,#2506,.F.);
#3767=ORIENTED_EDGE('',*,*,#2798,.F.);
#3768=ORIENTED_EDGE('',*,*,#2361,.F.);
#3769=EDGE_LOOP('',(#3765,#3766,#3767,#3768));
#3770=FACE_BOUND('',#3769,.T.);
#3771=ADVANCED_FACE('P1_F923',(#3770),#3764,.T.);
#3772=CARTESIAN_POINT('',(20.2677846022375,18.1022223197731,18.5683332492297));
#3773=DIRECTION('',(0.,-1.,0.));
#3774=DIRECTION('',(0.,0.,-1.));
#3775=AXIS2_PLACEMENT_3D('',#3772,#3773,#3774);
#3776=CYLINDRICAL_SURFACE('',#3775,0.8);
#3777=ORIENTED_EDGE('',*,*,#2179,.F.);
#3778=ORIENTED_EDGE('',*,*,#2098,.F.);
#3779=ORIENTED_EDGE('',*,*,#2767,.F.);
#3780=ORIENTED_EDGE('',*,*,#2430,.F.);
#3781=EDGE_LOOP('',(#3777,#3778,#3779,#3780));
#3782=FACE_BOUND('',#3781,.T.);
#3783=ADVANCED_FACE('P1_F954',(#3782),#3776,.T.);
#3784=CARTESIAN_POINT('',(-4.13221539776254,18.1022223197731,26.9683332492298));
#3785=DIRECTION('',(0.,-1.,0.));
#3786=DIRECTION('',(0.,0.,-1.));
#3787=AXIS2_PLACEMENT_3D('',#3784,#3785,#3786);
#3788=CYLINDRICAL_SURFACE('',#3787,0.8);
#3789=ORIENTED_EDGE('',*,*,#2548,.F.);
#3790=ORIENTED_EDGE('',*,*,#2470,.F.);
#3791=ORIENTED_EDGE('',*,*,#2806,.F.);
#3792=ORIENTED_EDGE('',*,*,#2492,.F.);
#3793=EDGE_LOOP('',(#3789,#3790,#3791,#3792));
#3794=FACE_BOUND('',#3793,.T.);
#3795=ADVANCED_FACE('P1_F1048',(#3794),#3788,.T.);
#3796=CARTESIAN_POINT('',(-4.13221539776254,18.1022223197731,18.5683332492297));
#3797=DIRECTION('',(0.,-1.,0.));
#3798=DIRECTION('',(0.,0.,-1.));
#3799=AXIS2_PLACEMENT_3D('',#3796,#3797,#3798);
#3800=CYLINDRICAL_SURFACE('',#3799,0.8);
#3801=ORIENTED_EDGE('',*,*,#2540,.F.);
#3802=ORIENTED_EDGE('',*,*,#2397,.F.);
#3803=ORIENTED_EDGE('',*,*,#2759,.F.);
#3804=ORIENTED_EDGE('',*,*,#2456,.F.);
#3805=EDGE_LOOP('',(#3801,#3802,#3803,#3804));
#3806=FACE_BOUND('',#3805,.T.);
#3807=ADVANCED_FACE('P1_F1055',(#3806),#3800,.T.);
#3808=CARTESIAN_POINT('',(18.3177846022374,3.30222231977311,23.5183332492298));
#3809=DIRECTION('',(1.,0.,0.));
#3810=DIRECTION('',(0.,0.,-1.));
#3811=AXIS2_PLACEMENT_3D('',#3808,#3809,#3810);
#3812=PLANE('',#3811);
#3813=DIRECTION('',(0.,1.,0.));
#3814=VECTOR('',#3813,1.);
#3815=CARTESIAN_POINT('',(18.3177846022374,3.30222231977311,22.0183332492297));
#3816=LINE('',#3815,#3814);
#3817=CARTESIAN_POINT('',(18.3177846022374,4.09594771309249,22.0183332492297));
#3818=VERTEX_POINT('',#3817);
#3819=EDGE_CURVE('P1_E424',#3818,#2708,#3816,.T.);
#3820=ORIENTED_EDGE('',*,*,#3819,.F.);
#3821=CARTESIAN_POINT('',(18.3177846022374,4.09594771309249,22.8183332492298));
#3822=DIRECTION('',(1.,0.,0.));
#3823=DIRECTION('',(0.,0.,-1.));
#3824=AXIS2_PLACEMENT_3D('',#3821,#3822,#3823);
#3825=CIRCLE('',#3824,0.8);
#3826=CARTESIAN_POINT('',(18.3177846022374,3.30222231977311,22.7183332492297));
#3827=VERTEX_POINT('',#3826);
#3828=EDGE_CURVE('P1_E816',#3818,#3827,#3825,.F.);
#3829=ORIENTED_EDGE('',*,*,#3828,.T.);
#3830=CARTESIAN_POINT('',(18.3177846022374,4.10222231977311,22.7183332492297));
#3831=DIRECTION('',(1.,0.,0.));
#3832=DIRECTION('',(0.,0.,-1.));
#3833=AXIS2_PLACEMENT_3D('',#3830,#3831,#3832);
#3834=CIRCLE('',#3833,0.8);
#3835=CARTESIAN_POINT('',(18.3177846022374,4.10222231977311,23.5183332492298));
#3836=VERTEX_POINT('',#3835);
#3837=EDGE_CURVE('P1_E805',#3827,#3836,#3834,.F.);
#3838=ORIENTED_EDGE('',*,*,#3837,.T.);
#3839=DIRECTION('',(0.,1.,0.));
#3840=VECTOR('',#3839,1.);
#3841=CARTESIAN_POINT('',(18.3177846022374,3.30222231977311,23.5183332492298));
#3842=LINE('',#3841,#3840);
#3843=EDGE_CURVE('P1_E834',#3836,#2692,#3842,.T.);
#3844=ORIENTED_EDGE('',*,*,#3843,.T.);
#3845=ORIENTED_EDGE('',*,*,#2715,.T.);
#3846=EDGE_LOOP('',(#3820,#3829,#3838,#3844,#3845));
#3847=FACE_BOUND('',#3846,.T.);
#3848=ADVANCED_FACE('P1_F865',(#3847),#3812,.F.);
#3849=CARTESIAN_POINT('',(18.8177846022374,3.30222231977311,22.0183332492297));
#3850=DIRECTION('',(0.,0.,1.));
#3851=DIRECTION('',(1.,0.,0.));
#3852=AXIS2_PLACEMENT_3D('',#3849,#3850,#3851);
#3853=PLANE('',#3852);
#3854=DIRECTION('',(0.,1.,0.));
#3855=VECTOR('',#3854,1.);
#3856=CARTESIAN_POINT('',(18.8177846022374,3.30222231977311,22.0183332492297));
#3857=LINE('',#3856,#3855);
#3858=CARTESIAN_POINT('',(18.8177846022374,4.09594771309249,22.0183332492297));
#3859=VERTEX_POINT('',#3858);
#3860=EDGE_CURVE('P1_E843',#3859,#2700,#3857,.T.);
#3861=ORIENTED_EDGE('',*,*,#3860,.F.);
#3862=DIRECTION('',(-1.,0.,0.));
#3863=VECTOR('',#3862,1.);
#3864=CARTESIAN_POINT('',(18.8177846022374,4.09594771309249,22.0183332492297));
#3865=LINE('',#3864,#3863);
#3866=EDGE_CURVE('P1_E814',#3859,#3818,#3865,.T.);
#3867=ORIENTED_EDGE('',*,*,#3866,.T.);
#3868=ORIENTED_EDGE('',*,*,#3819,.T.);
#3869=ORIENTED_EDGE('',*,*,#2709,.T.);
#3870=EDGE_LOOP('',(#3861,#3867,#3868,#3869));
#3871=FACE_BOUND('',#3870,.T.);
#3872=ADVANCED_FACE('P1_F857',(#3871),#3853,.F.);
#3873=CARTESIAN_POINT('',(18.8177846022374,3.30222231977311,23.5183332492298));
#3874=DIRECTION('',(-1.,0.,0.));
#3875=DIRECTION('',(0.,0.,1.));
#3876=AXIS2_PLACEMENT_3D('',#3873,#3874,#3875);
#3877=PLANE('',#3876);
#3878=CARTESIAN_POINT('',(18.8177846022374,4.10222231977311,22.7183332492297));
#3879=DIRECTION('',(-1.,0.,0.));
#3880=DIRECTION('',(0.,0.,1.));
#3881=AXIS2_PLACEMENT_3D('',#3878,#3879,#3880);
#3882=CIRCLE('',#3881,0.8);
#3883=CARTESIAN_POINT('',(18.8177846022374,4.10222231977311,23.5183332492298));
#3884=VERTEX_POINT('',#3883);
#3885=CARTESIAN_POINT('',(18.8177846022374,3.30222231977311,22.7183332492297));
#3886=VERTEX_POINT('',#3885);
#3887=EDGE_CURVE('P1_E809',#3884,#3886,#3882,.F.);
#3888=ORIENTED_EDGE('',*,*,#3887,.T.);
#3889=CARTESIAN_POINT('',(18.8177846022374,4.09594771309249,22.8183332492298));
#3890=DIRECTION('',(-1.,0.,0.));
#3891=DIRECTION('',(0.,0.,1.));
#3892=AXIS2_PLACEMENT_3D('',#3889,#3890,#3891);
#3893=CIRCLE('',#3892,0.8);
#3894=EDGE_CURVE('P1_E812',#3886,#3859,#3893,.F.);
#3895=ORIENTED_EDGE('',*,*,#3894,.T.);
#3896=ORIENTED_EDGE('',*,*,#3860,.T.);
#3897=ORIENTED_EDGE('',*,*,#2701,.T.);
#3898=DIRECTION('',(0.,1.,0.));
#3899=VECTOR('',#3898,1.);
#3900=CARTESIAN_POINT('',(18.8177846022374,3.30222231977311,23.5183332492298));
#3901=LINE('',#3900,#3899);
#3902=EDGE_CURVE('P1_E837',#3884,#2690,#3901,.T.);
#3903=ORIENTED_EDGE('',*,*,#3902,.F.);
#3904=EDGE_LOOP('',(#3888,#3895,#3896,#3897,#3903));
#3905=FACE_BOUND('',#3904,.T.);
#3906=ADVANCED_FACE('P1_F878',(#3905),#3877,.F.);
#3907=CARTESIAN_POINT('',(18.8177846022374,3.30222231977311,23.5183332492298));
#3908=DIRECTION('',(0.,0.,-1.));
#3909=DIRECTION('',(-1.,0.,0.));
#3910=AXIS2_PLACEMENT_3D('',#3907,#3908,#3909);
#3911=PLANE('',#3910);
#3912=ORIENTED_EDGE('',*,*,#3843,.F.);
#3913=DIRECTION('',(-1.,0.,0.));
#3914=VECTOR('',#3913,1.);
#3915=CARTESIAN_POINT('',(18.8177846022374,4.10222231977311,23.5183332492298));
#3916=LINE('',#3915,#3914);
#3917=EDGE_CURVE('P1_E807',#3836,#3884,#3916,.F.);
#3918=ORIENTED_EDGE('',*,*,#3917,.T.);
#3919=ORIENTED_EDGE('',*,*,#3902,.T.);
#3920=ORIENTED_EDGE('',*,*,#2693,.T.);
#3921=EDGE_LOOP('',(#3912,#3918,#3919,#3920));
#3922=FACE_BOUND('',#3921,.T.);
#3923=ADVANCED_FACE('P1_F871',(#3922),#3911,.F.);
#3924=CARTESIAN_POINT('',(-4.18221539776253,3.30222231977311,23.5183332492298));
#3925=DIRECTION('',(1.,0.,0.));
#3926=DIRECTION('',(0.,0.,-1.));
#3927=AXIS2_PLACEMENT_3D('',#3924,#3925,#3926);
#3928=PLANE('',#3927);
#3929=DIRECTION('',(0.,1.,0.));
#3930=VECTOR('',#3929,1.);
#3931=CARTESIAN_POINT('',(-4.18221539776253,3.30222231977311,22.0183332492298));
#3932=LINE('',#3931,#3930);
#3933=CARTESIAN_POINT('',(-4.18221539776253,4.09594771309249,22.0183332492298));
#3934=VERTEX_POINT('',#3933);
#3935=EDGE_CURVE('P1_E833',#3934,#2742,#3932,.T.);
#3936=ORIENTED_EDGE('',*,*,#3935,.F.);
#3937=CARTESIAN_POINT('',(-4.18221539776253,4.09594771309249,22.8183332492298));
#3938=DIRECTION('',(1.,0.,0.));
#3939=DIRECTION('',(0.,0.,-1.));
#3940=AXIS2_PLACEMENT_3D('',#3937,#3938,#3939);
#3941=CIRCLE('',#3940,0.8);
#3942=CARTESIAN_POINT('',(-4.18221539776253,3.30222231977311,22.7183332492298));
#3943=VERTEX_POINT('',#3942);
#3944=EDGE_CURVE('P1_E11',#3934,#3943,#3941,.F.);
#3945=ORIENTED_EDGE('',*,*,#3944,.T.);
#3946=CARTESIAN_POINT('',(-4.18221539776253,4.10222231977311,22.7183332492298));
#3947=DIRECTION('',(1.,0.,0.));
#3948=DIRECTION('',(0.,0.,-1.));
#3949=AXIS2_PLACEMENT_3D('',#3946,#3947,#3948);
#3950=CIRCLE('',#3949,0.8);
#3951=CARTESIAN_POINT('',(-4.18221539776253,4.10222231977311,23.5183332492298));
#3952=VERTEX_POINT('',#3951);
#3953=EDGE_CURVE('P1_E403',#3943,#3952,#3950,.F.);
#3954=ORIENTED_EDGE('',*,*,#3953,.T.);
#3955=DIRECTION('',(0.,1.,0.));
#3956=VECTOR('',#3955,1.);
#3957=CARTESIAN_POINT('',(-4.18221539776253,3.30222231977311,23.5183332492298));
#3958=LINE('',#3957,#3956);
#3959=EDGE_CURVE('P1_E398',#3952,#2726,#3958,.T.);
#3960=ORIENTED_EDGE('',*,*,#3959,.T.);
#3961=ORIENTED_EDGE('',*,*,#2749,.T.);
#3962=EDGE_LOOP('',(#3936,#3945,#3954,#3960,#3961));
#3963=FACE_BOUND('',#3962,.T.);
#3964=ADVANCED_FACE('P1_F400',(#3963),#3928,.F.);
#3965=CARTESIAN_POINT('',(-3.68221539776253,3.30222231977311,22.0183332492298));
#3966=DIRECTION('',(0.,0.,1.));
#3967=DIRECTION('',(1.,0.,0.));
#3968=AXIS2_PLACEMENT_3D('',#3965,#3966,#3967);
#3969=PLANE('',#3968);
#3970=DIRECTION('',(0.,1.,0.));
#3971=VECTOR('',#3970,1.);
#3972=CARTESIAN_POINT('',(-3.68221539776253,3.30222231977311,22.0183332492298));
#3973=LINE('',#3972,#3971);
#3974=CARTESIAN_POINT('',(-3.68221539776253,4.09594771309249,22.0183332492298));
#3975=VERTEX_POINT('',#3974);
#3976=EDGE_CURVE('P1_E835',#3975,#2734,#3973,.T.);
#3977=ORIENTED_EDGE('',*,*,#3976,.F.);
#3978=DIRECTION('',(-1.,0.,0.));
#3979=VECTOR('',#3978,1.);
#3980=CARTESIAN_POINT('',(-3.68221539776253,4.09594771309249,22.0183332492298));
#3981=LINE('',#3980,#3979);
#3982=EDGE_CURVE('P1_E25',#3975,#3934,#3981,.T.);
#3983=ORIENTED_EDGE('',*,*,#3982,.T.);
#3984=ORIENTED_EDGE('',*,*,#3935,.T.);
#3985=ORIENTED_EDGE('',*,*,#2743,.T.);
#3986=EDGE_LOOP('',(#3977,#3983,#3984,#3985));
#3987=FACE_BOUND('',#3986,.T.);
#3988=ADVANCED_FACE('P1_F1521',(#3987),#3969,.F.);
#3989=CARTESIAN_POINT('',(-3.68221539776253,3.30222231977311,23.5183332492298));
#3990=DIRECTION('',(-1.,0.,0.));
#3991=DIRECTION('',(0.,0.,1.));
#3992=AXIS2_PLACEMENT_3D('',#3989,#3990,#3991);
#3993=PLANE('',#3992);
#3994=CARTESIAN_POINT('',(-3.68221539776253,4.10222231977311,22.7183332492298));
#3995=DIRECTION('',(-1.,0.,0.));
#3996=DIRECTION('',(0.,0.,1.));
#3997=AXIS2_PLACEMENT_3D('',#3994,#3995,#3996);
#3998=CIRCLE('',#3997,0.8);
#3999=CARTESIAN_POINT('',(-3.68221539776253,4.10222231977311,23.5183332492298));
#4000=VERTEX_POINT('',#3999);
#4001=CARTESIAN_POINT('',(-3.68221539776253,3.30222231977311,22.7183332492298));
#4002=VERTEX_POINT('',#4001);
#4003=EDGE_CURVE('P1_E824',#4000,#4002,#3998,.F.);
#4004=ORIENTED_EDGE('',*,*,#4003,.T.);
#4005=CARTESIAN_POINT('',(-3.68221539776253,4.09594771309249,22.8183332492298));
#4006=DIRECTION('',(-1.,0.,0.));
#4007=DIRECTION('',(0.,0.,1.));
#4008=AXIS2_PLACEMENT_3D('',#4005,#4006,#4007);
#4009=CIRCLE('',#4008,0.8);
#4010=EDGE_CURVE('P1_E39',#4002,#3975,#4009,.F.);
#4011=ORIENTED_EDGE('',*,*,#4010,.T.);
#4012=ORIENTED_EDGE('',*,*,#3976,.T.);
#4013=ORIENTED_EDGE('',*,*,#2735,.T.);
#4014=DIRECTION('',(0.,1.,0.));
#4015=VECTOR('',#4014,1.);
#4016=CARTESIAN_POINT('',(-3.68221539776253,3.30222231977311,23.5183332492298));
#4017=LINE('',#4016,#4015);
#4018=EDGE_CURVE('P1_E407',#4000,#2724,#4017,.T.);
#4019=ORIENTED_EDGE('',*,*,#4018,.F.);
#4020=EDGE_LOOP('',(#4004,#4011,#4012,#4013,#4019));
#4021=FACE_BOUND('',#4020,.T.);
#4022=ADVANCED_FACE('P1_F828',(#4021),#3993,.F.);
#4023=CARTESIAN_POINT('',(-3.68221539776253,3.30222231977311,23.5183332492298));
#4024=DIRECTION('',(0.,0.,-1.));
#4025=DIRECTION('',(-1.,0.,0.));
#4026=AXIS2_PLACEMENT_3D('',#4023,#4024,#4025);
#4027=PLANE('',#4026);
#4028=ORIENTED_EDGE('',*,*,#3959,.F.);
#4029=DIRECTION('',(-1.,0.,0.));
#4030=VECTOR('',#4029,1.);
#4031=CARTESIAN_POINT('',(-3.68221539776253,4.10222231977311,23.5183332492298));
#4032=LINE('',#4031,#4030);
#4033=EDGE_CURVE('P1_E822',#3952,#4000,#4032,.F.);
#4034=ORIENTED_EDGE('',*,*,#4033,.T.);
#4035=ORIENTED_EDGE('',*,*,#4018,.T.);
#4036=ORIENTED_EDGE('',*,*,#2727,.T.);
#4037=EDGE_LOOP('',(#4028,#4034,#4035,#4036));
#4038=FACE_BOUND('',#4037,.T.);
#4039=ADVANCED_FACE('P1_F420',(#4038),#4027,.F.);
#4040=CARTESIAN_POINT('',(151.961726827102,4.10222231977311,22.7183332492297));
#4041=DIRECTION('',(-1.,0.,0.));
#4042=DIRECTION('',(0.,0.,1.));
#4043=AXIS2_PLACEMENT_3D('',#4040,#4041,#4042);
#4044=CYLINDRICAL_SURFACE('',#4043,0.8);
#4045=ORIENTED_EDGE('',*,*,#3887,.F.);
#4046=ORIENTED_EDGE('',*,*,#3917,.F.);
#4047=ORIENTED_EDGE('',*,*,#3837,.F.);
#4048=DIRECTION('',(-1.,0.,0.));
#4049=VECTOR('',#4048,1.);
#4050=CARTESIAN_POINT('',(151.961726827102,3.30222231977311,22.7183332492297));
#4051=LINE('',#4050,#4049);
#4052=EDGE_CURVE('P1_E802',#3886,#3827,#4051,.T.);
#4053=ORIENTED_EDGE('',*,*,#4052,.F.);
#4054=EDGE_LOOP('',(#4045,#4046,#4047,#4053));
#4055=FACE_BOUND('',#4054,.T.);
#4056=ADVANCED_FACE('P1_F875',(#4055),#4044,.T.);
#4057=CARTESIAN_POINT('',(151.961726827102,4.09594771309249,22.8183332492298));
#4058=DIRECTION('',(-1.,0.,0.));
#4059=DIRECTION('',(0.,0.,1.));
#4060=AXIS2_PLACEMENT_3D('',#4057,#4058,#4059);
#4061=CYLINDRICAL_SURFACE('',#4060,0.8);
#4062=ORIENTED_EDGE('',*,*,#3828,.F.);
#4063=ORIENTED_EDGE('',*,*,#3866,.F.);
#4064=ORIENTED_EDGE('',*,*,#3894,.F.);
#4065=ORIENTED_EDGE('',*,*,#4052,.T.);
#4066=EDGE_LOOP('',(#4062,#4063,#4064,#4065));
#4067=FACE_BOUND('',#4066,.T.);
#4068=ADVANCED_FACE('P1_F880',(#4067),#4061,.T.);
#4069=CARTESIAN_POINT('',(151.961726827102,4.10222231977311,22.7183332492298));
#4070=DIRECTION('',(-1.,0.,0.));
#4071=DIRECTION('',(0.,0.,1.));
#4072=AXIS2_PLACEMENT_3D('',#4069,#4070,#4071);
#4073=CYLINDRICAL_SURFACE('',#4072,0.8);
#4074=ORIENTED_EDGE('',*,*,#4003,.F.);
#4075=ORIENTED_EDGE('',*,*,#4033,.F.);
#4076=ORIENTED_EDGE('',*,*,#3953,.F.);
#4077=DIRECTION('',(-1.,0.,0.));
#4078=VECTOR('',#4077,1.);
#4079=CARTESIAN_POINT('',(151.961726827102,3.30222231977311,22.7183332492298));
#4080=LINE('',#4079,#4078);
#4081=EDGE_CURVE('P1_E818',#4002,#3943,#4080,.T.);
#4082=ORIENTED_EDGE('',*,*,#4081,.F.);
#4083=EDGE_LOOP('',(#4074,#4075,#4076,#4082));
#4084=FACE_BOUND('',#4083,.T.);
#4085=ADVANCED_FACE('P1_F830',(#4084),#4073,.T.);
#4086=CARTESIAN_POINT('',(151.961726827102,4.09594771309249,22.8183332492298));
#4087=DIRECTION('',(-1.,0.,0.));
#4088=DIRECTION('',(0.,0.,1.));
#4089=AXIS2_PLACEMENT_3D('',#4086,#4087,#4088);
#4090=CYLINDRICAL_SURFACE('',#4089,0.8);
#4091=ORIENTED_EDGE('',*,*,#3944,.F.);
#4092=ORIENTED_EDGE('',*,*,#3982,.F.);
#4093=ORIENTED_EDGE('',*,*,#4010,.F.);
#4094=ORIENTED_EDGE('',*,*,#4081,.T.);
#4095=EDGE_LOOP('',(#4091,#4092,#4093,#4094));
#4096=FACE_BOUND('',#4095,.T.);
#4097=ADVANCED_FACE('P1_F19',(#4096),#4090,.T.);
#4098=CLOSED_SHELL('',(#2116,#2165,#2353,#2375,#2434,#2474,#2533,#2679,#2810,#2851,#2892,#2904,
#2930,#2954,#2978,#3002,#3026,#3050,#3074,#3098,#3122,#3146,#3170,#3187,#3210,#3227,#3247,#3259,
#3269,#3300,#3324,#3348,#3372,#3396,#3444,#3468,#3492,#3516,#3540,#3564,#3581,#3601,#3623,#3635,
#3647,#3680,#3711,#3735,#3747,#3759,#3771,#3783,#3795,#3807,#3848,#3872,#3906,#3923,#3964,#3988,
#4022,#4039,#4056,#4068,#4085,#4097));
#4099=MANIFOLD_SOLID_BREP('P1_B1',#4098);
#4100=ADVANCED_BREP_SHAPE_REPRESENTATION('',(#18,#2076,#4099),#14);
#4101=SHAPE_DEFINITION_REPRESENTATION(#9,#4100);
ENDSEC;
END-ISO-10303-21;
